VERSION 5.8 ;
BUSBITCHARS "[]" ;
DIVIDERCHAR "/" ;
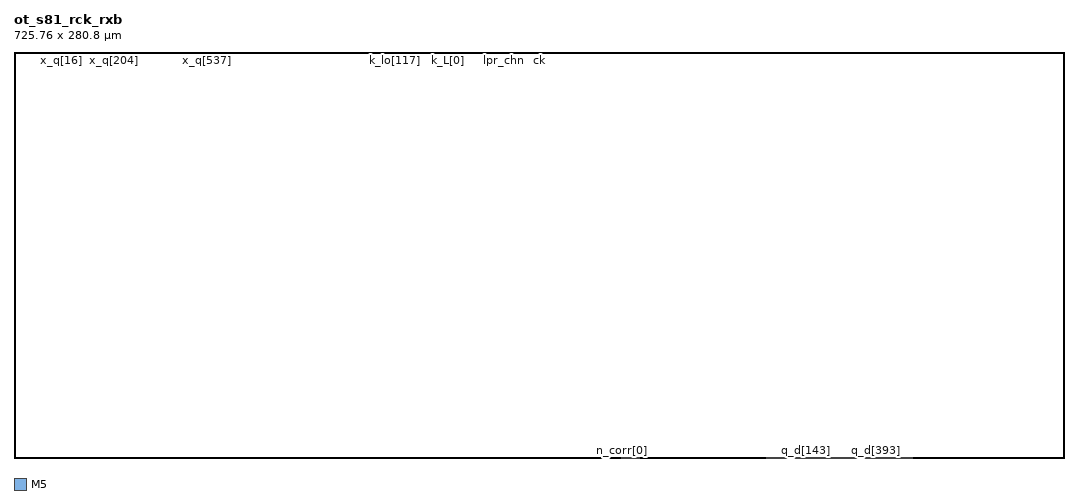
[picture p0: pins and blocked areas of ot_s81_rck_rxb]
MACRO ot_s81_rck_rxb
 CLASS BLOCK ;
 ORIGIN 0 0 ;
 SIZE 725.76 BY 280.8 ;
 SYMMETRY X Y ;
 PIN x_q[0]
  DIRECTION INPUT ;
  USE SIGNAL ;
  PORT
   LAYER M5 ;
   RECT 30.000 280.716 30.024 280.800 ;
  END
 END x_q[0]
 PIN x_q[1]
  DIRECTION INPUT ;
  USE SIGNAL ;
  PORT
   LAYER M5 ;
   RECT 30.192 280.716 30.216 280.800 ;
  END
 END x_q[1]
 PIN x_q[2]
  DIRECTION INPUT ;
  USE SIGNAL ;
  PORT
   LAYER M5 ;
   RECT 30.384 280.716 30.408 280.800 ;
  END
 END x_q[2]
 PIN x_q[3]
  DIRECTION INPUT ;
  USE SIGNAL ;
  PORT
   LAYER M5 ;
   RECT 30.576 280.716 30.600 280.800 ;
  END
 END x_q[3]
 PIN x_q[4]
  DIRECTION INPUT ;
  USE SIGNAL ;
  PORT
   LAYER M5 ;
   RECT 30.768 280.716 30.792 280.800 ;
  END
 END x_q[4]
 PIN x_q[5]
  DIRECTION INPUT ;
  USE SIGNAL ;
  PORT
   LAYER M5 ;
   RECT 30.960 280.716 30.984 280.800 ;
  END
 END x_q[5]
 PIN x_q[6]
  DIRECTION INPUT ;
  USE SIGNAL ;
  PORT
   LAYER M5 ;
   RECT 31.152 280.716 31.176 280.800 ;
  END
 END x_q[6]
 PIN x_q[7]
  DIRECTION INPUT ;
  USE SIGNAL ;
  PORT
   LAYER M5 ;
   RECT 31.344 280.716 31.368 280.800 ;
  END
 END x_q[7]
 PIN x_q[8]
  DIRECTION INPUT ;
  USE SIGNAL ;
  PORT
   LAYER M5 ;
   RECT 31.536 280.716 31.560 280.800 ;
  END
 END x_q[8]
 PIN x_q[9]
  DIRECTION INPUT ;
  USE SIGNAL ;
  PORT
   LAYER M5 ;
   RECT 31.728 280.716 31.752 280.800 ;
  END
 END x_q[9]
 PIN x_q[10]
  DIRECTION INPUT ;
  USE SIGNAL ;
  PORT
   LAYER M5 ;
   RECT 31.920 280.716 31.944 280.800 ;
  END
 END x_q[10]
 PIN x_q[11]
  DIRECTION INPUT ;
  USE SIGNAL ;
  PORT
   LAYER M5 ;
   RECT 32.112 280.716 32.136 280.800 ;
  END
 END x_q[11]
 PIN x_q[12]
  DIRECTION INPUT ;
  USE SIGNAL ;
  PORT
   LAYER M5 ;
   RECT 32.304 280.716 32.328 280.800 ;
  END
 END x_q[12]
 PIN x_q[13]
  DIRECTION INPUT ;
  USE SIGNAL ;
  PORT
   LAYER M5 ;
   RECT 32.496 280.716 32.520 280.800 ;
  END
 END x_q[13]
 PIN x_q[14]
  DIRECTION INPUT ;
  USE SIGNAL ;
  PORT
   LAYER M5 ;
   RECT 32.688 280.716 32.712 280.800 ;
  END
 END x_q[14]
 PIN x_q[15]
  DIRECTION INPUT ;
  USE SIGNAL ;
  PORT
   LAYER M5 ;
   RECT 32.880 280.716 32.904 280.800 ;
  END
 END x_q[15]
 PIN x_q[16]
  DIRECTION INPUT ;
  USE SIGNAL ;
  PORT
   LAYER M5 ;
   RECT 33.072 280.716 33.096 280.800 ;
  END
 END x_q[16]
 PIN x_q[17]
  DIRECTION INPUT ;
  USE SIGNAL ;
  PORT
   LAYER M5 ;
   RECT 33.264 280.716 33.288 280.800 ;
  END
 END x_q[17]
 PIN x_q[18]
  DIRECTION INPUT ;
  USE SIGNAL ;
  PORT
   LAYER M5 ;
   RECT 33.456 280.716 33.480 280.800 ;
  END
 END x_q[18]
 PIN x_q[19]
  DIRECTION INPUT ;
  USE SIGNAL ;
  PORT
   LAYER M5 ;
   RECT 33.648 280.716 33.672 280.800 ;
  END
 END x_q[19]
 PIN x_q[20]
  DIRECTION INPUT ;
  USE SIGNAL ;
  PORT
   LAYER M5 ;
   RECT 33.840 280.716 33.864 280.800 ;
  END
 END x_q[20]
 PIN x_q[21]
  DIRECTION INPUT ;
  USE SIGNAL ;
  PORT
   LAYER M5 ;
   RECT 34.032 280.716 34.056 280.800 ;
  END
 END x_q[21]
 PIN x_q[22]
  DIRECTION INPUT ;
  USE SIGNAL ;
  PORT
   LAYER M5 ;
   RECT 34.224 280.716 34.248 280.800 ;
  END
 END x_q[22]
 PIN x_q[23]
  DIRECTION INPUT ;
  USE SIGNAL ;
  PORT
   LAYER M5 ;
   RECT 34.416 280.716 34.440 280.800 ;
  END
 END x_q[23]
 PIN x_q[24]
  DIRECTION INPUT ;
  USE SIGNAL ;
  PORT
   LAYER M5 ;
   RECT 34.608 280.716 34.632 280.800 ;
  END
 END x_q[24]
 PIN x_q[25]
  DIRECTION INPUT ;
  USE SIGNAL ;
  PORT
   LAYER M5 ;
   RECT 34.800 280.716 34.824 280.800 ;
  END
 END x_q[25]
 PIN x_q[26]
  DIRECTION INPUT ;
  USE SIGNAL ;
  PORT
   LAYER M5 ;
   RECT 34.992 280.716 35.016 280.800 ;
  END
 END x_q[26]
 PIN x_q[27]
  DIRECTION INPUT ;
  USE SIGNAL ;
  PORT
   LAYER M5 ;
   RECT 35.184 280.716 35.208 280.800 ;
  END
 END x_q[27]
 PIN x_q[28]
  DIRECTION INPUT ;
  USE SIGNAL ;
  PORT
   LAYER M5 ;
   RECT 35.376 280.716 35.400 280.800 ;
  END
 END x_q[28]
 PIN x_q[29]
  DIRECTION INPUT ;
  USE SIGNAL ;
  PORT
   LAYER M5 ;
   RECT 35.568 280.716 35.592 280.800 ;
  END
 END x_q[29]
 PIN x_q[30]
  DIRECTION INPUT ;
  USE SIGNAL ;
  PORT
   LAYER M5 ;
   RECT 35.760 280.716 35.784 280.800 ;
  END
 END x_q[30]
 PIN x_q[31]
  DIRECTION INPUT ;
  USE SIGNAL ;
  PORT
   LAYER M5 ;
   RECT 35.952 280.716 35.976 280.800 ;
  END
 END x_q[31]
 PIN x_q[32]
  DIRECTION INPUT ;
  USE SIGNAL ;
  PORT
   LAYER M5 ;
   RECT 36.144 280.716 36.168 280.800 ;
  END
 END x_q[32]
 PIN x_q[33]
  DIRECTION INPUT ;
  USE SIGNAL ;
  PORT
   LAYER M5 ;
   RECT 36.336 280.716 36.360 280.800 ;
  END
 END x_q[33]
 PIN x_q[34]
  DIRECTION INPUT ;
  USE SIGNAL ;
  PORT
   LAYER M5 ;
   RECT 36.528 280.716 36.552 280.800 ;
  END
 END x_q[34]
 PIN x_q[35]
  DIRECTION INPUT ;
  USE SIGNAL ;
  PORT
   LAYER M5 ;
   RECT 36.720 280.716 36.744 280.800 ;
  END
 END x_q[35]
 PIN x_q[36]
  DIRECTION INPUT ;
  USE SIGNAL ;
  PORT
   LAYER M5 ;
   RECT 36.912 280.716 36.936 280.800 ;
  END
 END x_q[36]
 PIN x_q[37]
  DIRECTION INPUT ;
  USE SIGNAL ;
  PORT
   LAYER M5 ;
   RECT 37.104 280.716 37.128 280.800 ;
  END
 END x_q[37]
 PIN x_q[38]
  DIRECTION INPUT ;
  USE SIGNAL ;
  PORT
   LAYER M5 ;
   RECT 37.296 280.716 37.320 280.800 ;
  END
 END x_q[38]
 PIN x_q[39]
  DIRECTION INPUT ;
  USE SIGNAL ;
  PORT
   LAYER M5 ;
   RECT 37.488 280.716 37.512 280.800 ;
  END
 END x_q[39]
 PIN x_q[40]
  DIRECTION INPUT ;
  USE SIGNAL ;
  PORT
   LAYER M5 ;
   RECT 37.680 280.716 37.704 280.800 ;
  END
 END x_q[40]
 PIN x_q[41]
  DIRECTION INPUT ;
  USE SIGNAL ;
  PORT
   LAYER M5 ;
   RECT 37.872 280.716 37.896 280.800 ;
  END
 END x_q[41]
 PIN x_q[42]
  DIRECTION INPUT ;
  USE SIGNAL ;
  PORT
   LAYER M5 ;
   RECT 38.064 280.716 38.088 280.800 ;
  END
 END x_q[42]
 PIN x_q[43]
  DIRECTION INPUT ;
  USE SIGNAL ;
  PORT
   LAYER M5 ;
   RECT 38.256 280.716 38.280 280.800 ;
  END
 END x_q[43]
 PIN x_q[44]
  DIRECTION INPUT ;
  USE SIGNAL ;
  PORT
   LAYER M5 ;
   RECT 38.448 280.716 38.472 280.800 ;
  END
 END x_q[44]
 PIN x_q[45]
  DIRECTION INPUT ;
  USE SIGNAL ;
  PORT
   LAYER M5 ;
   RECT 38.640 280.716 38.664 280.800 ;
  END
 END x_q[45]
 PIN x_q[46]
  DIRECTION INPUT ;
  USE SIGNAL ;
  PORT
   LAYER M5 ;
   RECT 38.832 280.716 38.856 280.800 ;
  END
 END x_q[46]
 PIN x_q[47]
  DIRECTION INPUT ;
  USE SIGNAL ;
  PORT
   LAYER M5 ;
   RECT 39.024 280.716 39.048 280.800 ;
  END
 END x_q[47]
 PIN x_q[48]
  DIRECTION INPUT ;
  USE SIGNAL ;
  PORT
   LAYER M5 ;
   RECT 39.216 280.716 39.240 280.800 ;
  END
 END x_q[48]
 PIN x_q[49]
  DIRECTION INPUT ;
  USE SIGNAL ;
  PORT
   LAYER M5 ;
   RECT 39.408 280.716 39.432 280.800 ;
  END
 END x_q[49]
 PIN x_q[50]
  DIRECTION INPUT ;
  USE SIGNAL ;
  PORT
   LAYER M5 ;
   RECT 39.600 280.716 39.624 280.800 ;
  END
 END x_q[50]
 PIN x_q[51]
  DIRECTION INPUT ;
  USE SIGNAL ;
  PORT
   LAYER M5 ;
   RECT 39.792 280.716 39.816 280.800 ;
  END
 END x_q[51]
 PIN x_q[52]
  DIRECTION INPUT ;
  USE SIGNAL ;
  PORT
   LAYER M5 ;
   RECT 39.984 280.716 40.008 280.800 ;
  END
 END x_q[52]
 PIN x_q[53]
  DIRECTION INPUT ;
  USE SIGNAL ;
  PORT
   LAYER M5 ;
   RECT 40.176 280.716 40.200 280.800 ;
  END
 END x_q[53]
 PIN x_q[54]
  DIRECTION INPUT ;
  USE SIGNAL ;
  PORT
   LAYER M5 ;
   RECT 40.368 280.716 40.392 280.800 ;
  END
 END x_q[54]
 PIN x_q[55]
  DIRECTION INPUT ;
  USE SIGNAL ;
  PORT
   LAYER M5 ;
   RECT 40.560 280.716 40.584 280.800 ;
  END
 END x_q[55]
 PIN x_q[56]
  DIRECTION INPUT ;
  USE SIGNAL ;
  PORT
   LAYER M5 ;
   RECT 40.752 280.716 40.776 280.800 ;
  END
 END x_q[56]
 PIN x_q[57]
  DIRECTION INPUT ;
  USE SIGNAL ;
  PORT
   LAYER M5 ;
   RECT 40.944 280.716 40.968 280.800 ;
  END
 END x_q[57]
 PIN x_q[58]
  DIRECTION INPUT ;
  USE SIGNAL ;
  PORT
   LAYER M5 ;
   RECT 41.136 280.716 41.160 280.800 ;
  END
 END x_q[58]
 PIN x_q[59]
  DIRECTION INPUT ;
  USE SIGNAL ;
  PORT
   LAYER M5 ;
   RECT 41.328 280.716 41.352 280.800 ;
  END
 END x_q[59]
 PIN x_q[60]
  DIRECTION INPUT ;
  USE SIGNAL ;
  PORT
   LAYER M5 ;
   RECT 41.520 280.716 41.544 280.800 ;
  END
 END x_q[60]
 PIN x_q[61]
  DIRECTION INPUT ;
  USE SIGNAL ;
  PORT
   LAYER M5 ;
   RECT 41.712 280.716 41.736 280.800 ;
  END
 END x_q[61]
 PIN x_q[62]
  DIRECTION INPUT ;
  USE SIGNAL ;
  PORT
   LAYER M5 ;
   RECT 41.904 280.716 41.928 280.800 ;
  END
 END x_q[62]
 PIN x_q[63]
  DIRECTION INPUT ;
  USE SIGNAL ;
  PORT
   LAYER M5 ;
   RECT 42.096 280.716 42.120 280.800 ;
  END
 END x_q[63]
 PIN x_q[64]
  DIRECTION INPUT ;
  USE SIGNAL ;
  PORT
   LAYER M5 ;
   RECT 42.288 280.716 42.312 280.800 ;
  END
 END x_q[64]
 PIN x_q[65]
  DIRECTION INPUT ;
  USE SIGNAL ;
  PORT
   LAYER M5 ;
   RECT 42.480 280.716 42.504 280.800 ;
  END
 END x_q[65]
 PIN x_q[66]
  DIRECTION INPUT ;
  USE SIGNAL ;
  PORT
   LAYER M5 ;
   RECT 42.672 280.716 42.696 280.800 ;
  END
 END x_q[66]
 PIN x_q[67]
  DIRECTION INPUT ;
  USE SIGNAL ;
  PORT
   LAYER M5 ;
   RECT 42.864 280.716 42.888 280.800 ;
  END
 END x_q[67]
 PIN x_q[68]
  DIRECTION INPUT ;
  USE SIGNAL ;
  PORT
   LAYER M5 ;
   RECT 43.056 280.716 43.080 280.800 ;
  END
 END x_q[68]
 PIN x_q[69]
  DIRECTION INPUT ;
  USE SIGNAL ;
  PORT
   LAYER M5 ;
   RECT 43.248 280.716 43.272 280.800 ;
  END
 END x_q[69]
 PIN x_q[70]
  DIRECTION INPUT ;
  USE SIGNAL ;
  PORT
   LAYER M5 ;
   RECT 43.440 280.716 43.464 280.800 ;
  END
 END x_q[70]
 PIN x_q[71]
  DIRECTION INPUT ;
  USE SIGNAL ;
  PORT
   LAYER M5 ;
   RECT 43.632 280.716 43.656 280.800 ;
  END
 END x_q[71]
 PIN x_q[72]
  DIRECTION INPUT ;
  USE SIGNAL ;
  PORT
   LAYER M5 ;
   RECT 43.824 280.716 43.848 280.800 ;
  END
 END x_q[72]
 PIN x_q[73]
  DIRECTION INPUT ;
  USE SIGNAL ;
  PORT
   LAYER M5 ;
   RECT 44.016 280.716 44.040 280.800 ;
  END
 END x_q[73]
 PIN x_q[74]
  DIRECTION INPUT ;
  USE SIGNAL ;
  PORT
   LAYER M5 ;
   RECT 44.208 280.716 44.232 280.800 ;
  END
 END x_q[74]
 PIN x_q[75]
  DIRECTION INPUT ;
  USE SIGNAL ;
  PORT
   LAYER M5 ;
   RECT 44.400 280.716 44.424 280.800 ;
  END
 END x_q[75]
 PIN x_q[76]
  DIRECTION INPUT ;
  USE SIGNAL ;
  PORT
   LAYER M5 ;
   RECT 44.592 280.716 44.616 280.800 ;
  END
 END x_q[76]
 PIN x_q[77]
  DIRECTION INPUT ;
  USE SIGNAL ;
  PORT
   LAYER M5 ;
   RECT 44.784 280.716 44.808 280.800 ;
  END
 END x_q[77]
 PIN x_q[78]
  DIRECTION INPUT ;
  USE SIGNAL ;
  PORT
   LAYER M5 ;
   RECT 44.976 280.716 45.000 280.800 ;
  END
 END x_q[78]
 PIN x_q[79]
  DIRECTION INPUT ;
  USE SIGNAL ;
  PORT
   LAYER M5 ;
   RECT 45.168 280.716 45.192 280.800 ;
  END
 END x_q[79]
 PIN x_q[80]
  DIRECTION INPUT ;
  USE SIGNAL ;
  PORT
   LAYER M5 ;
   RECT 45.360 280.716 45.384 280.800 ;
  END
 END x_q[80]
 PIN x_q[81]
  DIRECTION INPUT ;
  USE SIGNAL ;
  PORT
   LAYER M5 ;
   RECT 45.552 280.716 45.576 280.800 ;
  END
 END x_q[81]
 PIN x_q[82]
  DIRECTION INPUT ;
  USE SIGNAL ;
  PORT
   LAYER M5 ;
   RECT 45.744 280.716 45.768 280.800 ;
  END
 END x_q[82]
 PIN x_q[83]
  DIRECTION INPUT ;
  USE SIGNAL ;
  PORT
   LAYER M5 ;
   RECT 45.936 280.716 45.960 280.800 ;
  END
 END x_q[83]
 PIN x_q[84]
  DIRECTION INPUT ;
  USE SIGNAL ;
  PORT
   LAYER M5 ;
   RECT 46.128 280.716 46.152 280.800 ;
  END
 END x_q[84]
 PIN x_q[85]
  DIRECTION INPUT ;
  USE SIGNAL ;
  PORT
   LAYER M5 ;
   RECT 46.320 280.716 46.344 280.800 ;
  END
 END x_q[85]
 PIN x_q[86]
  DIRECTION INPUT ;
  USE SIGNAL ;
  PORT
   LAYER M5 ;
   RECT 46.512 280.716 46.536 280.800 ;
  END
 END x_q[86]
 PIN x_q[87]
  DIRECTION INPUT ;
  USE SIGNAL ;
  PORT
   LAYER M5 ;
   RECT 46.704 280.716 46.728 280.800 ;
  END
 END x_q[87]
 PIN x_q[88]
  DIRECTION INPUT ;
  USE SIGNAL ;
  PORT
   LAYER M5 ;
   RECT 46.896 280.716 46.920 280.800 ;
  END
 END x_q[88]
 PIN x_q[89]
  DIRECTION INPUT ;
  USE SIGNAL ;
  PORT
   LAYER M5 ;
   RECT 47.088 280.716 47.112 280.800 ;
  END
 END x_q[89]
 PIN x_q[90]
  DIRECTION INPUT ;
  USE SIGNAL ;
  PORT
   LAYER M5 ;
   RECT 47.280 280.716 47.304 280.800 ;
  END
 END x_q[90]
 PIN x_q[91]
  DIRECTION INPUT ;
  USE SIGNAL ;
  PORT
   LAYER M5 ;
   RECT 47.472 280.716 47.496 280.800 ;
  END
 END x_q[91]
 PIN x_q[92]
  DIRECTION INPUT ;
  USE SIGNAL ;
  PORT
   LAYER M5 ;
   RECT 47.664 280.716 47.688 280.800 ;
  END
 END x_q[92]
 PIN x_q[93]
  DIRECTION INPUT ;
  USE SIGNAL ;
  PORT
   LAYER M5 ;
   RECT 47.856 280.716 47.880 280.800 ;
  END
 END x_q[93]
 PIN x_q[94]
  DIRECTION INPUT ;
  USE SIGNAL ;
  PORT
   LAYER M5 ;
   RECT 48.048 280.716 48.072 280.800 ;
  END
 END x_q[94]
 PIN x_q[95]
  DIRECTION INPUT ;
  USE SIGNAL ;
  PORT
   LAYER M5 ;
   RECT 48.240 280.716 48.264 280.800 ;
  END
 END x_q[95]
 PIN x_q[96]
  DIRECTION INPUT ;
  USE SIGNAL ;
  PORT
   LAYER M5 ;
   RECT 48.432 280.716 48.456 280.800 ;
  END
 END x_q[96]
 PIN x_q[97]
  DIRECTION INPUT ;
  USE SIGNAL ;
  PORT
   LAYER M5 ;
   RECT 48.624 280.716 48.648 280.800 ;
  END
 END x_q[97]
 PIN x_q[98]
  DIRECTION INPUT ;
  USE SIGNAL ;
  PORT
   LAYER M5 ;
   RECT 48.816 280.716 48.840 280.800 ;
  END
 END x_q[98]
 PIN x_q[99]
  DIRECTION INPUT ;
  USE SIGNAL ;
  PORT
   LAYER M5 ;
   RECT 49.008 280.716 49.032 280.800 ;
  END
 END x_q[99]
 PIN x_q[100]
  DIRECTION INPUT ;
  USE SIGNAL ;
  PORT
   LAYER M5 ;
   RECT 49.200 280.716 49.224 280.800 ;
  END
 END x_q[100]
 PIN x_q[101]
  DIRECTION INPUT ;
  USE SIGNAL ;
  PORT
   LAYER M5 ;
   RECT 49.392 280.716 49.416 280.800 ;
  END
 END x_q[101]
 PIN x_q[102]
  DIRECTION INPUT ;
  USE SIGNAL ;
  PORT
   LAYER M5 ;
   RECT 49.584 280.716 49.608 280.800 ;
  END
 END x_q[102]
 PIN x_q[103]
  DIRECTION INPUT ;
  USE SIGNAL ;
  PORT
   LAYER M5 ;
   RECT 49.776 280.716 49.800 280.800 ;
  END
 END x_q[103]
 PIN x_q[104]
  DIRECTION INPUT ;
  USE SIGNAL ;
  PORT
   LAYER M5 ;
   RECT 49.968 280.716 49.992 280.800 ;
  END
 END x_q[104]
 PIN x_q[105]
  DIRECTION INPUT ;
  USE SIGNAL ;
  PORT
   LAYER M5 ;
   RECT 50.160 280.716 50.184 280.800 ;
  END
 END x_q[105]
 PIN x_q[106]
  DIRECTION INPUT ;
  USE SIGNAL ;
  PORT
   LAYER M5 ;
   RECT 50.352 280.716 50.376 280.800 ;
  END
 END x_q[106]
 PIN x_q[107]
  DIRECTION INPUT ;
  USE SIGNAL ;
  PORT
   LAYER M5 ;
   RECT 50.544 280.716 50.568 280.800 ;
  END
 END x_q[107]
 PIN x_q[108]
  DIRECTION INPUT ;
  USE SIGNAL ;
  PORT
   LAYER M5 ;
   RECT 50.736 280.716 50.760 280.800 ;
  END
 END x_q[108]
 PIN x_q[109]
  DIRECTION INPUT ;
  USE SIGNAL ;
  PORT
   LAYER M5 ;
   RECT 50.928 280.716 50.952 280.800 ;
  END
 END x_q[109]
 PIN x_q[110]
  DIRECTION INPUT ;
  USE SIGNAL ;
  PORT
   LAYER M5 ;
   RECT 51.120 280.716 51.144 280.800 ;
  END
 END x_q[110]
 PIN x_q[111]
  DIRECTION INPUT ;
  USE SIGNAL ;
  PORT
   LAYER M5 ;
   RECT 51.312 280.716 51.336 280.800 ;
  END
 END x_q[111]
 PIN x_q[112]
  DIRECTION INPUT ;
  USE SIGNAL ;
  PORT
   LAYER M5 ;
   RECT 51.504 280.716 51.528 280.800 ;
  END
 END x_q[112]
 PIN x_q[113]
  DIRECTION INPUT ;
  USE SIGNAL ;
  PORT
   LAYER M5 ;
   RECT 51.696 280.716 51.720 280.800 ;
  END
 END x_q[113]
 PIN x_q[114]
  DIRECTION INPUT ;
  USE SIGNAL ;
  PORT
   LAYER M5 ;
   RECT 51.888 280.716 51.912 280.800 ;
  END
 END x_q[114]
 PIN x_q[115]
  DIRECTION INPUT ;
  USE SIGNAL ;
  PORT
   LAYER M5 ;
   RECT 52.080 280.716 52.104 280.800 ;
  END
 END x_q[115]
 PIN x_q[116]
  DIRECTION INPUT ;
  USE SIGNAL ;
  PORT
   LAYER M5 ;
   RECT 52.272 280.716 52.296 280.800 ;
  END
 END x_q[116]
 PIN x_q[117]
  DIRECTION INPUT ;
  USE SIGNAL ;
  PORT
   LAYER M5 ;
   RECT 52.464 280.716 52.488 280.800 ;
  END
 END x_q[117]
 PIN x_q[118]
  DIRECTION INPUT ;
  USE SIGNAL ;
  PORT
   LAYER M5 ;
   RECT 52.656 280.716 52.680 280.800 ;
  END
 END x_q[118]
 PIN x_q[119]
  DIRECTION INPUT ;
  USE SIGNAL ;
  PORT
   LAYER M5 ;
   RECT 52.848 280.716 52.872 280.800 ;
  END
 END x_q[119]
 PIN x_q[120]
  DIRECTION INPUT ;
  USE SIGNAL ;
  PORT
   LAYER M5 ;
   RECT 53.040 280.716 53.064 280.800 ;
  END
 END x_q[120]
 PIN x_q[121]
  DIRECTION INPUT ;
  USE SIGNAL ;
  PORT
   LAYER M5 ;
   RECT 53.232 280.716 53.256 280.800 ;
  END
 END x_q[121]
 PIN x_q[122]
  DIRECTION INPUT ;
  USE SIGNAL ;
  PORT
   LAYER M5 ;
   RECT 53.424 280.716 53.448 280.800 ;
  END
 END x_q[122]
 PIN x_q[123]
  DIRECTION INPUT ;
  USE SIGNAL ;
  PORT
   LAYER M5 ;
   RECT 53.616 280.716 53.640 280.800 ;
  END
 END x_q[123]
 PIN x_q[124]
  DIRECTION INPUT ;
  USE SIGNAL ;
  PORT
   LAYER M5 ;
   RECT 53.808 280.716 53.832 280.800 ;
  END
 END x_q[124]
 PIN x_q[125]
  DIRECTION INPUT ;
  USE SIGNAL ;
  PORT
   LAYER M5 ;
   RECT 54.000 280.716 54.024 280.800 ;
  END
 END x_q[125]
 PIN x_q[126]
  DIRECTION INPUT ;
  USE SIGNAL ;
  PORT
   LAYER M5 ;
   RECT 54.192 280.716 54.216 280.800 ;
  END
 END x_q[126]
 PIN x_q[127]
  DIRECTION INPUT ;
  USE SIGNAL ;
  PORT
   LAYER M5 ;
   RECT 54.384 280.716 54.408 280.800 ;
  END
 END x_q[127]
 PIN x_q[128]
  DIRECTION INPUT ;
  USE SIGNAL ;
  PORT
   LAYER M5 ;
   RECT 54.576 280.716 54.600 280.800 ;
  END
 END x_q[128]
 PIN x_q[129]
  DIRECTION INPUT ;
  USE SIGNAL ;
  PORT
   LAYER M5 ;
   RECT 54.768 280.716 54.792 280.800 ;
  END
 END x_q[129]
 PIN x_q[130]
  DIRECTION INPUT ;
  USE SIGNAL ;
  PORT
   LAYER M5 ;
   RECT 54.960 280.716 54.984 280.800 ;
  END
 END x_q[130]
 PIN x_q[131]
  DIRECTION INPUT ;
  USE SIGNAL ;
  PORT
   LAYER M5 ;
   RECT 55.152 280.716 55.176 280.800 ;
  END
 END x_q[131]
 PIN x_q[132]
  DIRECTION INPUT ;
  USE SIGNAL ;
  PORT
   LAYER M5 ;
   RECT 55.344 280.716 55.368 280.800 ;
  END
 END x_q[132]
 PIN x_q[133]
  DIRECTION INPUT ;
  USE SIGNAL ;
  PORT
   LAYER M5 ;
   RECT 55.536 280.716 55.560 280.800 ;
  END
 END x_q[133]
 PIN x_q[134]
  DIRECTION INPUT ;
  USE SIGNAL ;
  PORT
   LAYER M5 ;
   RECT 55.728 280.716 55.752 280.800 ;
  END
 END x_q[134]
 PIN x_q[135]
  DIRECTION INPUT ;
  USE SIGNAL ;
  PORT
   LAYER M5 ;
   RECT 55.920 280.716 55.944 280.800 ;
  END
 END x_q[135]
 PIN x_q[136]
  DIRECTION INPUT ;
  USE SIGNAL ;
  PORT
   LAYER M5 ;
   RECT 56.112 280.716 56.136 280.800 ;
  END
 END x_q[136]
 PIN x_q[137]
  DIRECTION INPUT ;
  USE SIGNAL ;
  PORT
   LAYER M5 ;
   RECT 56.304 280.716 56.328 280.800 ;
  END
 END x_q[137]
 PIN x_q[138]
  DIRECTION INPUT ;
  USE SIGNAL ;
  PORT
   LAYER M5 ;
   RECT 56.496 280.716 56.520 280.800 ;
  END
 END x_q[138]
 PIN x_q[139]
  DIRECTION INPUT ;
  USE SIGNAL ;
  PORT
   LAYER M5 ;
   RECT 56.688 280.716 56.712 280.800 ;
  END
 END x_q[139]
 PIN x_q[140]
  DIRECTION INPUT ;
  USE SIGNAL ;
  PORT
   LAYER M5 ;
   RECT 56.880 280.716 56.904 280.800 ;
  END
 END x_q[140]
 PIN x_q[141]
  DIRECTION INPUT ;
  USE SIGNAL ;
  PORT
   LAYER M5 ;
   RECT 57.072 280.716 57.096 280.800 ;
  END
 END x_q[141]
 PIN x_q[142]
  DIRECTION INPUT ;
  USE SIGNAL ;
  PORT
   LAYER M5 ;
   RECT 57.264 280.716 57.288 280.800 ;
  END
 END x_q[142]
 PIN x_q[143]
  DIRECTION INPUT ;
  USE SIGNAL ;
  PORT
   LAYER M5 ;
   RECT 57.456 280.716 57.480 280.800 ;
  END
 END x_q[143]
 PIN x_q[144]
  DIRECTION INPUT ;
  USE SIGNAL ;
  PORT
   LAYER M5 ;
   RECT 57.648 280.716 57.672 280.800 ;
  END
 END x_q[144]
 PIN x_q[145]
  DIRECTION INPUT ;
  USE SIGNAL ;
  PORT
   LAYER M5 ;
   RECT 57.840 280.716 57.864 280.800 ;
  END
 END x_q[145]
 PIN x_q[146]
  DIRECTION INPUT ;
  USE SIGNAL ;
  PORT
   LAYER M5 ;
   RECT 58.032 280.716 58.056 280.800 ;
  END
 END x_q[146]
 PIN x_q[147]
  DIRECTION INPUT ;
  USE SIGNAL ;
  PORT
   LAYER M5 ;
   RECT 58.224 280.716 58.248 280.800 ;
  END
 END x_q[147]
 PIN x_q[148]
  DIRECTION INPUT ;
  USE SIGNAL ;
  PORT
   LAYER M5 ;
   RECT 58.416 280.716 58.440 280.800 ;
  END
 END x_q[148]
 PIN x_q[149]
  DIRECTION INPUT ;
  USE SIGNAL ;
  PORT
   LAYER M5 ;
   RECT 58.608 280.716 58.632 280.800 ;
  END
 END x_q[149]
 PIN x_q[150]
  DIRECTION INPUT ;
  USE SIGNAL ;
  PORT
   LAYER M5 ;
   RECT 58.800 280.716 58.824 280.800 ;
  END
 END x_q[150]
 PIN x_q[151]
  DIRECTION INPUT ;
  USE SIGNAL ;
  PORT
   LAYER M5 ;
   RECT 58.992 280.716 59.016 280.800 ;
  END
 END x_q[151]
 PIN x_q[152]
  DIRECTION INPUT ;
  USE SIGNAL ;
  PORT
   LAYER M5 ;
   RECT 59.184 280.716 59.208 280.800 ;
  END
 END x_q[152]
 PIN x_q[153]
  DIRECTION INPUT ;
  USE SIGNAL ;
  PORT
   LAYER M5 ;
   RECT 59.376 280.716 59.400 280.800 ;
  END
 END x_q[153]
 PIN x_q[154]
  DIRECTION INPUT ;
  USE SIGNAL ;
  PORT
   LAYER M5 ;
   RECT 59.568 280.716 59.592 280.800 ;
  END
 END x_q[154]
 PIN x_q[155]
  DIRECTION INPUT ;
  USE SIGNAL ;
  PORT
   LAYER M5 ;
   RECT 59.760 280.716 59.784 280.800 ;
  END
 END x_q[155]
 PIN x_q[156]
  DIRECTION INPUT ;
  USE SIGNAL ;
  PORT
   LAYER M5 ;
   RECT 59.952 280.716 59.976 280.800 ;
  END
 END x_q[156]
 PIN x_q[157]
  DIRECTION INPUT ;
  USE SIGNAL ;
  PORT
   LAYER M5 ;
   RECT 60.144 280.716 60.168 280.800 ;
  END
 END x_q[157]
 PIN x_q[158]
  DIRECTION INPUT ;
  USE SIGNAL ;
  PORT
   LAYER M5 ;
   RECT 60.336 280.716 60.360 280.800 ;
  END
 END x_q[158]
 PIN x_q[159]
  DIRECTION INPUT ;
  USE SIGNAL ;
  PORT
   LAYER M5 ;
   RECT 60.528 280.716 60.552 280.800 ;
  END
 END x_q[159]
 PIN x_q[160]
  DIRECTION INPUT ;
  USE SIGNAL ;
  PORT
   LAYER M5 ;
   RECT 60.720 280.716 60.744 280.800 ;
  END
 END x_q[160]
 PIN x_q[161]
  DIRECTION INPUT ;
  USE SIGNAL ;
  PORT
   LAYER M5 ;
   RECT 60.912 280.716 60.936 280.800 ;
  END
 END x_q[161]
 PIN x_q[162]
  DIRECTION INPUT ;
  USE SIGNAL ;
  PORT
   LAYER M5 ;
   RECT 61.104 280.716 61.128 280.800 ;
  END
 END x_q[162]
 PIN x_q[163]
  DIRECTION INPUT ;
  USE SIGNAL ;
  PORT
   LAYER M5 ;
   RECT 61.296 280.716 61.320 280.800 ;
  END
 END x_q[163]
 PIN x_q[164]
  DIRECTION INPUT ;
  USE SIGNAL ;
  PORT
   LAYER M5 ;
   RECT 61.488 280.716 61.512 280.800 ;
  END
 END x_q[164]
 PIN x_q[165]
  DIRECTION INPUT ;
  USE SIGNAL ;
  PORT
   LAYER M5 ;
   RECT 61.680 280.716 61.704 280.800 ;
  END
 END x_q[165]
 PIN x_q[166]
  DIRECTION INPUT ;
  USE SIGNAL ;
  PORT
   LAYER M5 ;
   RECT 61.872 280.716 61.896 280.800 ;
  END
 END x_q[166]
 PIN x_q[167]
  DIRECTION INPUT ;
  USE SIGNAL ;
  PORT
   LAYER M5 ;
   RECT 62.064 280.716 62.088 280.800 ;
  END
 END x_q[167]
 PIN x_q[168]
  DIRECTION INPUT ;
  USE SIGNAL ;
  PORT
   LAYER M5 ;
   RECT 62.256 280.716 62.280 280.800 ;
  END
 END x_q[168]
 PIN x_q[169]
  DIRECTION INPUT ;
  USE SIGNAL ;
  PORT
   LAYER M5 ;
   RECT 62.448 280.716 62.472 280.800 ;
  END
 END x_q[169]
 PIN x_q[170]
  DIRECTION INPUT ;
  USE SIGNAL ;
  PORT
   LAYER M5 ;
   RECT 62.640 280.716 62.664 280.800 ;
  END
 END x_q[170]
 PIN x_q[171]
  DIRECTION INPUT ;
  USE SIGNAL ;
  PORT
   LAYER M5 ;
   RECT 62.832 280.716 62.856 280.800 ;
  END
 END x_q[171]
 PIN x_q[172]
  DIRECTION INPUT ;
  USE SIGNAL ;
  PORT
   LAYER M5 ;
   RECT 63.024 280.716 63.048 280.800 ;
  END
 END x_q[172]
 PIN x_q[173]
  DIRECTION INPUT ;
  USE SIGNAL ;
  PORT
   LAYER M5 ;
   RECT 63.216 280.716 63.240 280.800 ;
  END
 END x_q[173]
 PIN x_q[174]
  DIRECTION INPUT ;
  USE SIGNAL ;
  PORT
   LAYER M5 ;
   RECT 63.408 280.716 63.432 280.800 ;
  END
 END x_q[174]
 PIN x_q[175]
  DIRECTION INPUT ;
  USE SIGNAL ;
  PORT
   LAYER M5 ;
   RECT 63.600 280.716 63.624 280.800 ;
  END
 END x_q[175]
 PIN x_q[176]
  DIRECTION INPUT ;
  USE SIGNAL ;
  PORT
   LAYER M5 ;
   RECT 63.792 280.716 63.816 280.800 ;
  END
 END x_q[176]
 PIN x_q[177]
  DIRECTION INPUT ;
  USE SIGNAL ;
  PORT
   LAYER M5 ;
   RECT 63.984 280.716 64.008 280.800 ;
  END
 END x_q[177]
 PIN x_q[178]
  DIRECTION INPUT ;
  USE SIGNAL ;
  PORT
   LAYER M5 ;
   RECT 64.176 280.716 64.200 280.800 ;
  END
 END x_q[178]
 PIN x_q[179]
  DIRECTION INPUT ;
  USE SIGNAL ;
  PORT
   LAYER M5 ;
   RECT 64.368 280.716 64.392 280.800 ;
  END
 END x_q[179]
 PIN x_q[180]
  DIRECTION INPUT ;
  USE SIGNAL ;
  PORT
   LAYER M5 ;
   RECT 64.560 280.716 64.584 280.800 ;
  END
 END x_q[180]
 PIN x_q[181]
  DIRECTION INPUT ;
  USE SIGNAL ;
  PORT
   LAYER M5 ;
   RECT 64.752 280.716 64.776 280.800 ;
  END
 END x_q[181]
 PIN x_q[182]
  DIRECTION INPUT ;
  USE SIGNAL ;
  PORT
   LAYER M5 ;
   RECT 64.944 280.716 64.968 280.800 ;
  END
 END x_q[182]
 PIN x_q[183]
  DIRECTION INPUT ;
  USE SIGNAL ;
  PORT
   LAYER M5 ;
   RECT 65.136 280.716 65.160 280.800 ;
  END
 END x_q[183]
 PIN x_q[184]
  DIRECTION INPUT ;
  USE SIGNAL ;
  PORT
   LAYER M5 ;
   RECT 65.328 280.716 65.352 280.800 ;
  END
 END x_q[184]
 PIN x_q[185]
  DIRECTION INPUT ;
  USE SIGNAL ;
  PORT
   LAYER M5 ;
   RECT 65.520 280.716 65.544 280.800 ;
  END
 END x_q[185]
 PIN x_q[186]
  DIRECTION INPUT ;
  USE SIGNAL ;
  PORT
   LAYER M5 ;
   RECT 65.712 280.716 65.736 280.800 ;
  END
 END x_q[186]
 PIN x_q[187]
  DIRECTION INPUT ;
  USE SIGNAL ;
  PORT
   LAYER M5 ;
   RECT 65.904 280.716 65.928 280.800 ;
  END
 END x_q[187]
 PIN x_q[188]
  DIRECTION INPUT ;
  USE SIGNAL ;
  PORT
   LAYER M5 ;
   RECT 66.096 280.716 66.120 280.800 ;
  END
 END x_q[188]
 PIN x_q[189]
  DIRECTION INPUT ;
  USE SIGNAL ;
  PORT
   LAYER M5 ;
   RECT 66.288 280.716 66.312 280.800 ;
  END
 END x_q[189]
 PIN x_q[190]
  DIRECTION INPUT ;
  USE SIGNAL ;
  PORT
   LAYER M5 ;
   RECT 66.480 280.716 66.504 280.800 ;
  END
 END x_q[190]
 PIN x_q[191]
  DIRECTION INPUT ;
  USE SIGNAL ;
  PORT
   LAYER M5 ;
   RECT 66.672 280.716 66.696 280.800 ;
  END
 END x_q[191]
 PIN x_q[192]
  DIRECTION INPUT ;
  USE SIGNAL ;
  PORT
   LAYER M5 ;
   RECT 66.864 280.716 66.888 280.800 ;
  END
 END x_q[192]
 PIN x_q[193]
  DIRECTION INPUT ;
  USE SIGNAL ;
  PORT
   LAYER M5 ;
   RECT 67.056 280.716 67.080 280.800 ;
  END
 END x_q[193]
 PIN x_q[194]
  DIRECTION INPUT ;
  USE SIGNAL ;
  PORT
   LAYER M5 ;
   RECT 67.248 280.716 67.272 280.800 ;
  END
 END x_q[194]
 PIN x_q[195]
  DIRECTION INPUT ;
  USE SIGNAL ;
  PORT
   LAYER M5 ;
   RECT 67.440 280.716 67.464 280.800 ;
  END
 END x_q[195]
 PIN x_q[196]
  DIRECTION INPUT ;
  USE SIGNAL ;
  PORT
   LAYER M5 ;
   RECT 67.632 280.716 67.656 280.800 ;
  END
 END x_q[196]
 PIN x_q[197]
  DIRECTION INPUT ;
  USE SIGNAL ;
  PORT
   LAYER M5 ;
   RECT 67.824 280.716 67.848 280.800 ;
  END
 END x_q[197]
 PIN x_q[198]
  DIRECTION INPUT ;
  USE SIGNAL ;
  PORT
   LAYER M5 ;
   RECT 68.016 280.716 68.040 280.800 ;
  END
 END x_q[198]
 PIN x_q[199]
  DIRECTION INPUT ;
  USE SIGNAL ;
  PORT
   LAYER M5 ;
   RECT 68.208 280.716 68.232 280.800 ;
  END
 END x_q[199]
 PIN x_q[200]
  DIRECTION INPUT ;
  USE SIGNAL ;
  PORT
   LAYER M5 ;
   RECT 68.400 280.716 68.424 280.800 ;
  END
 END x_q[200]
 PIN x_q[201]
  DIRECTION INPUT ;
  USE SIGNAL ;
  PORT
   LAYER M5 ;
   RECT 68.592 280.716 68.616 280.800 ;
  END
 END x_q[201]
 PIN x_q[202]
  DIRECTION INPUT ;
  USE SIGNAL ;
  PORT
   LAYER M5 ;
   RECT 68.784 280.716 68.808 280.800 ;
  END
 END x_q[202]
 PIN x_q[203]
  DIRECTION INPUT ;
  USE SIGNAL ;
  PORT
   LAYER M5 ;
   RECT 68.976 280.716 69.000 280.800 ;
  END
 END x_q[203]
 PIN x_q[204]
  DIRECTION INPUT ;
  USE SIGNAL ;
  PORT
   LAYER M5 ;
   RECT 69.168 280.716 69.192 280.800 ;
  END
 END x_q[204]
 PIN x_q[205]
  DIRECTION INPUT ;
  USE SIGNAL ;
  PORT
   LAYER M5 ;
   RECT 69.360 280.716 69.384 280.800 ;
  END
 END x_q[205]
 PIN x_q[206]
  DIRECTION INPUT ;
  USE SIGNAL ;
  PORT
   LAYER M5 ;
   RECT 69.552 280.716 69.576 280.800 ;
  END
 END x_q[206]
 PIN x_q[207]
  DIRECTION INPUT ;
  USE SIGNAL ;
  PORT
   LAYER M5 ;
   RECT 69.744 280.716 69.768 280.800 ;
  END
 END x_q[207]
 PIN x_q[208]
  DIRECTION INPUT ;
  USE SIGNAL ;
  PORT
   LAYER M5 ;
   RECT 69.936 280.716 69.960 280.800 ;
  END
 END x_q[208]
 PIN x_q[209]
  DIRECTION INPUT ;
  USE SIGNAL ;
  PORT
   LAYER M5 ;
   RECT 70.128 280.716 70.152 280.800 ;
  END
 END x_q[209]
 PIN x_q[210]
  DIRECTION INPUT ;
  USE SIGNAL ;
  PORT
   LAYER M5 ;
   RECT 70.320 280.716 70.344 280.800 ;
  END
 END x_q[210]
 PIN x_q[211]
  DIRECTION INPUT ;
  USE SIGNAL ;
  PORT
   LAYER M5 ;
   RECT 70.512 280.716 70.536 280.800 ;
  END
 END x_q[211]
 PIN x_q[212]
  DIRECTION INPUT ;
  USE SIGNAL ;
  PORT
   LAYER M5 ;
   RECT 70.704 280.716 70.728 280.800 ;
  END
 END x_q[212]
 PIN x_q[213]
  DIRECTION INPUT ;
  USE SIGNAL ;
  PORT
   LAYER M5 ;
   RECT 70.896 280.716 70.920 280.800 ;
  END
 END x_q[213]
 PIN x_q[214]
  DIRECTION INPUT ;
  USE SIGNAL ;
  PORT
   LAYER M5 ;
   RECT 71.088 280.716 71.112 280.800 ;
  END
 END x_q[214]
 PIN x_q[215]
  DIRECTION INPUT ;
  USE SIGNAL ;
  PORT
   LAYER M5 ;
   RECT 71.280 280.716 71.304 280.800 ;
  END
 END x_q[215]
 PIN x_q[216]
  DIRECTION INPUT ;
  USE SIGNAL ;
  PORT
   LAYER M5 ;
   RECT 71.472 280.716 71.496 280.800 ;
  END
 END x_q[216]
 PIN x_q[217]
  DIRECTION INPUT ;
  USE SIGNAL ;
  PORT
   LAYER M5 ;
   RECT 71.664 280.716 71.688 280.800 ;
  END
 END x_q[217]
 PIN x_q[218]
  DIRECTION INPUT ;
  USE SIGNAL ;
  PORT
   LAYER M5 ;
   RECT 71.856 280.716 71.880 280.800 ;
  END
 END x_q[218]
 PIN x_q[219]
  DIRECTION INPUT ;
  USE SIGNAL ;
  PORT
   LAYER M5 ;
   RECT 72.048 280.716 72.072 280.800 ;
  END
 END x_q[219]
 PIN x_q[220]
  DIRECTION INPUT ;
  USE SIGNAL ;
  PORT
   LAYER M5 ;
   RECT 72.240 280.716 72.264 280.800 ;
  END
 END x_q[220]
 PIN x_q[221]
  DIRECTION INPUT ;
  USE SIGNAL ;
  PORT
   LAYER M5 ;
   RECT 72.432 280.716 72.456 280.800 ;
  END
 END x_q[221]
 PIN x_q[222]
  DIRECTION INPUT ;
  USE SIGNAL ;
  PORT
   LAYER M5 ;
   RECT 72.624 280.716 72.648 280.800 ;
  END
 END x_q[222]
 PIN x_q[223]
  DIRECTION INPUT ;
  USE SIGNAL ;
  PORT
   LAYER M5 ;
   RECT 72.816 280.716 72.840 280.800 ;
  END
 END x_q[223]
 PIN x_q[224]
  DIRECTION INPUT ;
  USE SIGNAL ;
  PORT
   LAYER M5 ;
   RECT 73.008 280.716 73.032 280.800 ;
  END
 END x_q[224]
 PIN x_q[225]
  DIRECTION INPUT ;
  USE SIGNAL ;
  PORT
   LAYER M5 ;
   RECT 73.200 280.716 73.224 280.800 ;
  END
 END x_q[225]
 PIN x_q[226]
  DIRECTION INPUT ;
  USE SIGNAL ;
  PORT
   LAYER M5 ;
   RECT 73.392 280.716 73.416 280.800 ;
  END
 END x_q[226]
 PIN x_q[227]
  DIRECTION INPUT ;
  USE SIGNAL ;
  PORT
   LAYER M5 ;
   RECT 73.584 280.716 73.608 280.800 ;
  END
 END x_q[227]
 PIN x_q[228]
  DIRECTION INPUT ;
  USE SIGNAL ;
  PORT
   LAYER M5 ;
   RECT 73.776 280.716 73.800 280.800 ;
  END
 END x_q[228]
 PIN x_q[229]
  DIRECTION INPUT ;
  USE SIGNAL ;
  PORT
   LAYER M5 ;
   RECT 73.968 280.716 73.992 280.800 ;
  END
 END x_q[229]
 PIN x_q[230]
  DIRECTION INPUT ;
  USE SIGNAL ;
  PORT
   LAYER M5 ;
   RECT 74.160 280.716 74.184 280.800 ;
  END
 END x_q[230]
 PIN x_q[231]
  DIRECTION INPUT ;
  USE SIGNAL ;
  PORT
   LAYER M5 ;
   RECT 74.352 280.716 74.376 280.800 ;
  END
 END x_q[231]
 PIN x_q[232]
  DIRECTION INPUT ;
  USE SIGNAL ;
  PORT
   LAYER M5 ;
   RECT 74.544 280.716 74.568 280.800 ;
  END
 END x_q[232]
 PIN x_q[233]
  DIRECTION INPUT ;
  USE SIGNAL ;
  PORT
   LAYER M5 ;
   RECT 74.736 280.716 74.760 280.800 ;
  END
 END x_q[233]
 PIN x_q[234]
  DIRECTION INPUT ;
  USE SIGNAL ;
  PORT
   LAYER M5 ;
   RECT 74.928 280.716 74.952 280.800 ;
  END
 END x_q[234]
 PIN x_q[235]
  DIRECTION INPUT ;
  USE SIGNAL ;
  PORT
   LAYER M5 ;
   RECT 75.120 280.716 75.144 280.800 ;
  END
 END x_q[235]
 PIN x_q[236]
  DIRECTION INPUT ;
  USE SIGNAL ;
  PORT
   LAYER M5 ;
   RECT 75.312 280.716 75.336 280.800 ;
  END
 END x_q[236]
 PIN x_q[237]
  DIRECTION INPUT ;
  USE SIGNAL ;
  PORT
   LAYER M5 ;
   RECT 75.504 280.716 75.528 280.800 ;
  END
 END x_q[237]
 PIN x_q[238]
  DIRECTION INPUT ;
  USE SIGNAL ;
  PORT
   LAYER M5 ;
   RECT 75.696 280.716 75.720 280.800 ;
  END
 END x_q[238]
 PIN x_q[239]
  DIRECTION INPUT ;
  USE SIGNAL ;
  PORT
   LAYER M5 ;
   RECT 75.888 280.716 75.912 280.800 ;
  END
 END x_q[239]
 PIN x_q[240]
  DIRECTION INPUT ;
  USE SIGNAL ;
  PORT
   LAYER M5 ;
   RECT 76.080 280.716 76.104 280.800 ;
  END
 END x_q[240]
 PIN x_q[241]
  DIRECTION INPUT ;
  USE SIGNAL ;
  PORT
   LAYER M5 ;
   RECT 76.272 280.716 76.296 280.800 ;
  END
 END x_q[241]
 PIN x_q[242]
  DIRECTION INPUT ;
  USE SIGNAL ;
  PORT
   LAYER M5 ;
   RECT 76.464 280.716 76.488 280.800 ;
  END
 END x_q[242]
 PIN x_q[243]
  DIRECTION INPUT ;
  USE SIGNAL ;
  PORT
   LAYER M5 ;
   RECT 76.656 280.716 76.680 280.800 ;
  END
 END x_q[243]
 PIN x_q[244]
  DIRECTION INPUT ;
  USE SIGNAL ;
  PORT
   LAYER M5 ;
   RECT 76.848 280.716 76.872 280.800 ;
  END
 END x_q[244]
 PIN x_q[245]
  DIRECTION INPUT ;
  USE SIGNAL ;
  PORT
   LAYER M5 ;
   RECT 77.040 280.716 77.064 280.800 ;
  END
 END x_q[245]
 PIN x_q[246]
  DIRECTION INPUT ;
  USE SIGNAL ;
  PORT
   LAYER M5 ;
   RECT 77.232 280.716 77.256 280.800 ;
  END
 END x_q[246]
 PIN x_q[247]
  DIRECTION INPUT ;
  USE SIGNAL ;
  PORT
   LAYER M5 ;
   RECT 77.424 280.716 77.448 280.800 ;
  END
 END x_q[247]
 PIN x_q[248]
  DIRECTION INPUT ;
  USE SIGNAL ;
  PORT
   LAYER M5 ;
   RECT 77.616 280.716 77.640 280.800 ;
  END
 END x_q[248]
 PIN x_q[249]
  DIRECTION INPUT ;
  USE SIGNAL ;
  PORT
   LAYER M5 ;
   RECT 77.808 280.716 77.832 280.800 ;
  END
 END x_q[249]
 PIN x_q[250]
  DIRECTION INPUT ;
  USE SIGNAL ;
  PORT
   LAYER M5 ;
   RECT 78.000 280.716 78.024 280.800 ;
  END
 END x_q[250]
 PIN x_q[251]
  DIRECTION INPUT ;
  USE SIGNAL ;
  PORT
   LAYER M5 ;
   RECT 78.192 280.716 78.216 280.800 ;
  END
 END x_q[251]
 PIN x_q[252]
  DIRECTION INPUT ;
  USE SIGNAL ;
  PORT
   LAYER M5 ;
   RECT 78.384 280.716 78.408 280.800 ;
  END
 END x_q[252]
 PIN x_q[253]
  DIRECTION INPUT ;
  USE SIGNAL ;
  PORT
   LAYER M5 ;
   RECT 78.576 280.716 78.600 280.800 ;
  END
 END x_q[253]
 PIN x_q[254]
  DIRECTION INPUT ;
  USE SIGNAL ;
  PORT
   LAYER M5 ;
   RECT 78.768 280.716 78.792 280.800 ;
  END
 END x_q[254]
 PIN x_q[255]
  DIRECTION INPUT ;
  USE SIGNAL ;
  PORT
   LAYER M5 ;
   RECT 78.960 280.716 78.984 280.800 ;
  END
 END x_q[255]
 PIN x_q[256]
  DIRECTION INPUT ;
  USE SIGNAL ;
  PORT
   LAYER M5 ;
   RECT 79.152 280.716 79.176 280.800 ;
  END
 END x_q[256]
 PIN x_q[257]
  DIRECTION INPUT ;
  USE SIGNAL ;
  PORT
   LAYER M5 ;
   RECT 79.344 280.716 79.368 280.800 ;
  END
 END x_q[257]
 PIN x_q[258]
  DIRECTION INPUT ;
  USE SIGNAL ;
  PORT
   LAYER M5 ;
   RECT 79.536 280.716 79.560 280.800 ;
  END
 END x_q[258]
 PIN x_q[259]
  DIRECTION INPUT ;
  USE SIGNAL ;
  PORT
   LAYER M5 ;
   RECT 79.728 280.716 79.752 280.800 ;
  END
 END x_q[259]
 PIN x_q[260]
  DIRECTION INPUT ;
  USE SIGNAL ;
  PORT
   LAYER M5 ;
   RECT 79.920 280.716 79.944 280.800 ;
  END
 END x_q[260]
 PIN x_q[261]
  DIRECTION INPUT ;
  USE SIGNAL ;
  PORT
   LAYER M5 ;
   RECT 80.112 280.716 80.136 280.800 ;
  END
 END x_q[261]
 PIN x_q[262]
  DIRECTION INPUT ;
  USE SIGNAL ;
  PORT
   LAYER M5 ;
   RECT 80.304 280.716 80.328 280.800 ;
  END
 END x_q[262]
 PIN x_q[263]
  DIRECTION INPUT ;
  USE SIGNAL ;
  PORT
   LAYER M5 ;
   RECT 80.496 280.716 80.520 280.800 ;
  END
 END x_q[263]
 PIN x_q[264]
  DIRECTION INPUT ;
  USE SIGNAL ;
  PORT
   LAYER M5 ;
   RECT 80.688 280.716 80.712 280.800 ;
  END
 END x_q[264]
 PIN x_q[265]
  DIRECTION INPUT ;
  USE SIGNAL ;
  PORT
   LAYER M5 ;
   RECT 80.880 280.716 80.904 280.800 ;
  END
 END x_q[265]
 PIN x_q[266]
  DIRECTION INPUT ;
  USE SIGNAL ;
  PORT
   LAYER M5 ;
   RECT 81.072 280.716 81.096 280.800 ;
  END
 END x_q[266]
 PIN x_q[267]
  DIRECTION INPUT ;
  USE SIGNAL ;
  PORT
   LAYER M5 ;
   RECT 81.264 280.716 81.288 280.800 ;
  END
 END x_q[267]
 PIN x_q[268]
  DIRECTION INPUT ;
  USE SIGNAL ;
  PORT
   LAYER M5 ;
   RECT 81.456 280.716 81.480 280.800 ;
  END
 END x_q[268]
 PIN x_q[269]
  DIRECTION INPUT ;
  USE SIGNAL ;
  PORT
   LAYER M5 ;
   RECT 81.648 280.716 81.672 280.800 ;
  END
 END x_q[269]
 PIN x_q[270]
  DIRECTION INPUT ;
  USE SIGNAL ;
  PORT
   LAYER M5 ;
   RECT 81.840 280.716 81.864 280.800 ;
  END
 END x_q[270]
 PIN x_q[271]
  DIRECTION INPUT ;
  USE SIGNAL ;
  PORT
   LAYER M5 ;
   RECT 82.032 280.716 82.056 280.800 ;
  END
 END x_q[271]
 PIN x_q[272]
  DIRECTION INPUT ;
  USE SIGNAL ;
  PORT
   LAYER M5 ;
   RECT 82.224 280.716 82.248 280.800 ;
  END
 END x_q[272]
 PIN x_q[273]
  DIRECTION INPUT ;
  USE SIGNAL ;
  PORT
   LAYER M5 ;
   RECT 82.416 280.716 82.440 280.800 ;
  END
 END x_q[273]
 PIN x_q[274]
  DIRECTION INPUT ;
  USE SIGNAL ;
  PORT
   LAYER M5 ;
   RECT 82.608 280.716 82.632 280.800 ;
  END
 END x_q[274]
 PIN x_q[275]
  DIRECTION INPUT ;
  USE SIGNAL ;
  PORT
   LAYER M5 ;
   RECT 82.800 280.716 82.824 280.800 ;
  END
 END x_q[275]
 PIN x_q[276]
  DIRECTION INPUT ;
  USE SIGNAL ;
  PORT
   LAYER M5 ;
   RECT 82.992 280.716 83.016 280.800 ;
  END
 END x_q[276]
 PIN x_q[277]
  DIRECTION INPUT ;
  USE SIGNAL ;
  PORT
   LAYER M5 ;
   RECT 83.184 280.716 83.208 280.800 ;
  END
 END x_q[277]
 PIN x_q[278]
  DIRECTION INPUT ;
  USE SIGNAL ;
  PORT
   LAYER M5 ;
   RECT 83.376 280.716 83.400 280.800 ;
  END
 END x_q[278]
 PIN x_q[279]
  DIRECTION INPUT ;
  USE SIGNAL ;
  PORT
   LAYER M5 ;
   RECT 83.568 280.716 83.592 280.800 ;
  END
 END x_q[279]
 PIN x_q[280]
  DIRECTION INPUT ;
  USE SIGNAL ;
  PORT
   LAYER M5 ;
   RECT 83.760 280.716 83.784 280.800 ;
  END
 END x_q[280]
 PIN x_q[281]
  DIRECTION INPUT ;
  USE SIGNAL ;
  PORT
   LAYER M5 ;
   RECT 83.952 280.716 83.976 280.800 ;
  END
 END x_q[281]
 PIN x_q[282]
  DIRECTION INPUT ;
  USE SIGNAL ;
  PORT
   LAYER M5 ;
   RECT 84.144 280.716 84.168 280.800 ;
  END
 END x_q[282]
 PIN x_q[283]
  DIRECTION INPUT ;
  USE SIGNAL ;
  PORT
   LAYER M5 ;
   RECT 84.336 280.716 84.360 280.800 ;
  END
 END x_q[283]
 PIN x_q[284]
  DIRECTION INPUT ;
  USE SIGNAL ;
  PORT
   LAYER M5 ;
   RECT 84.528 280.716 84.552 280.800 ;
  END
 END x_q[284]
 PIN x_q[285]
  DIRECTION INPUT ;
  USE SIGNAL ;
  PORT
   LAYER M5 ;
   RECT 84.720 280.716 84.744 280.800 ;
  END
 END x_q[285]
 PIN x_q[286]
  DIRECTION INPUT ;
  USE SIGNAL ;
  PORT
   LAYER M5 ;
   RECT 84.912 280.716 84.936 280.800 ;
  END
 END x_q[286]
 PIN x_q[287]
  DIRECTION INPUT ;
  USE SIGNAL ;
  PORT
   LAYER M5 ;
   RECT 85.104 280.716 85.128 280.800 ;
  END
 END x_q[287]
 PIN x_q[288]
  DIRECTION INPUT ;
  USE SIGNAL ;
  PORT
   LAYER M5 ;
   RECT 85.296 280.716 85.320 280.800 ;
  END
 END x_q[288]
 PIN x_q[289]
  DIRECTION INPUT ;
  USE SIGNAL ;
  PORT
   LAYER M5 ;
   RECT 85.488 280.716 85.512 280.800 ;
  END
 END x_q[289]
 PIN x_q[290]
  DIRECTION INPUT ;
  USE SIGNAL ;
  PORT
   LAYER M5 ;
   RECT 85.680 280.716 85.704 280.800 ;
  END
 END x_q[290]
 PIN x_q[291]
  DIRECTION INPUT ;
  USE SIGNAL ;
  PORT
   LAYER M5 ;
   RECT 85.872 280.716 85.896 280.800 ;
  END
 END x_q[291]
 PIN x_q[292]
  DIRECTION INPUT ;
  USE SIGNAL ;
  PORT
   LAYER M5 ;
   RECT 86.064 280.716 86.088 280.800 ;
  END
 END x_q[292]
 PIN x_q[293]
  DIRECTION INPUT ;
  USE SIGNAL ;
  PORT
   LAYER M5 ;
   RECT 86.256 280.716 86.280 280.800 ;
  END
 END x_q[293]
 PIN x_q[294]
  DIRECTION INPUT ;
  USE SIGNAL ;
  PORT
   LAYER M5 ;
   RECT 86.448 280.716 86.472 280.800 ;
  END
 END x_q[294]
 PIN x_q[295]
  DIRECTION INPUT ;
  USE SIGNAL ;
  PORT
   LAYER M5 ;
   RECT 86.640 280.716 86.664 280.800 ;
  END
 END x_q[295]
 PIN x_q[296]
  DIRECTION INPUT ;
  USE SIGNAL ;
  PORT
   LAYER M5 ;
   RECT 86.832 280.716 86.856 280.800 ;
  END
 END x_q[296]
 PIN x_q[297]
  DIRECTION INPUT ;
  USE SIGNAL ;
  PORT
   LAYER M5 ;
   RECT 87.024 280.716 87.048 280.800 ;
  END
 END x_q[297]
 PIN x_q[298]
  DIRECTION INPUT ;
  USE SIGNAL ;
  PORT
   LAYER M5 ;
   RECT 87.216 280.716 87.240 280.800 ;
  END
 END x_q[298]
 PIN x_q[299]
  DIRECTION INPUT ;
  USE SIGNAL ;
  PORT
   LAYER M5 ;
   RECT 87.408 280.716 87.432 280.800 ;
  END
 END x_q[299]
 PIN x_q[300]
  DIRECTION INPUT ;
  USE SIGNAL ;
  PORT
   LAYER M5 ;
   RECT 87.600 280.716 87.624 280.800 ;
  END
 END x_q[300]
 PIN x_q[301]
  DIRECTION INPUT ;
  USE SIGNAL ;
  PORT
   LAYER M5 ;
   RECT 87.792 280.716 87.816 280.800 ;
  END
 END x_q[301]
 PIN x_q[302]
  DIRECTION INPUT ;
  USE SIGNAL ;
  PORT
   LAYER M5 ;
   RECT 87.984 280.716 88.008 280.800 ;
  END
 END x_q[302]
 PIN x_q[303]
  DIRECTION INPUT ;
  USE SIGNAL ;
  PORT
   LAYER M5 ;
   RECT 88.176 280.716 88.200 280.800 ;
  END
 END x_q[303]
 PIN x_q[304]
  DIRECTION INPUT ;
  USE SIGNAL ;
  PORT
   LAYER M5 ;
   RECT 88.368 280.716 88.392 280.800 ;
  END
 END x_q[304]
 PIN x_q[305]
  DIRECTION INPUT ;
  USE SIGNAL ;
  PORT
   LAYER M5 ;
   RECT 88.560 280.716 88.584 280.800 ;
  END
 END x_q[305]
 PIN x_q[306]
  DIRECTION INPUT ;
  USE SIGNAL ;
  PORT
   LAYER M5 ;
   RECT 88.752 280.716 88.776 280.800 ;
  END
 END x_q[306]
 PIN x_q[307]
  DIRECTION INPUT ;
  USE SIGNAL ;
  PORT
   LAYER M5 ;
   RECT 88.944 280.716 88.968 280.800 ;
  END
 END x_q[307]
 PIN x_q[308]
  DIRECTION INPUT ;
  USE SIGNAL ;
  PORT
   LAYER M5 ;
   RECT 89.136 280.716 89.160 280.800 ;
  END
 END x_q[308]
 PIN x_q[309]
  DIRECTION INPUT ;
  USE SIGNAL ;
  PORT
   LAYER M5 ;
   RECT 89.328 280.716 89.352 280.800 ;
  END
 END x_q[309]
 PIN x_q[310]
  DIRECTION INPUT ;
  USE SIGNAL ;
  PORT
   LAYER M5 ;
   RECT 89.520 280.716 89.544 280.800 ;
  END
 END x_q[310]
 PIN x_q[311]
  DIRECTION INPUT ;
  USE SIGNAL ;
  PORT
   LAYER M5 ;
   RECT 89.712 280.716 89.736 280.800 ;
  END
 END x_q[311]
 PIN x_q[312]
  DIRECTION INPUT ;
  USE SIGNAL ;
  PORT
   LAYER M5 ;
   RECT 89.904 280.716 89.928 280.800 ;
  END
 END x_q[312]
 PIN x_q[313]
  DIRECTION INPUT ;
  USE SIGNAL ;
  PORT
   LAYER M5 ;
   RECT 90.096 280.716 90.120 280.800 ;
  END
 END x_q[313]
 PIN x_q[314]
  DIRECTION INPUT ;
  USE SIGNAL ;
  PORT
   LAYER M5 ;
   RECT 90.288 280.716 90.312 280.800 ;
  END
 END x_q[314]
 PIN x_q[315]
  DIRECTION INPUT ;
  USE SIGNAL ;
  PORT
   LAYER M5 ;
   RECT 90.480 280.716 90.504 280.800 ;
  END
 END x_q[315]
 PIN x_q[316]
  DIRECTION INPUT ;
  USE SIGNAL ;
  PORT
   LAYER M5 ;
   RECT 90.672 280.716 90.696 280.800 ;
  END
 END x_q[316]
 PIN x_q[317]
  DIRECTION INPUT ;
  USE SIGNAL ;
  PORT
   LAYER M5 ;
   RECT 90.864 280.716 90.888 280.800 ;
  END
 END x_q[317]
 PIN x_q[318]
  DIRECTION INPUT ;
  USE SIGNAL ;
  PORT
   LAYER M5 ;
   RECT 91.056 280.716 91.080 280.800 ;
  END
 END x_q[318]
 PIN x_q[319]
  DIRECTION INPUT ;
  USE SIGNAL ;
  PORT
   LAYER M5 ;
   RECT 91.248 280.716 91.272 280.800 ;
  END
 END x_q[319]
 PIN x_q[320]
  DIRECTION INPUT ;
  USE SIGNAL ;
  PORT
   LAYER M5 ;
   RECT 91.440 280.716 91.464 280.800 ;
  END
 END x_q[320]
 PIN x_q[321]
  DIRECTION INPUT ;
  USE SIGNAL ;
  PORT
   LAYER M5 ;
   RECT 91.632 280.716 91.656 280.800 ;
  END
 END x_q[321]
 PIN x_q[322]
  DIRECTION INPUT ;
  USE SIGNAL ;
  PORT
   LAYER M5 ;
   RECT 91.824 280.716 91.848 280.800 ;
  END
 END x_q[322]
 PIN x_q[323]
  DIRECTION INPUT ;
  USE SIGNAL ;
  PORT
   LAYER M5 ;
   RECT 92.016 280.716 92.040 280.800 ;
  END
 END x_q[323]
 PIN x_q[324]
  DIRECTION INPUT ;
  USE SIGNAL ;
  PORT
   LAYER M5 ;
   RECT 92.208 280.716 92.232 280.800 ;
  END
 END x_q[324]
 PIN x_q[325]
  DIRECTION INPUT ;
  USE SIGNAL ;
  PORT
   LAYER M5 ;
   RECT 92.400 280.716 92.424 280.800 ;
  END
 END x_q[325]
 PIN x_q[326]
  DIRECTION INPUT ;
  USE SIGNAL ;
  PORT
   LAYER M5 ;
   RECT 92.592 280.716 92.616 280.800 ;
  END
 END x_q[326]
 PIN x_q[327]
  DIRECTION INPUT ;
  USE SIGNAL ;
  PORT
   LAYER M5 ;
   RECT 92.784 280.716 92.808 280.800 ;
  END
 END x_q[327]
 PIN x_q[328]
  DIRECTION INPUT ;
  USE SIGNAL ;
  PORT
   LAYER M5 ;
   RECT 92.976 280.716 93.000 280.800 ;
  END
 END x_q[328]
 PIN x_q[329]
  DIRECTION INPUT ;
  USE SIGNAL ;
  PORT
   LAYER M5 ;
   RECT 93.168 280.716 93.192 280.800 ;
  END
 END x_q[329]
 PIN x_q[330]
  DIRECTION INPUT ;
  USE SIGNAL ;
  PORT
   LAYER M5 ;
   RECT 93.360 280.716 93.384 280.800 ;
  END
 END x_q[330]
 PIN x_q[331]
  DIRECTION INPUT ;
  USE SIGNAL ;
  PORT
   LAYER M5 ;
   RECT 93.552 280.716 93.576 280.800 ;
  END
 END x_q[331]
 PIN x_q[332]
  DIRECTION INPUT ;
  USE SIGNAL ;
  PORT
   LAYER M5 ;
   RECT 93.744 280.716 93.768 280.800 ;
  END
 END x_q[332]
 PIN x_q[333]
  DIRECTION INPUT ;
  USE SIGNAL ;
  PORT
   LAYER M5 ;
   RECT 93.936 280.716 93.960 280.800 ;
  END
 END x_q[333]
 PIN x_q[334]
  DIRECTION INPUT ;
  USE SIGNAL ;
  PORT
   LAYER M5 ;
   RECT 94.128 280.716 94.152 280.800 ;
  END
 END x_q[334]
 PIN x_q[335]
  DIRECTION INPUT ;
  USE SIGNAL ;
  PORT
   LAYER M5 ;
   RECT 94.320 280.716 94.344 280.800 ;
  END
 END x_q[335]
 PIN x_q[336]
  DIRECTION INPUT ;
  USE SIGNAL ;
  PORT
   LAYER M5 ;
   RECT 94.512 280.716 94.536 280.800 ;
  END
 END x_q[336]
 PIN x_q[337]
  DIRECTION INPUT ;
  USE SIGNAL ;
  PORT
   LAYER M5 ;
   RECT 94.704 280.716 94.728 280.800 ;
  END
 END x_q[337]
 PIN x_q[338]
  DIRECTION INPUT ;
  USE SIGNAL ;
  PORT
   LAYER M5 ;
   RECT 94.896 280.716 94.920 280.800 ;
  END
 END x_q[338]
 PIN x_q[339]
  DIRECTION INPUT ;
  USE SIGNAL ;
  PORT
   LAYER M5 ;
   RECT 95.088 280.716 95.112 280.800 ;
  END
 END x_q[339]
 PIN x_q[340]
  DIRECTION INPUT ;
  USE SIGNAL ;
  PORT
   LAYER M5 ;
   RECT 95.280 280.716 95.304 280.800 ;
  END
 END x_q[340]
 PIN x_q[341]
  DIRECTION INPUT ;
  USE SIGNAL ;
  PORT
   LAYER M5 ;
   RECT 95.472 280.716 95.496 280.800 ;
  END
 END x_q[341]
 PIN x_q[342]
  DIRECTION INPUT ;
  USE SIGNAL ;
  PORT
   LAYER M5 ;
   RECT 95.664 280.716 95.688 280.800 ;
  END
 END x_q[342]
 PIN x_q[343]
  DIRECTION INPUT ;
  USE SIGNAL ;
  PORT
   LAYER M5 ;
   RECT 95.856 280.716 95.880 280.800 ;
  END
 END x_q[343]
 PIN x_q[344]
  DIRECTION INPUT ;
  USE SIGNAL ;
  PORT
   LAYER M5 ;
   RECT 96.048 280.716 96.072 280.800 ;
  END
 END x_q[344]
 PIN x_q[345]
  DIRECTION INPUT ;
  USE SIGNAL ;
  PORT
   LAYER M5 ;
   RECT 96.240 280.716 96.264 280.800 ;
  END
 END x_q[345]
 PIN x_q[346]
  DIRECTION INPUT ;
  USE SIGNAL ;
  PORT
   LAYER M5 ;
   RECT 96.432 280.716 96.456 280.800 ;
  END
 END x_q[346]
 PIN x_q[347]
  DIRECTION INPUT ;
  USE SIGNAL ;
  PORT
   LAYER M5 ;
   RECT 96.624 280.716 96.648 280.800 ;
  END
 END x_q[347]
 PIN x_q[348]
  DIRECTION INPUT ;
  USE SIGNAL ;
  PORT
   LAYER M5 ;
   RECT 96.816 280.716 96.840 280.800 ;
  END
 END x_q[348]
 PIN x_q[349]
  DIRECTION INPUT ;
  USE SIGNAL ;
  PORT
   LAYER M5 ;
   RECT 97.008 280.716 97.032 280.800 ;
  END
 END x_q[349]
 PIN x_q[350]
  DIRECTION INPUT ;
  USE SIGNAL ;
  PORT
   LAYER M5 ;
   RECT 97.200 280.716 97.224 280.800 ;
  END
 END x_q[350]
 PIN x_q[351]
  DIRECTION INPUT ;
  USE SIGNAL ;
  PORT
   LAYER M5 ;
   RECT 97.392 280.716 97.416 280.800 ;
  END
 END x_q[351]
 PIN x_q[352]
  DIRECTION INPUT ;
  USE SIGNAL ;
  PORT
   LAYER M5 ;
   RECT 97.584 280.716 97.608 280.800 ;
  END
 END x_q[352]
 PIN x_q[353]
  DIRECTION INPUT ;
  USE SIGNAL ;
  PORT
   LAYER M5 ;
   RECT 97.776 280.716 97.800 280.800 ;
  END
 END x_q[353]
 PIN x_q[354]
  DIRECTION INPUT ;
  USE SIGNAL ;
  PORT
   LAYER M5 ;
   RECT 97.968 280.716 97.992 280.800 ;
  END
 END x_q[354]
 PIN x_q[355]
  DIRECTION INPUT ;
  USE SIGNAL ;
  PORT
   LAYER M5 ;
   RECT 98.160 280.716 98.184 280.800 ;
  END
 END x_q[355]
 PIN x_q[356]
  DIRECTION INPUT ;
  USE SIGNAL ;
  PORT
   LAYER M5 ;
   RECT 98.352 280.716 98.376 280.800 ;
  END
 END x_q[356]
 PIN x_q[357]
  DIRECTION INPUT ;
  USE SIGNAL ;
  PORT
   LAYER M5 ;
   RECT 98.544 280.716 98.568 280.800 ;
  END
 END x_q[357]
 PIN x_q[358]
  DIRECTION INPUT ;
  USE SIGNAL ;
  PORT
   LAYER M5 ;
   RECT 98.736 280.716 98.760 280.800 ;
  END
 END x_q[358]
 PIN x_q[359]
  DIRECTION INPUT ;
  USE SIGNAL ;
  PORT
   LAYER M5 ;
   RECT 98.928 280.716 98.952 280.800 ;
  END
 END x_q[359]
 PIN x_q[360]
  DIRECTION INPUT ;
  USE SIGNAL ;
  PORT
   LAYER M5 ;
   RECT 99.120 280.716 99.144 280.800 ;
  END
 END x_q[360]
 PIN x_q[361]
  DIRECTION INPUT ;
  USE SIGNAL ;
  PORT
   LAYER M5 ;
   RECT 99.312 280.716 99.336 280.800 ;
  END
 END x_q[361]
 PIN x_q[362]
  DIRECTION INPUT ;
  USE SIGNAL ;
  PORT
   LAYER M5 ;
   RECT 99.504 280.716 99.528 280.800 ;
  END
 END x_q[362]
 PIN x_q[363]
  DIRECTION INPUT ;
  USE SIGNAL ;
  PORT
   LAYER M5 ;
   RECT 99.696 280.716 99.720 280.800 ;
  END
 END x_q[363]
 PIN x_q[364]
  DIRECTION INPUT ;
  USE SIGNAL ;
  PORT
   LAYER M5 ;
   RECT 99.888 280.716 99.912 280.800 ;
  END
 END x_q[364]
 PIN x_q[365]
  DIRECTION INPUT ;
  USE SIGNAL ;
  PORT
   LAYER M5 ;
   RECT 100.080 280.716 100.104 280.800 ;
  END
 END x_q[365]
 PIN x_q[366]
  DIRECTION INPUT ;
  USE SIGNAL ;
  PORT
   LAYER M5 ;
   RECT 100.272 280.716 100.296 280.800 ;
  END
 END x_q[366]
 PIN x_q[367]
  DIRECTION INPUT ;
  USE SIGNAL ;
  PORT
   LAYER M5 ;
   RECT 100.464 280.716 100.488 280.800 ;
  END
 END x_q[367]
 PIN x_q[368]
  DIRECTION INPUT ;
  USE SIGNAL ;
  PORT
   LAYER M5 ;
   RECT 100.656 280.716 100.680 280.800 ;
  END
 END x_q[368]
 PIN x_q[369]
  DIRECTION INPUT ;
  USE SIGNAL ;
  PORT
   LAYER M5 ;
   RECT 100.848 280.716 100.872 280.800 ;
  END
 END x_q[369]
 PIN x_q[370]
  DIRECTION INPUT ;
  USE SIGNAL ;
  PORT
   LAYER M5 ;
   RECT 101.040 280.716 101.064 280.800 ;
  END
 END x_q[370]
 PIN x_q[371]
  DIRECTION INPUT ;
  USE SIGNAL ;
  PORT
   LAYER M5 ;
   RECT 101.232 280.716 101.256 280.800 ;
  END
 END x_q[371]
 PIN x_q[372]
  DIRECTION INPUT ;
  USE SIGNAL ;
  PORT
   LAYER M5 ;
   RECT 101.424 280.716 101.448 280.800 ;
  END
 END x_q[372]
 PIN x_q[373]
  DIRECTION INPUT ;
  USE SIGNAL ;
  PORT
   LAYER M5 ;
   RECT 101.616 280.716 101.640 280.800 ;
  END
 END x_q[373]
 PIN x_q[374]
  DIRECTION INPUT ;
  USE SIGNAL ;
  PORT
   LAYER M5 ;
   RECT 101.808 280.716 101.832 280.800 ;
  END
 END x_q[374]
 PIN x_q[375]
  DIRECTION INPUT ;
  USE SIGNAL ;
  PORT
   LAYER M5 ;
   RECT 102.000 280.716 102.024 280.800 ;
  END
 END x_q[375]
 PIN x_q[376]
  DIRECTION INPUT ;
  USE SIGNAL ;
  PORT
   LAYER M5 ;
   RECT 102.192 280.716 102.216 280.800 ;
  END
 END x_q[376]
 PIN x_q[377]
  DIRECTION INPUT ;
  USE SIGNAL ;
  PORT
   LAYER M5 ;
   RECT 102.384 280.716 102.408 280.800 ;
  END
 END x_q[377]
 PIN x_q[378]
  DIRECTION INPUT ;
  USE SIGNAL ;
  PORT
   LAYER M5 ;
   RECT 102.576 280.716 102.600 280.800 ;
  END
 END x_q[378]
 PIN x_q[379]
  DIRECTION INPUT ;
  USE SIGNAL ;
  PORT
   LAYER M5 ;
   RECT 102.768 280.716 102.792 280.800 ;
  END
 END x_q[379]
 PIN x_q[380]
  DIRECTION INPUT ;
  USE SIGNAL ;
  PORT
   LAYER M5 ;
   RECT 102.960 280.716 102.984 280.800 ;
  END
 END x_q[380]
 PIN x_q[381]
  DIRECTION INPUT ;
  USE SIGNAL ;
  PORT
   LAYER M5 ;
   RECT 103.152 280.716 103.176 280.800 ;
  END
 END x_q[381]
 PIN x_q[382]
  DIRECTION INPUT ;
  USE SIGNAL ;
  PORT
   LAYER M5 ;
   RECT 103.344 280.716 103.368 280.800 ;
  END
 END x_q[382]
 PIN x_q[383]
  DIRECTION INPUT ;
  USE SIGNAL ;
  PORT
   LAYER M5 ;
   RECT 103.536 280.716 103.560 280.800 ;
  END
 END x_q[383]
 PIN x_q[384]
  DIRECTION INPUT ;
  USE SIGNAL ;
  PORT
   LAYER M5 ;
   RECT 103.728 280.716 103.752 280.800 ;
  END
 END x_q[384]
 PIN x_q[385]
  DIRECTION INPUT ;
  USE SIGNAL ;
  PORT
   LAYER M5 ;
   RECT 103.920 280.716 103.944 280.800 ;
  END
 END x_q[385]
 PIN x_q[386]
  DIRECTION INPUT ;
  USE SIGNAL ;
  PORT
   LAYER M5 ;
   RECT 104.112 280.716 104.136 280.800 ;
  END
 END x_q[386]
 PIN x_q[387]
  DIRECTION INPUT ;
  USE SIGNAL ;
  PORT
   LAYER M5 ;
   RECT 104.304 280.716 104.328 280.800 ;
  END
 END x_q[387]
 PIN x_q[388]
  DIRECTION INPUT ;
  USE SIGNAL ;
  PORT
   LAYER M5 ;
   RECT 104.496 280.716 104.520 280.800 ;
  END
 END x_q[388]
 PIN x_q[389]
  DIRECTION INPUT ;
  USE SIGNAL ;
  PORT
   LAYER M5 ;
   RECT 104.688 280.716 104.712 280.800 ;
  END
 END x_q[389]
 PIN x_q[390]
  DIRECTION INPUT ;
  USE SIGNAL ;
  PORT
   LAYER M5 ;
   RECT 104.880 280.716 104.904 280.800 ;
  END
 END x_q[390]
 PIN x_q[391]
  DIRECTION INPUT ;
  USE SIGNAL ;
  PORT
   LAYER M5 ;
   RECT 105.072 280.716 105.096 280.800 ;
  END
 END x_q[391]
 PIN x_q[392]
  DIRECTION INPUT ;
  USE SIGNAL ;
  PORT
   LAYER M5 ;
   RECT 105.264 280.716 105.288 280.800 ;
  END
 END x_q[392]
 PIN x_q[393]
  DIRECTION INPUT ;
  USE SIGNAL ;
  PORT
   LAYER M5 ;
   RECT 105.456 280.716 105.480 280.800 ;
  END
 END x_q[393]
 PIN x_q[394]
  DIRECTION INPUT ;
  USE SIGNAL ;
  PORT
   LAYER M5 ;
   RECT 105.648 280.716 105.672 280.800 ;
  END
 END x_q[394]
 PIN x_q[395]
  DIRECTION INPUT ;
  USE SIGNAL ;
  PORT
   LAYER M5 ;
   RECT 105.840 280.716 105.864 280.800 ;
  END
 END x_q[395]
 PIN x_q[396]
  DIRECTION INPUT ;
  USE SIGNAL ;
  PORT
   LAYER M5 ;
   RECT 106.032 280.716 106.056 280.800 ;
  END
 END x_q[396]
 PIN x_q[397]
  DIRECTION INPUT ;
  USE SIGNAL ;
  PORT
   LAYER M5 ;
   RECT 106.224 280.716 106.248 280.800 ;
  END
 END x_q[397]
 PIN x_q[398]
  DIRECTION INPUT ;
  USE SIGNAL ;
  PORT
   LAYER M5 ;
   RECT 106.416 280.716 106.440 280.800 ;
  END
 END x_q[398]
 PIN x_q[399]
  DIRECTION INPUT ;
  USE SIGNAL ;
  PORT
   LAYER M5 ;
   RECT 106.608 280.716 106.632 280.800 ;
  END
 END x_q[399]
 PIN x_q[400]
  DIRECTION INPUT ;
  USE SIGNAL ;
  PORT
   LAYER M5 ;
   RECT 106.800 280.716 106.824 280.800 ;
  END
 END x_q[400]
 PIN x_q[401]
  DIRECTION INPUT ;
  USE SIGNAL ;
  PORT
   LAYER M5 ;
   RECT 106.992 280.716 107.016 280.800 ;
  END
 END x_q[401]
 PIN x_q[402]
  DIRECTION INPUT ;
  USE SIGNAL ;
  PORT
   LAYER M5 ;
   RECT 107.184 280.716 107.208 280.800 ;
  END
 END x_q[402]
 PIN x_q[403]
  DIRECTION INPUT ;
  USE SIGNAL ;
  PORT
   LAYER M5 ;
   RECT 107.376 280.716 107.400 280.800 ;
  END
 END x_q[403]
 PIN x_q[404]
  DIRECTION INPUT ;
  USE SIGNAL ;
  PORT
   LAYER M5 ;
   RECT 107.568 280.716 107.592 280.800 ;
  END
 END x_q[404]
 PIN x_q[405]
  DIRECTION INPUT ;
  USE SIGNAL ;
  PORT
   LAYER M5 ;
   RECT 107.760 280.716 107.784 280.800 ;
  END
 END x_q[405]
 PIN x_q[406]
  DIRECTION INPUT ;
  USE SIGNAL ;
  PORT
   LAYER M5 ;
   RECT 107.952 280.716 107.976 280.800 ;
  END
 END x_q[406]
 PIN x_q[407]
  DIRECTION INPUT ;
  USE SIGNAL ;
  PORT
   LAYER M5 ;
   RECT 108.144 280.716 108.168 280.800 ;
  END
 END x_q[407]
 PIN x_q[408]
  DIRECTION INPUT ;
  USE SIGNAL ;
  PORT
   LAYER M5 ;
   RECT 108.336 280.716 108.360 280.800 ;
  END
 END x_q[408]
 PIN x_q[409]
  DIRECTION INPUT ;
  USE SIGNAL ;
  PORT
   LAYER M5 ;
   RECT 108.528 280.716 108.552 280.800 ;
  END
 END x_q[409]
 PIN x_q[410]
  DIRECTION INPUT ;
  USE SIGNAL ;
  PORT
   LAYER M5 ;
   RECT 108.720 280.716 108.744 280.800 ;
  END
 END x_q[410]
 PIN x_q[411]
  DIRECTION INPUT ;
  USE SIGNAL ;
  PORT
   LAYER M5 ;
   RECT 108.912 280.716 108.936 280.800 ;
  END
 END x_q[411]
 PIN x_q[412]
  DIRECTION INPUT ;
  USE SIGNAL ;
  PORT
   LAYER M5 ;
   RECT 109.104 280.716 109.128 280.800 ;
  END
 END x_q[412]
 PIN x_q[413]
  DIRECTION INPUT ;
  USE SIGNAL ;
  PORT
   LAYER M5 ;
   RECT 109.296 280.716 109.320 280.800 ;
  END
 END x_q[413]
 PIN x_q[414]
  DIRECTION INPUT ;
  USE SIGNAL ;
  PORT
   LAYER M5 ;
   RECT 109.488 280.716 109.512 280.800 ;
  END
 END x_q[414]
 PIN x_q[415]
  DIRECTION INPUT ;
  USE SIGNAL ;
  PORT
   LAYER M5 ;
   RECT 109.680 280.716 109.704 280.800 ;
  END
 END x_q[415]
 PIN x_q[416]
  DIRECTION INPUT ;
  USE SIGNAL ;
  PORT
   LAYER M5 ;
   RECT 109.872 280.716 109.896 280.800 ;
  END
 END x_q[416]
 PIN x_q[417]
  DIRECTION INPUT ;
  USE SIGNAL ;
  PORT
   LAYER M5 ;
   RECT 110.064 280.716 110.088 280.800 ;
  END
 END x_q[417]
 PIN x_q[418]
  DIRECTION INPUT ;
  USE SIGNAL ;
  PORT
   LAYER M5 ;
   RECT 110.256 280.716 110.280 280.800 ;
  END
 END x_q[418]
 PIN x_q[419]
  DIRECTION INPUT ;
  USE SIGNAL ;
  PORT
   LAYER M5 ;
   RECT 110.448 280.716 110.472 280.800 ;
  END
 END x_q[419]
 PIN x_q[420]
  DIRECTION INPUT ;
  USE SIGNAL ;
  PORT
   LAYER M5 ;
   RECT 110.640 280.716 110.664 280.800 ;
  END
 END x_q[420]
 PIN x_q[421]
  DIRECTION INPUT ;
  USE SIGNAL ;
  PORT
   LAYER M5 ;
   RECT 110.832 280.716 110.856 280.800 ;
  END
 END x_q[421]
 PIN x_q[422]
  DIRECTION INPUT ;
  USE SIGNAL ;
  PORT
   LAYER M5 ;
   RECT 111.024 280.716 111.048 280.800 ;
  END
 END x_q[422]
 PIN x_q[423]
  DIRECTION INPUT ;
  USE SIGNAL ;
  PORT
   LAYER M5 ;
   RECT 111.216 280.716 111.240 280.800 ;
  END
 END x_q[423]
 PIN x_q[424]
  DIRECTION INPUT ;
  USE SIGNAL ;
  PORT
   LAYER M5 ;
   RECT 111.408 280.716 111.432 280.800 ;
  END
 END x_q[424]
 PIN x_q[425]
  DIRECTION INPUT ;
  USE SIGNAL ;
  PORT
   LAYER M5 ;
   RECT 111.600 280.716 111.624 280.800 ;
  END
 END x_q[425]
 PIN x_q[426]
  DIRECTION INPUT ;
  USE SIGNAL ;
  PORT
   LAYER M5 ;
   RECT 111.792 280.716 111.816 280.800 ;
  END
 END x_q[426]
 PIN x_q[427]
  DIRECTION INPUT ;
  USE SIGNAL ;
  PORT
   LAYER M5 ;
   RECT 111.984 280.716 112.008 280.800 ;
  END
 END x_q[427]
 PIN x_q[428]
  DIRECTION INPUT ;
  USE SIGNAL ;
  PORT
   LAYER M5 ;
   RECT 112.176 280.716 112.200 280.800 ;
  END
 END x_q[428]
 PIN x_q[429]
  DIRECTION INPUT ;
  USE SIGNAL ;
  PORT
   LAYER M5 ;
   RECT 112.368 280.716 112.392 280.800 ;
  END
 END x_q[429]
 PIN x_q[430]
  DIRECTION INPUT ;
  USE SIGNAL ;
  PORT
   LAYER M5 ;
   RECT 112.560 280.716 112.584 280.800 ;
  END
 END x_q[430]
 PIN x_q[431]
  DIRECTION INPUT ;
  USE SIGNAL ;
  PORT
   LAYER M5 ;
   RECT 112.752 280.716 112.776 280.800 ;
  END
 END x_q[431]
 PIN x_q[432]
  DIRECTION INPUT ;
  USE SIGNAL ;
  PORT
   LAYER M5 ;
   RECT 112.944 280.716 112.968 280.800 ;
  END
 END x_q[432]
 PIN x_q[433]
  DIRECTION INPUT ;
  USE SIGNAL ;
  PORT
   LAYER M5 ;
   RECT 113.136 280.716 113.160 280.800 ;
  END
 END x_q[433]
 PIN x_q[434]
  DIRECTION INPUT ;
  USE SIGNAL ;
  PORT
   LAYER M5 ;
   RECT 113.328 280.716 113.352 280.800 ;
  END
 END x_q[434]
 PIN x_q[435]
  DIRECTION INPUT ;
  USE SIGNAL ;
  PORT
   LAYER M5 ;
   RECT 113.520 280.716 113.544 280.800 ;
  END
 END x_q[435]
 PIN x_q[436]
  DIRECTION INPUT ;
  USE SIGNAL ;
  PORT
   LAYER M5 ;
   RECT 113.712 280.716 113.736 280.800 ;
  END
 END x_q[436]
 PIN x_q[437]
  DIRECTION INPUT ;
  USE SIGNAL ;
  PORT
   LAYER M5 ;
   RECT 113.904 280.716 113.928 280.800 ;
  END
 END x_q[437]
 PIN x_q[438]
  DIRECTION INPUT ;
  USE SIGNAL ;
  PORT
   LAYER M5 ;
   RECT 114.096 280.716 114.120 280.800 ;
  END
 END x_q[438]
 PIN x_q[439]
  DIRECTION INPUT ;
  USE SIGNAL ;
  PORT
   LAYER M5 ;
   RECT 114.288 280.716 114.312 280.800 ;
  END
 END x_q[439]
 PIN x_q[440]
  DIRECTION INPUT ;
  USE SIGNAL ;
  PORT
   LAYER M5 ;
   RECT 114.480 280.716 114.504 280.800 ;
  END
 END x_q[440]
 PIN x_q[441]
  DIRECTION INPUT ;
  USE SIGNAL ;
  PORT
   LAYER M5 ;
   RECT 114.672 280.716 114.696 280.800 ;
  END
 END x_q[441]
 PIN x_q[442]
  DIRECTION INPUT ;
  USE SIGNAL ;
  PORT
   LAYER M5 ;
   RECT 114.864 280.716 114.888 280.800 ;
  END
 END x_q[442]
 PIN x_q[443]
  DIRECTION INPUT ;
  USE SIGNAL ;
  PORT
   LAYER M5 ;
   RECT 115.056 280.716 115.080 280.800 ;
  END
 END x_q[443]
 PIN x_q[444]
  DIRECTION INPUT ;
  USE SIGNAL ;
  PORT
   LAYER M5 ;
   RECT 115.248 280.716 115.272 280.800 ;
  END
 END x_q[444]
 PIN x_q[445]
  DIRECTION INPUT ;
  USE SIGNAL ;
  PORT
   LAYER M5 ;
   RECT 115.440 280.716 115.464 280.800 ;
  END
 END x_q[445]
 PIN x_q[446]
  DIRECTION INPUT ;
  USE SIGNAL ;
  PORT
   LAYER M5 ;
   RECT 115.632 280.716 115.656 280.800 ;
  END
 END x_q[446]
 PIN x_q[447]
  DIRECTION INPUT ;
  USE SIGNAL ;
  PORT
   LAYER M5 ;
   RECT 115.824 280.716 115.848 280.800 ;
  END
 END x_q[447]
 PIN x_q[448]
  DIRECTION INPUT ;
  USE SIGNAL ;
  PORT
   LAYER M5 ;
   RECT 116.016 280.716 116.040 280.800 ;
  END
 END x_q[448]
 PIN x_q[449]
  DIRECTION INPUT ;
  USE SIGNAL ;
  PORT
   LAYER M5 ;
   RECT 116.208 280.716 116.232 280.800 ;
  END
 END x_q[449]
 PIN x_q[450]
  DIRECTION INPUT ;
  USE SIGNAL ;
  PORT
   LAYER M5 ;
   RECT 116.400 280.716 116.424 280.800 ;
  END
 END x_q[450]
 PIN x_q[451]
  DIRECTION INPUT ;
  USE SIGNAL ;
  PORT
   LAYER M5 ;
   RECT 116.592 280.716 116.616 280.800 ;
  END
 END x_q[451]
 PIN x_q[452]
  DIRECTION INPUT ;
  USE SIGNAL ;
  PORT
   LAYER M5 ;
   RECT 116.784 280.716 116.808 280.800 ;
  END
 END x_q[452]
 PIN x_q[453]
  DIRECTION INPUT ;
  USE SIGNAL ;
  PORT
   LAYER M5 ;
   RECT 116.976 280.716 117.000 280.800 ;
  END
 END x_q[453]
 PIN x_q[454]
  DIRECTION INPUT ;
  USE SIGNAL ;
  PORT
   LAYER M5 ;
   RECT 117.168 280.716 117.192 280.800 ;
  END
 END x_q[454]
 PIN x_q[455]
  DIRECTION INPUT ;
  USE SIGNAL ;
  PORT
   LAYER M5 ;
   RECT 117.360 280.716 117.384 280.800 ;
  END
 END x_q[455]
 PIN x_q[456]
  DIRECTION INPUT ;
  USE SIGNAL ;
  PORT
   LAYER M5 ;
   RECT 117.552 280.716 117.576 280.800 ;
  END
 END x_q[456]
 PIN x_q[457]
  DIRECTION INPUT ;
  USE SIGNAL ;
  PORT
   LAYER M5 ;
   RECT 117.744 280.716 117.768 280.800 ;
  END
 END x_q[457]
 PIN x_q[458]
  DIRECTION INPUT ;
  USE SIGNAL ;
  PORT
   LAYER M5 ;
   RECT 117.936 280.716 117.960 280.800 ;
  END
 END x_q[458]
 PIN x_q[459]
  DIRECTION INPUT ;
  USE SIGNAL ;
  PORT
   LAYER M5 ;
   RECT 118.128 280.716 118.152 280.800 ;
  END
 END x_q[459]
 PIN x_q[460]
  DIRECTION INPUT ;
  USE SIGNAL ;
  PORT
   LAYER M5 ;
   RECT 118.320 280.716 118.344 280.800 ;
  END
 END x_q[460]
 PIN x_q[461]
  DIRECTION INPUT ;
  USE SIGNAL ;
  PORT
   LAYER M5 ;
   RECT 118.512 280.716 118.536 280.800 ;
  END
 END x_q[461]
 PIN x_q[462]
  DIRECTION INPUT ;
  USE SIGNAL ;
  PORT
   LAYER M5 ;
   RECT 118.704 280.716 118.728 280.800 ;
  END
 END x_q[462]
 PIN x_q[463]
  DIRECTION INPUT ;
  USE SIGNAL ;
  PORT
   LAYER M5 ;
   RECT 118.896 280.716 118.920 280.800 ;
  END
 END x_q[463]
 PIN x_q[464]
  DIRECTION INPUT ;
  USE SIGNAL ;
  PORT
   LAYER M5 ;
   RECT 119.088 280.716 119.112 280.800 ;
  END
 END x_q[464]
 PIN x_q[465]
  DIRECTION INPUT ;
  USE SIGNAL ;
  PORT
   LAYER M5 ;
   RECT 119.280 280.716 119.304 280.800 ;
  END
 END x_q[465]
 PIN x_q[466]
  DIRECTION INPUT ;
  USE SIGNAL ;
  PORT
   LAYER M5 ;
   RECT 119.472 280.716 119.496 280.800 ;
  END
 END x_q[466]
 PIN x_q[467]
  DIRECTION INPUT ;
  USE SIGNAL ;
  PORT
   LAYER M5 ;
   RECT 119.664 280.716 119.688 280.800 ;
  END
 END x_q[467]
 PIN x_q[468]
  DIRECTION INPUT ;
  USE SIGNAL ;
  PORT
   LAYER M5 ;
   RECT 119.856 280.716 119.880 280.800 ;
  END
 END x_q[468]
 PIN x_q[469]
  DIRECTION INPUT ;
  USE SIGNAL ;
  PORT
   LAYER M5 ;
   RECT 120.048 280.716 120.072 280.800 ;
  END
 END x_q[469]
 PIN x_q[470]
  DIRECTION INPUT ;
  USE SIGNAL ;
  PORT
   LAYER M5 ;
   RECT 120.240 280.716 120.264 280.800 ;
  END
 END x_q[470]
 PIN x_q[471]
  DIRECTION INPUT ;
  USE SIGNAL ;
  PORT
   LAYER M5 ;
   RECT 120.432 280.716 120.456 280.800 ;
  END
 END x_q[471]
 PIN x_q[472]
  DIRECTION INPUT ;
  USE SIGNAL ;
  PORT
   LAYER M5 ;
   RECT 120.624 280.716 120.648 280.800 ;
  END
 END x_q[472]
 PIN x_q[473]
  DIRECTION INPUT ;
  USE SIGNAL ;
  PORT
   LAYER M5 ;
   RECT 120.816 280.716 120.840 280.800 ;
  END
 END x_q[473]
 PIN x_q[474]
  DIRECTION INPUT ;
  USE SIGNAL ;
  PORT
   LAYER M5 ;
   RECT 121.008 280.716 121.032 280.800 ;
  END
 END x_q[474]
 PIN x_q[475]
  DIRECTION INPUT ;
  USE SIGNAL ;
  PORT
   LAYER M5 ;
   RECT 121.200 280.716 121.224 280.800 ;
  END
 END x_q[475]
 PIN x_q[476]
  DIRECTION INPUT ;
  USE SIGNAL ;
  PORT
   LAYER M5 ;
   RECT 121.392 280.716 121.416 280.800 ;
  END
 END x_q[476]
 PIN x_q[477]
  DIRECTION INPUT ;
  USE SIGNAL ;
  PORT
   LAYER M5 ;
   RECT 121.584 280.716 121.608 280.800 ;
  END
 END x_q[477]
 PIN x_q[478]
  DIRECTION INPUT ;
  USE SIGNAL ;
  PORT
   LAYER M5 ;
   RECT 121.776 280.716 121.800 280.800 ;
  END
 END x_q[478]
 PIN x_q[479]
  DIRECTION INPUT ;
  USE SIGNAL ;
  PORT
   LAYER M5 ;
   RECT 121.968 280.716 121.992 280.800 ;
  END
 END x_q[479]
 PIN x_q[480]
  DIRECTION INPUT ;
  USE SIGNAL ;
  PORT
   LAYER M5 ;
   RECT 122.160 280.716 122.184 280.800 ;
  END
 END x_q[480]
 PIN x_q[481]
  DIRECTION INPUT ;
  USE SIGNAL ;
  PORT
   LAYER M5 ;
   RECT 122.352 280.716 122.376 280.800 ;
  END
 END x_q[481]
 PIN x_q[482]
  DIRECTION INPUT ;
  USE SIGNAL ;
  PORT
   LAYER M5 ;
   RECT 122.544 280.716 122.568 280.800 ;
  END
 END x_q[482]
 PIN x_q[483]
  DIRECTION INPUT ;
  USE SIGNAL ;
  PORT
   LAYER M5 ;
   RECT 122.736 280.716 122.760 280.800 ;
  END
 END x_q[483]
 PIN x_q[484]
  DIRECTION INPUT ;
  USE SIGNAL ;
  PORT
   LAYER M5 ;
   RECT 122.928 280.716 122.952 280.800 ;
  END
 END x_q[484]
 PIN x_q[485]
  DIRECTION INPUT ;
  USE SIGNAL ;
  PORT
   LAYER M5 ;
   RECT 123.120 280.716 123.144 280.800 ;
  END
 END x_q[485]
 PIN x_q[486]
  DIRECTION INPUT ;
  USE SIGNAL ;
  PORT
   LAYER M5 ;
   RECT 123.312 280.716 123.336 280.800 ;
  END
 END x_q[486]
 PIN x_q[487]
  DIRECTION INPUT ;
  USE SIGNAL ;
  PORT
   LAYER M5 ;
   RECT 123.504 280.716 123.528 280.800 ;
  END
 END x_q[487]
 PIN x_q[488]
  DIRECTION INPUT ;
  USE SIGNAL ;
  PORT
   LAYER M5 ;
   RECT 123.696 280.716 123.720 280.800 ;
  END
 END x_q[488]
 PIN x_q[489]
  DIRECTION INPUT ;
  USE SIGNAL ;
  PORT
   LAYER M5 ;
   RECT 123.888 280.716 123.912 280.800 ;
  END
 END x_q[489]
 PIN x_q[490]
  DIRECTION INPUT ;
  USE SIGNAL ;
  PORT
   LAYER M5 ;
   RECT 124.080 280.716 124.104 280.800 ;
  END
 END x_q[490]
 PIN x_q[491]
  DIRECTION INPUT ;
  USE SIGNAL ;
  PORT
   LAYER M5 ;
   RECT 124.272 280.716 124.296 280.800 ;
  END
 END x_q[491]
 PIN x_q[492]
  DIRECTION INPUT ;
  USE SIGNAL ;
  PORT
   LAYER M5 ;
   RECT 124.464 280.716 124.488 280.800 ;
  END
 END x_q[492]
 PIN x_q[493]
  DIRECTION INPUT ;
  USE SIGNAL ;
  PORT
   LAYER M5 ;
   RECT 124.656 280.716 124.680 280.800 ;
  END
 END x_q[493]
 PIN x_q[494]
  DIRECTION INPUT ;
  USE SIGNAL ;
  PORT
   LAYER M5 ;
   RECT 124.848 280.716 124.872 280.800 ;
  END
 END x_q[494]
 PIN x_q[495]
  DIRECTION INPUT ;
  USE SIGNAL ;
  PORT
   LAYER M5 ;
   RECT 125.040 280.716 125.064 280.800 ;
  END
 END x_q[495]
 PIN x_q[496]
  DIRECTION INPUT ;
  USE SIGNAL ;
  PORT
   LAYER M5 ;
   RECT 125.232 280.716 125.256 280.800 ;
  END
 END x_q[496]
 PIN x_q[497]
  DIRECTION INPUT ;
  USE SIGNAL ;
  PORT
   LAYER M5 ;
   RECT 125.424 280.716 125.448 280.800 ;
  END
 END x_q[497]
 PIN x_q[498]
  DIRECTION INPUT ;
  USE SIGNAL ;
  PORT
   LAYER M5 ;
   RECT 125.616 280.716 125.640 280.800 ;
  END
 END x_q[498]
 PIN x_q[499]
  DIRECTION INPUT ;
  USE SIGNAL ;
  PORT
   LAYER M5 ;
   RECT 125.808 280.716 125.832 280.800 ;
  END
 END x_q[499]
 PIN x_q[500]
  DIRECTION INPUT ;
  USE SIGNAL ;
  PORT
   LAYER M5 ;
   RECT 126.000 280.716 126.024 280.800 ;
  END
 END x_q[500]
 PIN x_q[501]
  DIRECTION INPUT ;
  USE SIGNAL ;
  PORT
   LAYER M5 ;
   RECT 126.192 280.716 126.216 280.800 ;
  END
 END x_q[501]
 PIN x_q[502]
  DIRECTION INPUT ;
  USE SIGNAL ;
  PORT
   LAYER M5 ;
   RECT 126.384 280.716 126.408 280.800 ;
  END
 END x_q[502]
 PIN x_q[503]
  DIRECTION INPUT ;
  USE SIGNAL ;
  PORT
   LAYER M5 ;
   RECT 126.576 280.716 126.600 280.800 ;
  END
 END x_q[503]
 PIN x_q[504]
  DIRECTION INPUT ;
  USE SIGNAL ;
  PORT
   LAYER M5 ;
   RECT 126.768 280.716 126.792 280.800 ;
  END
 END x_q[504]
 PIN x_q[505]
  DIRECTION INPUT ;
  USE SIGNAL ;
  PORT
   LAYER M5 ;
   RECT 126.960 280.716 126.984 280.800 ;
  END
 END x_q[505]
 PIN x_q[506]
  DIRECTION INPUT ;
  USE SIGNAL ;
  PORT
   LAYER M5 ;
   RECT 127.152 280.716 127.176 280.800 ;
  END
 END x_q[506]
 PIN x_q[507]
  DIRECTION INPUT ;
  USE SIGNAL ;
  PORT
   LAYER M5 ;
   RECT 127.344 280.716 127.368 280.800 ;
  END
 END x_q[507]
 PIN x_q[508]
  DIRECTION INPUT ;
  USE SIGNAL ;
  PORT
   LAYER M5 ;
   RECT 127.536 280.716 127.560 280.800 ;
  END
 END x_q[508]
 PIN x_q[509]
  DIRECTION INPUT ;
  USE SIGNAL ;
  PORT
   LAYER M5 ;
   RECT 127.728 280.716 127.752 280.800 ;
  END
 END x_q[509]
 PIN x_q[510]
  DIRECTION INPUT ;
  USE SIGNAL ;
  PORT
   LAYER M5 ;
   RECT 127.920 280.716 127.944 280.800 ;
  END
 END x_q[510]
 PIN x_q[511]
  DIRECTION INPUT ;
  USE SIGNAL ;
  PORT
   LAYER M5 ;
   RECT 128.112 280.716 128.136 280.800 ;
  END
 END x_q[511]
 PIN x_q[512]
  DIRECTION INPUT ;
  USE SIGNAL ;
  PORT
   LAYER M5 ;
   RECT 128.304 280.716 128.328 280.800 ;
  END
 END x_q[512]
 PIN x_q[513]
  DIRECTION INPUT ;
  USE SIGNAL ;
  PORT
   LAYER M5 ;
   RECT 128.496 280.716 128.520 280.800 ;
  END
 END x_q[513]
 PIN x_q[514]
  DIRECTION INPUT ;
  USE SIGNAL ;
  PORT
   LAYER M5 ;
   RECT 128.688 280.716 128.712 280.800 ;
  END
 END x_q[514]
 PIN x_q[515]
  DIRECTION INPUT ;
  USE SIGNAL ;
  PORT
   LAYER M5 ;
   RECT 128.880 280.716 128.904 280.800 ;
  END
 END x_q[515]
 PIN x_q[516]
  DIRECTION INPUT ;
  USE SIGNAL ;
  PORT
   LAYER M5 ;
   RECT 129.072 280.716 129.096 280.800 ;
  END
 END x_q[516]
 PIN x_q[517]
  DIRECTION INPUT ;
  USE SIGNAL ;
  PORT
   LAYER M5 ;
   RECT 129.264 280.716 129.288 280.800 ;
  END
 END x_q[517]
 PIN x_q[518]
  DIRECTION INPUT ;
  USE SIGNAL ;
  PORT
   LAYER M5 ;
   RECT 129.456 280.716 129.480 280.800 ;
  END
 END x_q[518]
 PIN x_q[519]
  DIRECTION INPUT ;
  USE SIGNAL ;
  PORT
   LAYER M5 ;
   RECT 129.648 280.716 129.672 280.800 ;
  END
 END x_q[519]
 PIN x_q[520]
  DIRECTION INPUT ;
  USE SIGNAL ;
  PORT
   LAYER M5 ;
   RECT 129.840 280.716 129.864 280.800 ;
  END
 END x_q[520]
 PIN x_q[521]
  DIRECTION INPUT ;
  USE SIGNAL ;
  PORT
   LAYER M5 ;
   RECT 130.032 280.716 130.056 280.800 ;
  END
 END x_q[521]
 PIN x_q[522]
  DIRECTION INPUT ;
  USE SIGNAL ;
  PORT
   LAYER M5 ;
   RECT 130.224 280.716 130.248 280.800 ;
  END
 END x_q[522]
 PIN x_q[523]
  DIRECTION INPUT ;
  USE SIGNAL ;
  PORT
   LAYER M5 ;
   RECT 130.416 280.716 130.440 280.800 ;
  END
 END x_q[523]
 PIN x_q[524]
  DIRECTION INPUT ;
  USE SIGNAL ;
  PORT
   LAYER M5 ;
   RECT 130.608 280.716 130.632 280.800 ;
  END
 END x_q[524]
 PIN x_q[525]
  DIRECTION INPUT ;
  USE SIGNAL ;
  PORT
   LAYER M5 ;
   RECT 130.800 280.716 130.824 280.800 ;
  END
 END x_q[525]
 PIN x_q[526]
  DIRECTION INPUT ;
  USE SIGNAL ;
  PORT
   LAYER M5 ;
   RECT 130.992 280.716 131.016 280.800 ;
  END
 END x_q[526]
 PIN x_q[527]
  DIRECTION INPUT ;
  USE SIGNAL ;
  PORT
   LAYER M5 ;
   RECT 131.184 280.716 131.208 280.800 ;
  END
 END x_q[527]
 PIN x_q[528]
  DIRECTION INPUT ;
  USE SIGNAL ;
  PORT
   LAYER M5 ;
   RECT 131.376 280.716 131.400 280.800 ;
  END
 END x_q[528]
 PIN x_q[529]
  DIRECTION INPUT ;
  USE SIGNAL ;
  PORT
   LAYER M5 ;
   RECT 131.568 280.716 131.592 280.800 ;
  END
 END x_q[529]
 PIN x_q[530]
  DIRECTION INPUT ;
  USE SIGNAL ;
  PORT
   LAYER M5 ;
   RECT 131.760 280.716 131.784 280.800 ;
  END
 END x_q[530]
 PIN x_q[531]
  DIRECTION INPUT ;
  USE SIGNAL ;
  PORT
   LAYER M5 ;
   RECT 131.952 280.716 131.976 280.800 ;
  END
 END x_q[531]
 PIN x_q[532]
  DIRECTION INPUT ;
  USE SIGNAL ;
  PORT
   LAYER M5 ;
   RECT 132.144 280.716 132.168 280.800 ;
  END
 END x_q[532]
 PIN x_q[533]
  DIRECTION INPUT ;
  USE SIGNAL ;
  PORT
   LAYER M5 ;
   RECT 132.336 280.716 132.360 280.800 ;
  END
 END x_q[533]
 PIN x_q[534]
  DIRECTION INPUT ;
  USE SIGNAL ;
  PORT
   LAYER M5 ;
   RECT 132.528 280.716 132.552 280.800 ;
  END
 END x_q[534]
 PIN x_q[535]
  DIRECTION INPUT ;
  USE SIGNAL ;
  PORT
   LAYER M5 ;
   RECT 132.720 280.716 132.744 280.800 ;
  END
 END x_q[535]
 PIN x_q[536]
  DIRECTION INPUT ;
  USE SIGNAL ;
  PORT
   LAYER M5 ;
   RECT 132.912 280.716 132.936 280.800 ;
  END
 END x_q[536]
 PIN x_q[537]
  DIRECTION INPUT ;
  USE SIGNAL ;
  PORT
   LAYER M5 ;
   RECT 133.104 280.716 133.128 280.800 ;
  END
 END x_q[537]
 PIN x_q[538]
  DIRECTION INPUT ;
  USE SIGNAL ;
  PORT
   LAYER M5 ;
   RECT 133.296 280.716 133.320 280.800 ;
  END
 END x_q[538]
 PIN x_q[539]
  DIRECTION INPUT ;
  USE SIGNAL ;
  PORT
   LAYER M5 ;
   RECT 133.488 280.716 133.512 280.800 ;
  END
 END x_q[539]
 PIN x_q[540]
  DIRECTION INPUT ;
  USE SIGNAL ;
  PORT
   LAYER M5 ;
   RECT 133.680 280.716 133.704 280.800 ;
  END
 END x_q[540]
 PIN x_q[541]
  DIRECTION INPUT ;
  USE SIGNAL ;
  PORT
   LAYER M5 ;
   RECT 133.872 280.716 133.896 280.800 ;
  END
 END x_q[541]
 PIN x_q[542]
  DIRECTION INPUT ;
  USE SIGNAL ;
  PORT
   LAYER M5 ;
   RECT 134.064 280.716 134.088 280.800 ;
  END
 END x_q[542]
 PIN x_q[543]
  DIRECTION INPUT ;
  USE SIGNAL ;
  PORT
   LAYER M5 ;
   RECT 134.256 280.716 134.280 280.800 ;
  END
 END x_q[543]
 PIN k_v[0]
  DIRECTION INPUT ;
  USE SIGNAL ;
  PORT
   LAYER M5 ;
   RECT 240.000 280.716 240.024 280.800 ;
  END
 END k_v[0]
 PIN k_v[1]
  DIRECTION INPUT ;
  USE SIGNAL ;
  PORT
   LAYER M5 ;
   RECT 240.192 280.716 240.216 280.800 ;
  END
 END k_v[1]
 PIN k_v[2]
  DIRECTION INPUT ;
  USE SIGNAL ;
  PORT
   LAYER M5 ;
   RECT 240.384 280.716 240.408 280.800 ;
  END
 END k_v[2]
 PIN k_v[3]
  DIRECTION INPUT ;
  USE SIGNAL ;
  PORT
   LAYER M5 ;
   RECT 240.576 280.716 240.600 280.800 ;
  END
 END k_v[3]
 PIN k_lo[0]
  DIRECTION INPUT ;
  USE SIGNAL ;
  PORT
   LAYER M5 ;
   RECT 240.768 280.716 240.792 280.800 ;
  END
 END k_lo[0]
 PIN k_lo[1]
  DIRECTION INPUT ;
  USE SIGNAL ;
  PORT
   LAYER M5 ;
   RECT 240.960 280.716 240.984 280.800 ;
  END
 END k_lo[1]
 PIN k_lo[2]
  DIRECTION INPUT ;
  USE SIGNAL ;
  PORT
   LAYER M5 ;
   RECT 241.152 280.716 241.176 280.800 ;
  END
 END k_lo[2]
 PIN k_lo[3]
  DIRECTION INPUT ;
  USE SIGNAL ;
  PORT
   LAYER M5 ;
   RECT 241.344 280.716 241.368 280.800 ;
  END
 END k_lo[3]
 PIN k_lo[4]
  DIRECTION INPUT ;
  USE SIGNAL ;
  PORT
   LAYER M5 ;
   RECT 241.536 280.716 241.560 280.800 ;
  END
 END k_lo[4]
 PIN k_lo[5]
  DIRECTION INPUT ;
  USE SIGNAL ;
  PORT
   LAYER M5 ;
   RECT 241.728 280.716 241.752 280.800 ;
  END
 END k_lo[5]
 PIN k_lo[6]
  DIRECTION INPUT ;
  USE SIGNAL ;
  PORT
   LAYER M5 ;
   RECT 241.920 280.716 241.944 280.800 ;
  END
 END k_lo[6]
 PIN k_lo[7]
  DIRECTION INPUT ;
  USE SIGNAL ;
  PORT
   LAYER M5 ;
   RECT 242.112 280.716 242.136 280.800 ;
  END
 END k_lo[7]
 PIN k_lo[8]
  DIRECTION INPUT ;
  USE SIGNAL ;
  PORT
   LAYER M5 ;
   RECT 242.304 280.716 242.328 280.800 ;
  END
 END k_lo[8]
 PIN k_lo[9]
  DIRECTION INPUT ;
  USE SIGNAL ;
  PORT
   LAYER M5 ;
   RECT 242.496 280.716 242.520 280.800 ;
  END
 END k_lo[9]
 PIN k_lo[10]
  DIRECTION INPUT ;
  USE SIGNAL ;
  PORT
   LAYER M5 ;
   RECT 242.688 280.716 242.712 280.800 ;
  END
 END k_lo[10]
 PIN k_lo[11]
  DIRECTION INPUT ;
  USE SIGNAL ;
  PORT
   LAYER M5 ;
   RECT 242.880 280.716 242.904 280.800 ;
  END
 END k_lo[11]
 PIN k_lo[12]
  DIRECTION INPUT ;
  USE SIGNAL ;
  PORT
   LAYER M5 ;
   RECT 243.072 280.716 243.096 280.800 ;
  END
 END k_lo[12]
 PIN k_lo[13]
  DIRECTION INPUT ;
  USE SIGNAL ;
  PORT
   LAYER M5 ;
   RECT 243.264 280.716 243.288 280.800 ;
  END
 END k_lo[13]
 PIN k_lo[14]
  DIRECTION INPUT ;
  USE SIGNAL ;
  PORT
   LAYER M5 ;
   RECT 243.456 280.716 243.480 280.800 ;
  END
 END k_lo[14]
 PIN k_lo[15]
  DIRECTION INPUT ;
  USE SIGNAL ;
  PORT
   LAYER M5 ;
   RECT 243.648 280.716 243.672 280.800 ;
  END
 END k_lo[15]
 PIN k_lo[16]
  DIRECTION INPUT ;
  USE SIGNAL ;
  PORT
   LAYER M5 ;
   RECT 243.840 280.716 243.864 280.800 ;
  END
 END k_lo[16]
 PIN k_lo[17]
  DIRECTION INPUT ;
  USE SIGNAL ;
  PORT
   LAYER M5 ;
   RECT 244.032 280.716 244.056 280.800 ;
  END
 END k_lo[17]
 PIN k_lo[18]
  DIRECTION INPUT ;
  USE SIGNAL ;
  PORT
   LAYER M5 ;
   RECT 244.224 280.716 244.248 280.800 ;
  END
 END k_lo[18]
 PIN k_lo[19]
  DIRECTION INPUT ;
  USE SIGNAL ;
  PORT
   LAYER M5 ;
   RECT 244.416 280.716 244.440 280.800 ;
  END
 END k_lo[19]
 PIN k_lo[20]
  DIRECTION INPUT ;
  USE SIGNAL ;
  PORT
   LAYER M5 ;
   RECT 244.608 280.716 244.632 280.800 ;
  END
 END k_lo[20]
 PIN k_lo[21]
  DIRECTION INPUT ;
  USE SIGNAL ;
  PORT
   LAYER M5 ;
   RECT 244.800 280.716 244.824 280.800 ;
  END
 END k_lo[21]
 PIN k_lo[22]
  DIRECTION INPUT ;
  USE SIGNAL ;
  PORT
   LAYER M5 ;
   RECT 244.992 280.716 245.016 280.800 ;
  END
 END k_lo[22]
 PIN k_lo[23]
  DIRECTION INPUT ;
  USE SIGNAL ;
  PORT
   LAYER M5 ;
   RECT 245.184 280.716 245.208 280.800 ;
  END
 END k_lo[23]
 PIN k_lo[24]
  DIRECTION INPUT ;
  USE SIGNAL ;
  PORT
   LAYER M5 ;
   RECT 245.376 280.716 245.400 280.800 ;
  END
 END k_lo[24]
 PIN k_lo[25]
  DIRECTION INPUT ;
  USE SIGNAL ;
  PORT
   LAYER M5 ;
   RECT 245.568 280.716 245.592 280.800 ;
  END
 END k_lo[25]
 PIN k_lo[26]
  DIRECTION INPUT ;
  USE SIGNAL ;
  PORT
   LAYER M5 ;
   RECT 245.760 280.716 245.784 280.800 ;
  END
 END k_lo[26]
 PIN k_lo[27]
  DIRECTION INPUT ;
  USE SIGNAL ;
  PORT
   LAYER M5 ;
   RECT 245.952 280.716 245.976 280.800 ;
  END
 END k_lo[27]
 PIN k_lo[28]
  DIRECTION INPUT ;
  USE SIGNAL ;
  PORT
   LAYER M5 ;
   RECT 246.144 280.716 246.168 280.800 ;
  END
 END k_lo[28]
 PIN k_lo[29]
  DIRECTION INPUT ;
  USE SIGNAL ;
  PORT
   LAYER M5 ;
   RECT 246.336 280.716 246.360 280.800 ;
  END
 END k_lo[29]
 PIN k_lo[30]
  DIRECTION INPUT ;
  USE SIGNAL ;
  PORT
   LAYER M5 ;
   RECT 246.528 280.716 246.552 280.800 ;
  END
 END k_lo[30]
 PIN k_lo[31]
  DIRECTION INPUT ;
  USE SIGNAL ;
  PORT
   LAYER M5 ;
   RECT 246.720 280.716 246.744 280.800 ;
  END
 END k_lo[31]
 PIN k_lo[32]
  DIRECTION INPUT ;
  USE SIGNAL ;
  PORT
   LAYER M5 ;
   RECT 246.912 280.716 246.936 280.800 ;
  END
 END k_lo[32]
 PIN k_lo[33]
  DIRECTION INPUT ;
  USE SIGNAL ;
  PORT
   LAYER M5 ;
   RECT 247.104 280.716 247.128 280.800 ;
  END
 END k_lo[33]
 PIN k_lo[34]
  DIRECTION INPUT ;
  USE SIGNAL ;
  PORT
   LAYER M5 ;
   RECT 247.296 280.716 247.320 280.800 ;
  END
 END k_lo[34]
 PIN k_lo[35]
  DIRECTION INPUT ;
  USE SIGNAL ;
  PORT
   LAYER M5 ;
   RECT 247.488 280.716 247.512 280.800 ;
  END
 END k_lo[35]
 PIN k_lo[36]
  DIRECTION INPUT ;
  USE SIGNAL ;
  PORT
   LAYER M5 ;
   RECT 247.680 280.716 247.704 280.800 ;
  END
 END k_lo[36]
 PIN k_lo[37]
  DIRECTION INPUT ;
  USE SIGNAL ;
  PORT
   LAYER M5 ;
   RECT 247.872 280.716 247.896 280.800 ;
  END
 END k_lo[37]
 PIN k_lo[38]
  DIRECTION INPUT ;
  USE SIGNAL ;
  PORT
   LAYER M5 ;
   RECT 248.064 280.716 248.088 280.800 ;
  END
 END k_lo[38]
 PIN k_lo[39]
  DIRECTION INPUT ;
  USE SIGNAL ;
  PORT
   LAYER M5 ;
   RECT 248.256 280.716 248.280 280.800 ;
  END
 END k_lo[39]
 PIN k_lo[40]
  DIRECTION INPUT ;
  USE SIGNAL ;
  PORT
   LAYER M5 ;
   RECT 248.448 280.716 248.472 280.800 ;
  END
 END k_lo[40]
 PIN k_lo[41]
  DIRECTION INPUT ;
  USE SIGNAL ;
  PORT
   LAYER M5 ;
   RECT 248.640 280.716 248.664 280.800 ;
  END
 END k_lo[41]
 PIN k_lo[42]
  DIRECTION INPUT ;
  USE SIGNAL ;
  PORT
   LAYER M5 ;
   RECT 248.832 280.716 248.856 280.800 ;
  END
 END k_lo[42]
 PIN k_lo[43]
  DIRECTION INPUT ;
  USE SIGNAL ;
  PORT
   LAYER M5 ;
   RECT 249.024 280.716 249.048 280.800 ;
  END
 END k_lo[43]
 PIN k_lo[44]
  DIRECTION INPUT ;
  USE SIGNAL ;
  PORT
   LAYER M5 ;
   RECT 249.216 280.716 249.240 280.800 ;
  END
 END k_lo[44]
 PIN k_lo[45]
  DIRECTION INPUT ;
  USE SIGNAL ;
  PORT
   LAYER M5 ;
   RECT 249.408 280.716 249.432 280.800 ;
  END
 END k_lo[45]
 PIN k_lo[46]
  DIRECTION INPUT ;
  USE SIGNAL ;
  PORT
   LAYER M5 ;
   RECT 249.600 280.716 249.624 280.800 ;
  END
 END k_lo[46]
 PIN k_lo[47]
  DIRECTION INPUT ;
  USE SIGNAL ;
  PORT
   LAYER M5 ;
   RECT 249.792 280.716 249.816 280.800 ;
  END
 END k_lo[47]
 PIN k_lo[48]
  DIRECTION INPUT ;
  USE SIGNAL ;
  PORT
   LAYER M5 ;
   RECT 249.984 280.716 250.008 280.800 ;
  END
 END k_lo[48]
 PIN k_lo[49]
  DIRECTION INPUT ;
  USE SIGNAL ;
  PORT
   LAYER M5 ;
   RECT 250.176 280.716 250.200 280.800 ;
  END
 END k_lo[49]
 PIN k_lo[50]
  DIRECTION INPUT ;
  USE SIGNAL ;
  PORT
   LAYER M5 ;
   RECT 250.368 280.716 250.392 280.800 ;
  END
 END k_lo[50]
 PIN k_lo[51]
  DIRECTION INPUT ;
  USE SIGNAL ;
  PORT
   LAYER M5 ;
   RECT 250.560 280.716 250.584 280.800 ;
  END
 END k_lo[51]
 PIN k_lo[52]
  DIRECTION INPUT ;
  USE SIGNAL ;
  PORT
   LAYER M5 ;
   RECT 250.752 280.716 250.776 280.800 ;
  END
 END k_lo[52]
 PIN k_lo[53]
  DIRECTION INPUT ;
  USE SIGNAL ;
  PORT
   LAYER M5 ;
   RECT 250.944 280.716 250.968 280.800 ;
  END
 END k_lo[53]
 PIN k_lo[54]
  DIRECTION INPUT ;
  USE SIGNAL ;
  PORT
   LAYER M5 ;
   RECT 251.136 280.716 251.160 280.800 ;
  END
 END k_lo[54]
 PIN k_lo[55]
  DIRECTION INPUT ;
  USE SIGNAL ;
  PORT
   LAYER M5 ;
   RECT 251.328 280.716 251.352 280.800 ;
  END
 END k_lo[55]
 PIN k_lo[56]
  DIRECTION INPUT ;
  USE SIGNAL ;
  PORT
   LAYER M5 ;
   RECT 251.520 280.716 251.544 280.800 ;
  END
 END k_lo[56]
 PIN k_lo[57]
  DIRECTION INPUT ;
  USE SIGNAL ;
  PORT
   LAYER M5 ;
   RECT 251.712 280.716 251.736 280.800 ;
  END
 END k_lo[57]
 PIN k_lo[58]
  DIRECTION INPUT ;
  USE SIGNAL ;
  PORT
   LAYER M5 ;
   RECT 251.904 280.716 251.928 280.800 ;
  END
 END k_lo[58]
 PIN k_lo[59]
  DIRECTION INPUT ;
  USE SIGNAL ;
  PORT
   LAYER M5 ;
   RECT 252.096 280.716 252.120 280.800 ;
  END
 END k_lo[59]
 PIN k_lo[60]
  DIRECTION INPUT ;
  USE SIGNAL ;
  PORT
   LAYER M5 ;
   RECT 252.288 280.716 252.312 280.800 ;
  END
 END k_lo[60]
 PIN k_lo[61]
  DIRECTION INPUT ;
  USE SIGNAL ;
  PORT
   LAYER M5 ;
   RECT 252.480 280.716 252.504 280.800 ;
  END
 END k_lo[61]
 PIN k_lo[62]
  DIRECTION INPUT ;
  USE SIGNAL ;
  PORT
   LAYER M5 ;
   RECT 252.672 280.716 252.696 280.800 ;
  END
 END k_lo[62]
 PIN k_lo[63]
  DIRECTION INPUT ;
  USE SIGNAL ;
  PORT
   LAYER M5 ;
   RECT 252.864 280.716 252.888 280.800 ;
  END
 END k_lo[63]
 PIN k_lo[64]
  DIRECTION INPUT ;
  USE SIGNAL ;
  PORT
   LAYER M5 ;
   RECT 253.056 280.716 253.080 280.800 ;
  END
 END k_lo[64]
 PIN k_lo[65]
  DIRECTION INPUT ;
  USE SIGNAL ;
  PORT
   LAYER M5 ;
   RECT 253.248 280.716 253.272 280.800 ;
  END
 END k_lo[65]
 PIN k_lo[66]
  DIRECTION INPUT ;
  USE SIGNAL ;
  PORT
   LAYER M5 ;
   RECT 253.440 280.716 253.464 280.800 ;
  END
 END k_lo[66]
 PIN k_lo[67]
  DIRECTION INPUT ;
  USE SIGNAL ;
  PORT
   LAYER M5 ;
   RECT 253.632 280.716 253.656 280.800 ;
  END
 END k_lo[67]
 PIN k_lo[68]
  DIRECTION INPUT ;
  USE SIGNAL ;
  PORT
   LAYER M5 ;
   RECT 253.824 280.716 253.848 280.800 ;
  END
 END k_lo[68]
 PIN k_lo[69]
  DIRECTION INPUT ;
  USE SIGNAL ;
  PORT
   LAYER M5 ;
   RECT 254.016 280.716 254.040 280.800 ;
  END
 END k_lo[69]
 PIN k_lo[70]
  DIRECTION INPUT ;
  USE SIGNAL ;
  PORT
   LAYER M5 ;
   RECT 254.208 280.716 254.232 280.800 ;
  END
 END k_lo[70]
 PIN k_lo[71]
  DIRECTION INPUT ;
  USE SIGNAL ;
  PORT
   LAYER M5 ;
   RECT 254.400 280.716 254.424 280.800 ;
  END
 END k_lo[71]
 PIN k_lo[72]
  DIRECTION INPUT ;
  USE SIGNAL ;
  PORT
   LAYER M5 ;
   RECT 254.592 280.716 254.616 280.800 ;
  END
 END k_lo[72]
 PIN k_lo[73]
  DIRECTION INPUT ;
  USE SIGNAL ;
  PORT
   LAYER M5 ;
   RECT 254.784 280.716 254.808 280.800 ;
  END
 END k_lo[73]
 PIN k_lo[74]
  DIRECTION INPUT ;
  USE SIGNAL ;
  PORT
   LAYER M5 ;
   RECT 254.976 280.716 255.000 280.800 ;
  END
 END k_lo[74]
 PIN k_lo[75]
  DIRECTION INPUT ;
  USE SIGNAL ;
  PORT
   LAYER M5 ;
   RECT 255.168 280.716 255.192 280.800 ;
  END
 END k_lo[75]
 PIN k_lo[76]
  DIRECTION INPUT ;
  USE SIGNAL ;
  PORT
   LAYER M5 ;
   RECT 255.360 280.716 255.384 280.800 ;
  END
 END k_lo[76]
 PIN k_lo[77]
  DIRECTION INPUT ;
  USE SIGNAL ;
  PORT
   LAYER M5 ;
   RECT 255.552 280.716 255.576 280.800 ;
  END
 END k_lo[77]
 PIN k_lo[78]
  DIRECTION INPUT ;
  USE SIGNAL ;
  PORT
   LAYER M5 ;
   RECT 255.744 280.716 255.768 280.800 ;
  END
 END k_lo[78]
 PIN k_lo[79]
  DIRECTION INPUT ;
  USE SIGNAL ;
  PORT
   LAYER M5 ;
   RECT 255.936 280.716 255.960 280.800 ;
  END
 END k_lo[79]
 PIN k_lo[80]
  DIRECTION INPUT ;
  USE SIGNAL ;
  PORT
   LAYER M5 ;
   RECT 256.128 280.716 256.152 280.800 ;
  END
 END k_lo[80]
 PIN k_lo[81]
  DIRECTION INPUT ;
  USE SIGNAL ;
  PORT
   LAYER M5 ;
   RECT 256.320 280.716 256.344 280.800 ;
  END
 END k_lo[81]
 PIN k_lo[82]
  DIRECTION INPUT ;
  USE SIGNAL ;
  PORT
   LAYER M5 ;
   RECT 256.512 280.716 256.536 280.800 ;
  END
 END k_lo[82]
 PIN k_lo[83]
  DIRECTION INPUT ;
  USE SIGNAL ;
  PORT
   LAYER M5 ;
   RECT 256.704 280.716 256.728 280.800 ;
  END
 END k_lo[83]
 PIN k_lo[84]
  DIRECTION INPUT ;
  USE SIGNAL ;
  PORT
   LAYER M5 ;
   RECT 256.896 280.716 256.920 280.800 ;
  END
 END k_lo[84]
 PIN k_lo[85]
  DIRECTION INPUT ;
  USE SIGNAL ;
  PORT
   LAYER M5 ;
   RECT 257.088 280.716 257.112 280.800 ;
  END
 END k_lo[85]
 PIN k_lo[86]
  DIRECTION INPUT ;
  USE SIGNAL ;
  PORT
   LAYER M5 ;
   RECT 257.280 280.716 257.304 280.800 ;
  END
 END k_lo[86]
 PIN k_lo[87]
  DIRECTION INPUT ;
  USE SIGNAL ;
  PORT
   LAYER M5 ;
   RECT 257.472 280.716 257.496 280.800 ;
  END
 END k_lo[87]
 PIN k_lo[88]
  DIRECTION INPUT ;
  USE SIGNAL ;
  PORT
   LAYER M5 ;
   RECT 257.664 280.716 257.688 280.800 ;
  END
 END k_lo[88]
 PIN k_lo[89]
  DIRECTION INPUT ;
  USE SIGNAL ;
  PORT
   LAYER M5 ;
   RECT 257.856 280.716 257.880 280.800 ;
  END
 END k_lo[89]
 PIN k_lo[90]
  DIRECTION INPUT ;
  USE SIGNAL ;
  PORT
   LAYER M5 ;
   RECT 258.048 280.716 258.072 280.800 ;
  END
 END k_lo[90]
 PIN k_lo[91]
  DIRECTION INPUT ;
  USE SIGNAL ;
  PORT
   LAYER M5 ;
   RECT 258.240 280.716 258.264 280.800 ;
  END
 END k_lo[91]
 PIN k_lo[92]
  DIRECTION INPUT ;
  USE SIGNAL ;
  PORT
   LAYER M5 ;
   RECT 258.432 280.716 258.456 280.800 ;
  END
 END k_lo[92]
 PIN k_lo[93]
  DIRECTION INPUT ;
  USE SIGNAL ;
  PORT
   LAYER M5 ;
   RECT 258.624 280.716 258.648 280.800 ;
  END
 END k_lo[93]
 PIN k_lo[94]
  DIRECTION INPUT ;
  USE SIGNAL ;
  PORT
   LAYER M5 ;
   RECT 258.816 280.716 258.840 280.800 ;
  END
 END k_lo[94]
 PIN k_lo[95]
  DIRECTION INPUT ;
  USE SIGNAL ;
  PORT
   LAYER M5 ;
   RECT 259.008 280.716 259.032 280.800 ;
  END
 END k_lo[95]
 PIN k_lo[96]
  DIRECTION INPUT ;
  USE SIGNAL ;
  PORT
   LAYER M5 ;
   RECT 259.200 280.716 259.224 280.800 ;
  END
 END k_lo[96]
 PIN k_lo[97]
  DIRECTION INPUT ;
  USE SIGNAL ;
  PORT
   LAYER M5 ;
   RECT 259.392 280.716 259.416 280.800 ;
  END
 END k_lo[97]
 PIN k_lo[98]
  DIRECTION INPUT ;
  USE SIGNAL ;
  PORT
   LAYER M5 ;
   RECT 259.584 280.716 259.608 280.800 ;
  END
 END k_lo[98]
 PIN k_lo[99]
  DIRECTION INPUT ;
  USE SIGNAL ;
  PORT
   LAYER M5 ;
   RECT 259.776 280.716 259.800 280.800 ;
  END
 END k_lo[99]
 PIN k_lo[100]
  DIRECTION INPUT ;
  USE SIGNAL ;
  PORT
   LAYER M5 ;
   RECT 259.968 280.716 259.992 280.800 ;
  END
 END k_lo[100]
 PIN k_lo[101]
  DIRECTION INPUT ;
  USE SIGNAL ;
  PORT
   LAYER M5 ;
   RECT 260.160 280.716 260.184 280.800 ;
  END
 END k_lo[101]
 PIN k_lo[102]
  DIRECTION INPUT ;
  USE SIGNAL ;
  PORT
   LAYER M5 ;
   RECT 260.352 280.716 260.376 280.800 ;
  END
 END k_lo[102]
 PIN k_lo[103]
  DIRECTION INPUT ;
  USE SIGNAL ;
  PORT
   LAYER M5 ;
   RECT 260.544 280.716 260.568 280.800 ;
  END
 END k_lo[103]
 PIN k_lo[104]
  DIRECTION INPUT ;
  USE SIGNAL ;
  PORT
   LAYER M5 ;
   RECT 260.736 280.716 260.760 280.800 ;
  END
 END k_lo[104]
 PIN k_lo[105]
  DIRECTION INPUT ;
  USE SIGNAL ;
  PORT
   LAYER M5 ;
   RECT 260.928 280.716 260.952 280.800 ;
  END
 END k_lo[105]
 PIN k_lo[106]
  DIRECTION INPUT ;
  USE SIGNAL ;
  PORT
   LAYER M5 ;
   RECT 261.120 280.716 261.144 280.800 ;
  END
 END k_lo[106]
 PIN k_lo[107]
  DIRECTION INPUT ;
  USE SIGNAL ;
  PORT
   LAYER M5 ;
   RECT 261.312 280.716 261.336 280.800 ;
  END
 END k_lo[107]
 PIN k_lo[108]
  DIRECTION INPUT ;
  USE SIGNAL ;
  PORT
   LAYER M5 ;
   RECT 261.504 280.716 261.528 280.800 ;
  END
 END k_lo[108]
 PIN k_lo[109]
  DIRECTION INPUT ;
  USE SIGNAL ;
  PORT
   LAYER M5 ;
   RECT 261.696 280.716 261.720 280.800 ;
  END
 END k_lo[109]
 PIN k_lo[110]
  DIRECTION INPUT ;
  USE SIGNAL ;
  PORT
   LAYER M5 ;
   RECT 261.888 280.716 261.912 280.800 ;
  END
 END k_lo[110]
 PIN k_lo[111]
  DIRECTION INPUT ;
  USE SIGNAL ;
  PORT
   LAYER M5 ;
   RECT 262.080 280.716 262.104 280.800 ;
  END
 END k_lo[111]
 PIN k_lo[112]
  DIRECTION INPUT ;
  USE SIGNAL ;
  PORT
   LAYER M5 ;
   RECT 262.272 280.716 262.296 280.800 ;
  END
 END k_lo[112]
 PIN k_lo[113]
  DIRECTION INPUT ;
  USE SIGNAL ;
  PORT
   LAYER M5 ;
   RECT 262.464 280.716 262.488 280.800 ;
  END
 END k_lo[113]
 PIN k_lo[114]
  DIRECTION INPUT ;
  USE SIGNAL ;
  PORT
   LAYER M5 ;
   RECT 262.656 280.716 262.680 280.800 ;
  END
 END k_lo[114]
 PIN k_lo[115]
  DIRECTION INPUT ;
  USE SIGNAL ;
  PORT
   LAYER M5 ;
   RECT 262.848 280.716 262.872 280.800 ;
  END
 END k_lo[115]
 PIN k_lo[116]
  DIRECTION INPUT ;
  USE SIGNAL ;
  PORT
   LAYER M5 ;
   RECT 263.040 280.716 263.064 280.800 ;
  END
 END k_lo[116]
 PIN k_lo[117]
  DIRECTION INPUT ;
  USE SIGNAL ;
  PORT
   LAYER M5 ;
   RECT 263.232 280.716 263.256 280.800 ;
  END
 END k_lo[117]
 PIN k_lo[118]
  DIRECTION INPUT ;
  USE SIGNAL ;
  PORT
   LAYER M5 ;
   RECT 263.424 280.716 263.448 280.800 ;
  END
 END k_lo[118]
 PIN k_lo[119]
  DIRECTION INPUT ;
  USE SIGNAL ;
  PORT
   LAYER M5 ;
   RECT 263.616 280.716 263.640 280.800 ;
  END
 END k_lo[119]
 PIN k_lo[120]
  DIRECTION INPUT ;
  USE SIGNAL ;
  PORT
   LAYER M5 ;
   RECT 263.808 280.716 263.832 280.800 ;
  END
 END k_lo[120]
 PIN k_lo[121]
  DIRECTION INPUT ;
  USE SIGNAL ;
  PORT
   LAYER M5 ;
   RECT 264.000 280.716 264.024 280.800 ;
  END
 END k_lo[121]
 PIN k_lo[122]
  DIRECTION INPUT ;
  USE SIGNAL ;
  PORT
   LAYER M5 ;
   RECT 264.192 280.716 264.216 280.800 ;
  END
 END k_lo[122]
 PIN k_lo[123]
  DIRECTION INPUT ;
  USE SIGNAL ;
  PORT
   LAYER M5 ;
   RECT 264.384 280.716 264.408 280.800 ;
  END
 END k_lo[123]
 PIN k_lo[124]
  DIRECTION INPUT ;
  USE SIGNAL ;
  PORT
   LAYER M5 ;
   RECT 264.576 280.716 264.600 280.800 ;
  END
 END k_lo[124]
 PIN k_lo[125]
  DIRECTION INPUT ;
  USE SIGNAL ;
  PORT
   LAYER M5 ;
   RECT 264.768 280.716 264.792 280.800 ;
  END
 END k_lo[125]
 PIN k_lo[126]
  DIRECTION INPUT ;
  USE SIGNAL ;
  PORT
   LAYER M5 ;
   RECT 264.960 280.716 264.984 280.800 ;
  END
 END k_lo[126]
 PIN k_lo[127]
  DIRECTION INPUT ;
  USE SIGNAL ;
  PORT
   LAYER M5 ;
   RECT 265.152 280.716 265.176 280.800 ;
  END
 END k_lo[127]
 PIN k_lo[128]
  DIRECTION INPUT ;
  USE SIGNAL ;
  PORT
   LAYER M5 ;
   RECT 265.344 280.716 265.368 280.800 ;
  END
 END k_lo[128]
 PIN k_lo[129]
  DIRECTION INPUT ;
  USE SIGNAL ;
  PORT
   LAYER M5 ;
   RECT 265.536 280.716 265.560 280.800 ;
  END
 END k_lo[129]
 PIN k_lo[130]
  DIRECTION INPUT ;
  USE SIGNAL ;
  PORT
   LAYER M5 ;
   RECT 265.728 280.716 265.752 280.800 ;
  END
 END k_lo[130]
 PIN k_lo[131]
  DIRECTION INPUT ;
  USE SIGNAL ;
  PORT
   LAYER M5 ;
   RECT 265.920 280.716 265.944 280.800 ;
  END
 END k_lo[131]
 PIN k_lo[132]
  DIRECTION INPUT ;
  USE SIGNAL ;
  PORT
   LAYER M5 ;
   RECT 266.112 280.716 266.136 280.800 ;
  END
 END k_lo[132]
 PIN k_lo[133]
  DIRECTION INPUT ;
  USE SIGNAL ;
  PORT
   LAYER M5 ;
   RECT 266.304 280.716 266.328 280.800 ;
  END
 END k_lo[133]
 PIN k_lo[134]
  DIRECTION INPUT ;
  USE SIGNAL ;
  PORT
   LAYER M5 ;
   RECT 266.496 280.716 266.520 280.800 ;
  END
 END k_lo[134]
 PIN k_lo[135]
  DIRECTION INPUT ;
  USE SIGNAL ;
  PORT
   LAYER M5 ;
   RECT 266.688 280.716 266.712 280.800 ;
  END
 END k_lo[135]
 PIN k_lo[136]
  DIRECTION INPUT ;
  USE SIGNAL ;
  PORT
   LAYER M5 ;
   RECT 266.880 280.716 266.904 280.800 ;
  END
 END k_lo[136]
 PIN k_lo[137]
  DIRECTION INPUT ;
  USE SIGNAL ;
  PORT
   LAYER M5 ;
   RECT 267.072 280.716 267.096 280.800 ;
  END
 END k_lo[137]
 PIN k_lo[138]
  DIRECTION INPUT ;
  USE SIGNAL ;
  PORT
   LAYER M5 ;
   RECT 267.264 280.716 267.288 280.800 ;
  END
 END k_lo[138]
 PIN k_lo[139]
  DIRECTION INPUT ;
  USE SIGNAL ;
  PORT
   LAYER M5 ;
   RECT 267.456 280.716 267.480 280.800 ;
  END
 END k_lo[139]
 PIN k_lo[140]
  DIRECTION INPUT ;
  USE SIGNAL ;
  PORT
   LAYER M5 ;
   RECT 267.648 280.716 267.672 280.800 ;
  END
 END k_lo[140]
 PIN k_lo[141]
  DIRECTION INPUT ;
  USE SIGNAL ;
  PORT
   LAYER M5 ;
   RECT 267.840 280.716 267.864 280.800 ;
  END
 END k_lo[141]
 PIN k_lo[142]
  DIRECTION INPUT ;
  USE SIGNAL ;
  PORT
   LAYER M5 ;
   RECT 268.032 280.716 268.056 280.800 ;
  END
 END k_lo[142]
 PIN k_lo[143]
  DIRECTION INPUT ;
  USE SIGNAL ;
  PORT
   LAYER M5 ;
   RECT 268.224 280.716 268.248 280.800 ;
  END
 END k_lo[143]
 PIN k_lo[144]
  DIRECTION INPUT ;
  USE SIGNAL ;
  PORT
   LAYER M5 ;
   RECT 268.416 280.716 268.440 280.800 ;
  END
 END k_lo[144]
 PIN k_lo[145]
  DIRECTION INPUT ;
  USE SIGNAL ;
  PORT
   LAYER M5 ;
   RECT 268.608 280.716 268.632 280.800 ;
  END
 END k_lo[145]
 PIN k_lo[146]
  DIRECTION INPUT ;
  USE SIGNAL ;
  PORT
   LAYER M5 ;
   RECT 268.800 280.716 268.824 280.800 ;
  END
 END k_lo[146]
 PIN k_lo[147]
  DIRECTION INPUT ;
  USE SIGNAL ;
  PORT
   LAYER M5 ;
   RECT 268.992 280.716 269.016 280.800 ;
  END
 END k_lo[147]
 PIN k_lo[148]
  DIRECTION INPUT ;
  USE SIGNAL ;
  PORT
   LAYER M5 ;
   RECT 269.184 280.716 269.208 280.800 ;
  END
 END k_lo[148]
 PIN k_lo[149]
  DIRECTION INPUT ;
  USE SIGNAL ;
  PORT
   LAYER M5 ;
   RECT 269.376 280.716 269.400 280.800 ;
  END
 END k_lo[149]
 PIN k_lo[150]
  DIRECTION INPUT ;
  USE SIGNAL ;
  PORT
   LAYER M5 ;
   RECT 269.568 280.716 269.592 280.800 ;
  END
 END k_lo[150]
 PIN k_lo[151]
  DIRECTION INPUT ;
  USE SIGNAL ;
  PORT
   LAYER M5 ;
   RECT 269.760 280.716 269.784 280.800 ;
  END
 END k_lo[151]
 PIN k_lo[152]
  DIRECTION INPUT ;
  USE SIGNAL ;
  PORT
   LAYER M5 ;
   RECT 269.952 280.716 269.976 280.800 ;
  END
 END k_lo[152]
 PIN k_lo[153]
  DIRECTION INPUT ;
  USE SIGNAL ;
  PORT
   LAYER M5 ;
   RECT 270.144 280.716 270.168 280.800 ;
  END
 END k_lo[153]
 PIN k_lo[154]
  DIRECTION INPUT ;
  USE SIGNAL ;
  PORT
   LAYER M5 ;
   RECT 270.336 280.716 270.360 280.800 ;
  END
 END k_lo[154]
 PIN k_lo[155]
  DIRECTION INPUT ;
  USE SIGNAL ;
  PORT
   LAYER M5 ;
   RECT 270.528 280.716 270.552 280.800 ;
  END
 END k_lo[155]
 PIN k_lo[156]
  DIRECTION INPUT ;
  USE SIGNAL ;
  PORT
   LAYER M5 ;
   RECT 270.720 280.716 270.744 280.800 ;
  END
 END k_lo[156]
 PIN k_lo[157]
  DIRECTION INPUT ;
  USE SIGNAL ;
  PORT
   LAYER M5 ;
   RECT 270.912 280.716 270.936 280.800 ;
  END
 END k_lo[157]
 PIN k_lo[158]
  DIRECTION INPUT ;
  USE SIGNAL ;
  PORT
   LAYER M5 ;
   RECT 271.104 280.716 271.128 280.800 ;
  END
 END k_lo[158]
 PIN k_lo[159]
  DIRECTION INPUT ;
  USE SIGNAL ;
  PORT
   LAYER M5 ;
   RECT 271.296 280.716 271.320 280.800 ;
  END
 END k_lo[159]
 PIN k_lo[160]
  DIRECTION INPUT ;
  USE SIGNAL ;
  PORT
   LAYER M5 ;
   RECT 271.488 280.716 271.512 280.800 ;
  END
 END k_lo[160]
 PIN k_lo[161]
  DIRECTION INPUT ;
  USE SIGNAL ;
  PORT
   LAYER M5 ;
   RECT 271.680 280.716 271.704 280.800 ;
  END
 END k_lo[161]
 PIN k_lo[162]
  DIRECTION INPUT ;
  USE SIGNAL ;
  PORT
   LAYER M5 ;
   RECT 271.872 280.716 271.896 280.800 ;
  END
 END k_lo[162]
 PIN k_lo[163]
  DIRECTION INPUT ;
  USE SIGNAL ;
  PORT
   LAYER M5 ;
   RECT 272.064 280.716 272.088 280.800 ;
  END
 END k_lo[163]
 PIN k_lo[164]
  DIRECTION INPUT ;
  USE SIGNAL ;
  PORT
   LAYER M5 ;
   RECT 272.256 280.716 272.280 280.800 ;
  END
 END k_lo[164]
 PIN k_lo[165]
  DIRECTION INPUT ;
  USE SIGNAL ;
  PORT
   LAYER M5 ;
   RECT 272.448 280.716 272.472 280.800 ;
  END
 END k_lo[165]
 PIN k_lo[166]
  DIRECTION INPUT ;
  USE SIGNAL ;
  PORT
   LAYER M5 ;
   RECT 272.640 280.716 272.664 280.800 ;
  END
 END k_lo[166]
 PIN k_lo[167]
  DIRECTION INPUT ;
  USE SIGNAL ;
  PORT
   LAYER M5 ;
   RECT 272.832 280.716 272.856 280.800 ;
  END
 END k_lo[167]
 PIN k_lo[168]
  DIRECTION INPUT ;
  USE SIGNAL ;
  PORT
   LAYER M5 ;
   RECT 273.024 280.716 273.048 280.800 ;
  END
 END k_lo[168]
 PIN k_lo[169]
  DIRECTION INPUT ;
  USE SIGNAL ;
  PORT
   LAYER M5 ;
   RECT 273.216 280.716 273.240 280.800 ;
  END
 END k_lo[169]
 PIN k_lo[170]
  DIRECTION INPUT ;
  USE SIGNAL ;
  PORT
   LAYER M5 ;
   RECT 273.408 280.716 273.432 280.800 ;
  END
 END k_lo[170]
 PIN k_lo[171]
  DIRECTION INPUT ;
  USE SIGNAL ;
  PORT
   LAYER M5 ;
   RECT 273.600 280.716 273.624 280.800 ;
  END
 END k_lo[171]
 PIN k_lo[172]
  DIRECTION INPUT ;
  USE SIGNAL ;
  PORT
   LAYER M5 ;
   RECT 273.792 280.716 273.816 280.800 ;
  END
 END k_lo[172]
 PIN k_lo[173]
  DIRECTION INPUT ;
  USE SIGNAL ;
  PORT
   LAYER M5 ;
   RECT 273.984 280.716 274.008 280.800 ;
  END
 END k_lo[173]
 PIN k_lo[174]
  DIRECTION INPUT ;
  USE SIGNAL ;
  PORT
   LAYER M5 ;
   RECT 274.176 280.716 274.200 280.800 ;
  END
 END k_lo[174]
 PIN k_lo[175]
  DIRECTION INPUT ;
  USE SIGNAL ;
  PORT
   LAYER M5 ;
   RECT 274.368 280.716 274.392 280.800 ;
  END
 END k_lo[175]
 PIN k_lo[176]
  DIRECTION INPUT ;
  USE SIGNAL ;
  PORT
   LAYER M5 ;
   RECT 274.560 280.716 274.584 280.800 ;
  END
 END k_lo[176]
 PIN k_lo[177]
  DIRECTION INPUT ;
  USE SIGNAL ;
  PORT
   LAYER M5 ;
   RECT 274.752 280.716 274.776 280.800 ;
  END
 END k_lo[177]
 PIN k_lo[178]
  DIRECTION INPUT ;
  USE SIGNAL ;
  PORT
   LAYER M5 ;
   RECT 274.944 280.716 274.968 280.800 ;
  END
 END k_lo[178]
 PIN k_lo[179]
  DIRECTION INPUT ;
  USE SIGNAL ;
  PORT
   LAYER M5 ;
   RECT 275.136 280.716 275.160 280.800 ;
  END
 END k_lo[179]
 PIN k_lo[180]
  DIRECTION INPUT ;
  USE SIGNAL ;
  PORT
   LAYER M5 ;
   RECT 275.328 280.716 275.352 280.800 ;
  END
 END k_lo[180]
 PIN k_lo[181]
  DIRECTION INPUT ;
  USE SIGNAL ;
  PORT
   LAYER M5 ;
   RECT 275.520 280.716 275.544 280.800 ;
  END
 END k_lo[181]
 PIN k_lo[182]
  DIRECTION INPUT ;
  USE SIGNAL ;
  PORT
   LAYER M5 ;
   RECT 275.712 280.716 275.736 280.800 ;
  END
 END k_lo[182]
 PIN k_lo[183]
  DIRECTION INPUT ;
  USE SIGNAL ;
  PORT
   LAYER M5 ;
   RECT 275.904 280.716 275.928 280.800 ;
  END
 END k_lo[183]
 PIN k_lo[184]
  DIRECTION INPUT ;
  USE SIGNAL ;
  PORT
   LAYER M5 ;
   RECT 276.096 280.716 276.120 280.800 ;
  END
 END k_lo[184]
 PIN k_lo[185]
  DIRECTION INPUT ;
  USE SIGNAL ;
  PORT
   LAYER M5 ;
   RECT 276.288 280.716 276.312 280.800 ;
  END
 END k_lo[185]
 PIN k_lo[186]
  DIRECTION INPUT ;
  USE SIGNAL ;
  PORT
   LAYER M5 ;
   RECT 276.480 280.716 276.504 280.800 ;
  END
 END k_lo[186]
 PIN k_lo[187]
  DIRECTION INPUT ;
  USE SIGNAL ;
  PORT
   LAYER M5 ;
   RECT 276.672 280.716 276.696 280.800 ;
  END
 END k_lo[187]
 PIN k_lo[188]
  DIRECTION INPUT ;
  USE SIGNAL ;
  PORT
   LAYER M5 ;
   RECT 276.864 280.716 276.888 280.800 ;
  END
 END k_lo[188]
 PIN k_lo[189]
  DIRECTION INPUT ;
  USE SIGNAL ;
  PORT
   LAYER M5 ;
   RECT 277.056 280.716 277.080 280.800 ;
  END
 END k_lo[189]
 PIN k_lo[190]
  DIRECTION INPUT ;
  USE SIGNAL ;
  PORT
   LAYER M5 ;
   RECT 277.248 280.716 277.272 280.800 ;
  END
 END k_lo[190]
 PIN k_lo[191]
  DIRECTION INPUT ;
  USE SIGNAL ;
  PORT
   LAYER M5 ;
   RECT 277.440 280.716 277.464 280.800 ;
  END
 END k_lo[191]
 PIN k_lo[192]
  DIRECTION INPUT ;
  USE SIGNAL ;
  PORT
   LAYER M5 ;
   RECT 277.632 280.716 277.656 280.800 ;
  END
 END k_lo[192]
 PIN k_lo[193]
  DIRECTION INPUT ;
  USE SIGNAL ;
  PORT
   LAYER M5 ;
   RECT 277.824 280.716 277.848 280.800 ;
  END
 END k_lo[193]
 PIN k_lo[194]
  DIRECTION INPUT ;
  USE SIGNAL ;
  PORT
   LAYER M5 ;
   RECT 278.016 280.716 278.040 280.800 ;
  END
 END k_lo[194]
 PIN k_lo[195]
  DIRECTION INPUT ;
  USE SIGNAL ;
  PORT
   LAYER M5 ;
   RECT 278.208 280.716 278.232 280.800 ;
  END
 END k_lo[195]
 PIN k_lo[196]
  DIRECTION INPUT ;
  USE SIGNAL ;
  PORT
   LAYER M5 ;
   RECT 278.400 280.716 278.424 280.800 ;
  END
 END k_lo[196]
 PIN k_lo[197]
  DIRECTION INPUT ;
  USE SIGNAL ;
  PORT
   LAYER M5 ;
   RECT 278.592 280.716 278.616 280.800 ;
  END
 END k_lo[197]
 PIN k_lo[198]
  DIRECTION INPUT ;
  USE SIGNAL ;
  PORT
   LAYER M5 ;
   RECT 278.784 280.716 278.808 280.800 ;
  END
 END k_lo[198]
 PIN k_lo[199]
  DIRECTION INPUT ;
  USE SIGNAL ;
  PORT
   LAYER M5 ;
   RECT 278.976 280.716 279.000 280.800 ;
  END
 END k_lo[199]
 PIN k_lo[200]
  DIRECTION INPUT ;
  USE SIGNAL ;
  PORT
   LAYER M5 ;
   RECT 279.168 280.716 279.192 280.800 ;
  END
 END k_lo[200]
 PIN k_lo[201]
  DIRECTION INPUT ;
  USE SIGNAL ;
  PORT
   LAYER M5 ;
   RECT 279.360 280.716 279.384 280.800 ;
  END
 END k_lo[201]
 PIN k_lo[202]
  DIRECTION INPUT ;
  USE SIGNAL ;
  PORT
   LAYER M5 ;
   RECT 279.552 280.716 279.576 280.800 ;
  END
 END k_lo[202]
 PIN k_lo[203]
  DIRECTION INPUT ;
  USE SIGNAL ;
  PORT
   LAYER M5 ;
   RECT 279.744 280.716 279.768 280.800 ;
  END
 END k_lo[203]
 PIN k_lo[204]
  DIRECTION INPUT ;
  USE SIGNAL ;
  PORT
   LAYER M5 ;
   RECT 279.936 280.716 279.960 280.800 ;
  END
 END k_lo[204]
 PIN k_lo[205]
  DIRECTION INPUT ;
  USE SIGNAL ;
  PORT
   LAYER M5 ;
   RECT 280.128 280.716 280.152 280.800 ;
  END
 END k_lo[205]
 PIN k_lo[206]
  DIRECTION INPUT ;
  USE SIGNAL ;
  PORT
   LAYER M5 ;
   RECT 280.320 280.716 280.344 280.800 ;
  END
 END k_lo[206]
 PIN k_lo[207]
  DIRECTION INPUT ;
  USE SIGNAL ;
  PORT
   LAYER M5 ;
   RECT 280.512 280.716 280.536 280.800 ;
  END
 END k_lo[207]
 PIN k_lo[208]
  DIRECTION INPUT ;
  USE SIGNAL ;
  PORT
   LAYER M5 ;
   RECT 280.704 280.716 280.728 280.800 ;
  END
 END k_lo[208]
 PIN k_lo[209]
  DIRECTION INPUT ;
  USE SIGNAL ;
  PORT
   LAYER M5 ;
   RECT 280.896 280.716 280.920 280.800 ;
  END
 END k_lo[209]
 PIN k_lo[210]
  DIRECTION INPUT ;
  USE SIGNAL ;
  PORT
   LAYER M5 ;
   RECT 281.088 280.716 281.112 280.800 ;
  END
 END k_lo[210]
 PIN k_lo[211]
  DIRECTION INPUT ;
  USE SIGNAL ;
  PORT
   LAYER M5 ;
   RECT 281.280 280.716 281.304 280.800 ;
  END
 END k_lo[211]
 PIN k_lo[212]
  DIRECTION INPUT ;
  USE SIGNAL ;
  PORT
   LAYER M5 ;
   RECT 281.472 280.716 281.496 280.800 ;
  END
 END k_lo[212]
 PIN k_lo[213]
  DIRECTION INPUT ;
  USE SIGNAL ;
  PORT
   LAYER M5 ;
   RECT 281.664 280.716 281.688 280.800 ;
  END
 END k_lo[213]
 PIN k_lo[214]
  DIRECTION INPUT ;
  USE SIGNAL ;
  PORT
   LAYER M5 ;
   RECT 281.856 280.716 281.880 280.800 ;
  END
 END k_lo[214]
 PIN k_lo[215]
  DIRECTION INPUT ;
  USE SIGNAL ;
  PORT
   LAYER M5 ;
   RECT 282.048 280.716 282.072 280.800 ;
  END
 END k_lo[215]
 PIN k_lo[216]
  DIRECTION INPUT ;
  USE SIGNAL ;
  PORT
   LAYER M5 ;
   RECT 282.240 280.716 282.264 280.800 ;
  END
 END k_lo[216]
 PIN k_lo[217]
  DIRECTION INPUT ;
  USE SIGNAL ;
  PORT
   LAYER M5 ;
   RECT 282.432 280.716 282.456 280.800 ;
  END
 END k_lo[217]
 PIN k_lo[218]
  DIRECTION INPUT ;
  USE SIGNAL ;
  PORT
   LAYER M5 ;
   RECT 282.624 280.716 282.648 280.800 ;
  END
 END k_lo[218]
 PIN k_lo[219]
  DIRECTION INPUT ;
  USE SIGNAL ;
  PORT
   LAYER M5 ;
   RECT 282.816 280.716 282.840 280.800 ;
  END
 END k_lo[219]
 PIN k_lo[220]
  DIRECTION INPUT ;
  USE SIGNAL ;
  PORT
   LAYER M5 ;
   RECT 283.008 280.716 283.032 280.800 ;
  END
 END k_lo[220]
 PIN k_lo[221]
  DIRECTION INPUT ;
  USE SIGNAL ;
  PORT
   LAYER M5 ;
   RECT 283.200 280.716 283.224 280.800 ;
  END
 END k_lo[221]
 PIN k_lo[222]
  DIRECTION INPUT ;
  USE SIGNAL ;
  PORT
   LAYER M5 ;
   RECT 283.392 280.716 283.416 280.800 ;
  END
 END k_lo[222]
 PIN k_lo[223]
  DIRECTION INPUT ;
  USE SIGNAL ;
  PORT
   LAYER M5 ;
   RECT 283.584 280.716 283.608 280.800 ;
  END
 END k_lo[223]
 PIN k_lo[224]
  DIRECTION INPUT ;
  USE SIGNAL ;
  PORT
   LAYER M5 ;
   RECT 283.776 280.716 283.800 280.800 ;
  END
 END k_lo[224]
 PIN k_lo[225]
  DIRECTION INPUT ;
  USE SIGNAL ;
  PORT
   LAYER M5 ;
   RECT 283.968 280.716 283.992 280.800 ;
  END
 END k_lo[225]
 PIN k_lo[226]
  DIRECTION INPUT ;
  USE SIGNAL ;
  PORT
   LAYER M5 ;
   RECT 284.160 280.716 284.184 280.800 ;
  END
 END k_lo[226]
 PIN k_lo[227]
  DIRECTION INPUT ;
  USE SIGNAL ;
  PORT
   LAYER M5 ;
   RECT 284.352 280.716 284.376 280.800 ;
  END
 END k_lo[227]
 PIN k_lo[228]
  DIRECTION INPUT ;
  USE SIGNAL ;
  PORT
   LAYER M5 ;
   RECT 284.544 280.716 284.568 280.800 ;
  END
 END k_lo[228]
 PIN k_lo[229]
  DIRECTION INPUT ;
  USE SIGNAL ;
  PORT
   LAYER M5 ;
   RECT 284.736 280.716 284.760 280.800 ;
  END
 END k_lo[229]
 PIN k_lo[230]
  DIRECTION INPUT ;
  USE SIGNAL ;
  PORT
   LAYER M5 ;
   RECT 284.928 280.716 284.952 280.800 ;
  END
 END k_lo[230]
 PIN k_lo[231]
  DIRECTION INPUT ;
  USE SIGNAL ;
  PORT
   LAYER M5 ;
   RECT 285.120 280.716 285.144 280.800 ;
  END
 END k_lo[231]
 PIN k_lo[232]
  DIRECTION INPUT ;
  USE SIGNAL ;
  PORT
   LAYER M5 ;
   RECT 285.312 280.716 285.336 280.800 ;
  END
 END k_lo[232]
 PIN k_lo[233]
  DIRECTION INPUT ;
  USE SIGNAL ;
  PORT
   LAYER M5 ;
   RECT 285.504 280.716 285.528 280.800 ;
  END
 END k_lo[233]
 PIN k_lo[234]
  DIRECTION INPUT ;
  USE SIGNAL ;
  PORT
   LAYER M5 ;
   RECT 285.696 280.716 285.720 280.800 ;
  END
 END k_lo[234]
 PIN k_lo[235]
  DIRECTION INPUT ;
  USE SIGNAL ;
  PORT
   LAYER M5 ;
   RECT 285.888 280.716 285.912 280.800 ;
  END
 END k_lo[235]
 PIN k_lo[236]
  DIRECTION INPUT ;
  USE SIGNAL ;
  PORT
   LAYER M5 ;
   RECT 286.080 280.716 286.104 280.800 ;
  END
 END k_lo[236]
 PIN k_lo[237]
  DIRECTION INPUT ;
  USE SIGNAL ;
  PORT
   LAYER M5 ;
   RECT 286.272 280.716 286.296 280.800 ;
  END
 END k_lo[237]
 PIN k_lo[238]
  DIRECTION INPUT ;
  USE SIGNAL ;
  PORT
   LAYER M5 ;
   RECT 286.464 280.716 286.488 280.800 ;
  END
 END k_lo[238]
 PIN k_lo[239]
  DIRECTION INPUT ;
  USE SIGNAL ;
  PORT
   LAYER M5 ;
   RECT 286.656 280.716 286.680 280.800 ;
  END
 END k_lo[239]
 PIN k_lo[240]
  DIRECTION INPUT ;
  USE SIGNAL ;
  PORT
   LAYER M5 ;
   RECT 286.848 280.716 286.872 280.800 ;
  END
 END k_lo[240]
 PIN k_lo[241]
  DIRECTION INPUT ;
  USE SIGNAL ;
  PORT
   LAYER M5 ;
   RECT 287.040 280.716 287.064 280.800 ;
  END
 END k_lo[241]
 PIN k_lo[242]
  DIRECTION INPUT ;
  USE SIGNAL ;
  PORT
   LAYER M5 ;
   RECT 287.232 280.716 287.256 280.800 ;
  END
 END k_lo[242]
 PIN k_lo[243]
  DIRECTION INPUT ;
  USE SIGNAL ;
  PORT
   LAYER M5 ;
   RECT 287.424 280.716 287.448 280.800 ;
  END
 END k_lo[243]
 PIN k_lo[244]
  DIRECTION INPUT ;
  USE SIGNAL ;
  PORT
   LAYER M5 ;
   RECT 287.616 280.716 287.640 280.800 ;
  END
 END k_lo[244]
 PIN k_lo[245]
  DIRECTION INPUT ;
  USE SIGNAL ;
  PORT
   LAYER M5 ;
   RECT 287.808 280.716 287.832 280.800 ;
  END
 END k_lo[245]
 PIN k_lo[246]
  DIRECTION INPUT ;
  USE SIGNAL ;
  PORT
   LAYER M5 ;
   RECT 288.000 280.716 288.024 280.800 ;
  END
 END k_lo[246]
 PIN k_lo[247]
  DIRECTION INPUT ;
  USE SIGNAL ;
  PORT
   LAYER M5 ;
   RECT 288.192 280.716 288.216 280.800 ;
  END
 END k_lo[247]
 PIN k_lo[248]
  DIRECTION INPUT ;
  USE SIGNAL ;
  PORT
   LAYER M5 ;
   RECT 288.384 280.716 288.408 280.800 ;
  END
 END k_lo[248]
 PIN k_lo[249]
  DIRECTION INPUT ;
  USE SIGNAL ;
  PORT
   LAYER M5 ;
   RECT 288.576 280.716 288.600 280.800 ;
  END
 END k_lo[249]
 PIN k_lo[250]
  DIRECTION INPUT ;
  USE SIGNAL ;
  PORT
   LAYER M5 ;
   RECT 288.768 280.716 288.792 280.800 ;
  END
 END k_lo[250]
 PIN k_lo[251]
  DIRECTION INPUT ;
  USE SIGNAL ;
  PORT
   LAYER M5 ;
   RECT 288.960 280.716 288.984 280.800 ;
  END
 END k_lo[251]
 PIN k_lo[252]
  DIRECTION INPUT ;
  USE SIGNAL ;
  PORT
   LAYER M5 ;
   RECT 289.152 280.716 289.176 280.800 ;
  END
 END k_lo[252]
 PIN k_lo[253]
  DIRECTION INPUT ;
  USE SIGNAL ;
  PORT
   LAYER M5 ;
   RECT 289.344 280.716 289.368 280.800 ;
  END
 END k_lo[253]
 PIN k_lo[254]
  DIRECTION INPUT ;
  USE SIGNAL ;
  PORT
   LAYER M5 ;
   RECT 289.536 280.716 289.560 280.800 ;
  END
 END k_lo[254]
 PIN k_lo[255]
  DIRECTION INPUT ;
  USE SIGNAL ;
  PORT
   LAYER M5 ;
   RECT 289.728 280.716 289.752 280.800 ;
  END
 END k_lo[255]
 PIN k_lo[256]
  DIRECTION INPUT ;
  USE SIGNAL ;
  PORT
   LAYER M5 ;
   RECT 289.920 280.716 289.944 280.800 ;
  END
 END k_lo[256]
 PIN k_lo[257]
  DIRECTION INPUT ;
  USE SIGNAL ;
  PORT
   LAYER M5 ;
   RECT 290.112 280.716 290.136 280.800 ;
  END
 END k_lo[257]
 PIN k_lo[258]
  DIRECTION INPUT ;
  USE SIGNAL ;
  PORT
   LAYER M5 ;
   RECT 290.304 280.716 290.328 280.800 ;
  END
 END k_lo[258]
 PIN k_lo[259]
  DIRECTION INPUT ;
  USE SIGNAL ;
  PORT
   LAYER M5 ;
   RECT 290.496 280.716 290.520 280.800 ;
  END
 END k_lo[259]
 PIN k_lo[260]
  DIRECTION INPUT ;
  USE SIGNAL ;
  PORT
   LAYER M5 ;
   RECT 290.688 280.716 290.712 280.800 ;
  END
 END k_lo[260]
 PIN k_lo[261]
  DIRECTION INPUT ;
  USE SIGNAL ;
  PORT
   LAYER M5 ;
   RECT 290.880 280.716 290.904 280.800 ;
  END
 END k_lo[261]
 PIN k_lo[262]
  DIRECTION INPUT ;
  USE SIGNAL ;
  PORT
   LAYER M5 ;
   RECT 291.072 280.716 291.096 280.800 ;
  END
 END k_lo[262]
 PIN k_lo[263]
  DIRECTION INPUT ;
  USE SIGNAL ;
  PORT
   LAYER M5 ;
   RECT 291.264 280.716 291.288 280.800 ;
  END
 END k_lo[263]
 PIN k_lo[264]
  DIRECTION INPUT ;
  USE SIGNAL ;
  PORT
   LAYER M5 ;
   RECT 291.456 280.716 291.480 280.800 ;
  END
 END k_lo[264]
 PIN k_lo[265]
  DIRECTION INPUT ;
  USE SIGNAL ;
  PORT
   LAYER M5 ;
   RECT 291.648 280.716 291.672 280.800 ;
  END
 END k_lo[265]
 PIN k_lo[266]
  DIRECTION INPUT ;
  USE SIGNAL ;
  PORT
   LAYER M5 ;
   RECT 291.840 280.716 291.864 280.800 ;
  END
 END k_lo[266]
 PIN k_lo[267]
  DIRECTION INPUT ;
  USE SIGNAL ;
  PORT
   LAYER M5 ;
   RECT 292.032 280.716 292.056 280.800 ;
  END
 END k_lo[267]
 PIN k_lo[268]
  DIRECTION INPUT ;
  USE SIGNAL ;
  PORT
   LAYER M5 ;
   RECT 292.224 280.716 292.248 280.800 ;
  END
 END k_lo[268]
 PIN k_lo[269]
  DIRECTION INPUT ;
  USE SIGNAL ;
  PORT
   LAYER M5 ;
   RECT 292.416 280.716 292.440 280.800 ;
  END
 END k_lo[269]
 PIN k_lo[270]
  DIRECTION INPUT ;
  USE SIGNAL ;
  PORT
   LAYER M5 ;
   RECT 292.608 280.716 292.632 280.800 ;
  END
 END k_lo[270]
 PIN k_lo[271]
  DIRECTION INPUT ;
  USE SIGNAL ;
  PORT
   LAYER M5 ;
   RECT 292.800 280.716 292.824 280.800 ;
  END
 END k_lo[271]
 PIN k_lo[272]
  DIRECTION INPUT ;
  USE SIGNAL ;
  PORT
   LAYER M5 ;
   RECT 292.992 280.716 293.016 280.800 ;
  END
 END k_lo[272]
 PIN k_lo[273]
  DIRECTION INPUT ;
  USE SIGNAL ;
  PORT
   LAYER M5 ;
   RECT 293.184 280.716 293.208 280.800 ;
  END
 END k_lo[273]
 PIN k_lo[274]
  DIRECTION INPUT ;
  USE SIGNAL ;
  PORT
   LAYER M5 ;
   RECT 293.376 280.716 293.400 280.800 ;
  END
 END k_lo[274]
 PIN k_lo[275]
  DIRECTION INPUT ;
  USE SIGNAL ;
  PORT
   LAYER M5 ;
   RECT 293.568 280.716 293.592 280.800 ;
  END
 END k_lo[275]
 PIN k_lo[276]
  DIRECTION INPUT ;
  USE SIGNAL ;
  PORT
   LAYER M5 ;
   RECT 293.760 280.716 293.784 280.800 ;
  END
 END k_lo[276]
 PIN k_lo[277]
  DIRECTION INPUT ;
  USE SIGNAL ;
  PORT
   LAYER M5 ;
   RECT 293.952 280.716 293.976 280.800 ;
  END
 END k_lo[277]
 PIN k_lo[278]
  DIRECTION INPUT ;
  USE SIGNAL ;
  PORT
   LAYER M5 ;
   RECT 294.144 280.716 294.168 280.800 ;
  END
 END k_lo[278]
 PIN k_lo[279]
  DIRECTION INPUT ;
  USE SIGNAL ;
  PORT
   LAYER M5 ;
   RECT 294.336 280.716 294.360 280.800 ;
  END
 END k_lo[279]
 PIN k_lo[280]
  DIRECTION INPUT ;
  USE SIGNAL ;
  PORT
   LAYER M5 ;
   RECT 294.528 280.716 294.552 280.800 ;
  END
 END k_lo[280]
 PIN k_lo[281]
  DIRECTION INPUT ;
  USE SIGNAL ;
  PORT
   LAYER M5 ;
   RECT 294.720 280.716 294.744 280.800 ;
  END
 END k_lo[281]
 PIN k_lo[282]
  DIRECTION INPUT ;
  USE SIGNAL ;
  PORT
   LAYER M5 ;
   RECT 294.912 280.716 294.936 280.800 ;
  END
 END k_lo[282]
 PIN k_lo[283]
  DIRECTION INPUT ;
  USE SIGNAL ;
  PORT
   LAYER M5 ;
   RECT 295.104 280.716 295.128 280.800 ;
  END
 END k_lo[283]
 PIN k_lo[284]
  DIRECTION INPUT ;
  USE SIGNAL ;
  PORT
   LAYER M5 ;
   RECT 295.296 280.716 295.320 280.800 ;
  END
 END k_lo[284]
 PIN k_lo[285]
  DIRECTION INPUT ;
  USE SIGNAL ;
  PORT
   LAYER M5 ;
   RECT 295.488 280.716 295.512 280.800 ;
  END
 END k_lo[285]
 PIN k_lo[286]
  DIRECTION INPUT ;
  USE SIGNAL ;
  PORT
   LAYER M5 ;
   RECT 295.680 280.716 295.704 280.800 ;
  END
 END k_lo[286]
 PIN k_lo[287]
  DIRECTION INPUT ;
  USE SIGNAL ;
  PORT
   LAYER M5 ;
   RECT 295.872 280.716 295.896 280.800 ;
  END
 END k_lo[287]
 PIN k_lo[288]
  DIRECTION INPUT ;
  USE SIGNAL ;
  PORT
   LAYER M5 ;
   RECT 296.064 280.716 296.088 280.800 ;
  END
 END k_lo[288]
 PIN k_lo[289]
  DIRECTION INPUT ;
  USE SIGNAL ;
  PORT
   LAYER M5 ;
   RECT 296.256 280.716 296.280 280.800 ;
  END
 END k_lo[289]
 PIN k_lo[290]
  DIRECTION INPUT ;
  USE SIGNAL ;
  PORT
   LAYER M5 ;
   RECT 296.448 280.716 296.472 280.800 ;
  END
 END k_lo[290]
 PIN k_lo[291]
  DIRECTION INPUT ;
  USE SIGNAL ;
  PORT
   LAYER M5 ;
   RECT 296.640 280.716 296.664 280.800 ;
  END
 END k_lo[291]
 PIN k_lo[292]
  DIRECTION INPUT ;
  USE SIGNAL ;
  PORT
   LAYER M5 ;
   RECT 296.832 280.716 296.856 280.800 ;
  END
 END k_lo[292]
 PIN k_lo[293]
  DIRECTION INPUT ;
  USE SIGNAL ;
  PORT
   LAYER M5 ;
   RECT 297.024 280.716 297.048 280.800 ;
  END
 END k_lo[293]
 PIN k_lo[294]
  DIRECTION INPUT ;
  USE SIGNAL ;
  PORT
   LAYER M5 ;
   RECT 297.216 280.716 297.240 280.800 ;
  END
 END k_lo[294]
 PIN k_lo[295]
  DIRECTION INPUT ;
  USE SIGNAL ;
  PORT
   LAYER M5 ;
   RECT 297.408 280.716 297.432 280.800 ;
  END
 END k_lo[295]
 PIN k_lo[296]
  DIRECTION INPUT ;
  USE SIGNAL ;
  PORT
   LAYER M5 ;
   RECT 297.600 280.716 297.624 280.800 ;
  END
 END k_lo[296]
 PIN k_lo[297]
  DIRECTION INPUT ;
  USE SIGNAL ;
  PORT
   LAYER M5 ;
   RECT 297.792 280.716 297.816 280.800 ;
  END
 END k_lo[297]
 PIN k_lo[298]
  DIRECTION INPUT ;
  USE SIGNAL ;
  PORT
   LAYER M5 ;
   RECT 297.984 280.716 298.008 280.800 ;
  END
 END k_lo[298]
 PIN k_lo[299]
  DIRECTION INPUT ;
  USE SIGNAL ;
  PORT
   LAYER M5 ;
   RECT 298.176 280.716 298.200 280.800 ;
  END
 END k_lo[299]
 PIN k_lo[300]
  DIRECTION INPUT ;
  USE SIGNAL ;
  PORT
   LAYER M5 ;
   RECT 298.368 280.716 298.392 280.800 ;
  END
 END k_lo[300]
 PIN k_lo[301]
  DIRECTION INPUT ;
  USE SIGNAL ;
  PORT
   LAYER M5 ;
   RECT 298.560 280.716 298.584 280.800 ;
  END
 END k_lo[301]
 PIN k_lo[302]
  DIRECTION INPUT ;
  USE SIGNAL ;
  PORT
   LAYER M5 ;
   RECT 298.752 280.716 298.776 280.800 ;
  END
 END k_lo[302]
 PIN k_lo[303]
  DIRECTION INPUT ;
  USE SIGNAL ;
  PORT
   LAYER M5 ;
   RECT 298.944 280.716 298.968 280.800 ;
  END
 END k_lo[303]
 PIN k_lo[304]
  DIRECTION INPUT ;
  USE SIGNAL ;
  PORT
   LAYER M5 ;
   RECT 299.136 280.716 299.160 280.800 ;
  END
 END k_lo[304]
 PIN k_lo[305]
  DIRECTION INPUT ;
  USE SIGNAL ;
  PORT
   LAYER M5 ;
   RECT 299.328 280.716 299.352 280.800 ;
  END
 END k_lo[305]
 PIN k_lo[306]
  DIRECTION INPUT ;
  USE SIGNAL ;
  PORT
   LAYER M5 ;
   RECT 299.520 280.716 299.544 280.800 ;
  END
 END k_lo[306]
 PIN k_lo[307]
  DIRECTION INPUT ;
  USE SIGNAL ;
  PORT
   LAYER M5 ;
   RECT 299.712 280.716 299.736 280.800 ;
  END
 END k_lo[307]
 PIN k_lo[308]
  DIRECTION INPUT ;
  USE SIGNAL ;
  PORT
   LAYER M5 ;
   RECT 299.904 280.716 299.928 280.800 ;
  END
 END k_lo[308]
 PIN k_lo[309]
  DIRECTION INPUT ;
  USE SIGNAL ;
  PORT
   LAYER M5 ;
   RECT 300.096 280.716 300.120 280.800 ;
  END
 END k_lo[309]
 PIN k_L[0]
  DIRECTION INPUT ;
  USE SIGNAL ;
  PORT
   LAYER M5 ;
   RECT 300.288 280.716 300.312 280.800 ;
  END
 END k_L[0]
 PIN k_L[1]
  DIRECTION INPUT ;
  USE SIGNAL ;
  PORT
   LAYER M5 ;
   RECT 300.480 280.716 300.504 280.800 ;
  END
 END k_L[1]
 PIN k_L[2]
  DIRECTION INPUT ;
  USE SIGNAL ;
  PORT
   LAYER M5 ;
   RECT 300.672 280.716 300.696 280.800 ;
  END
 END k_L[2]
 PIN k_L[3]
  DIRECTION INPUT ;
  USE SIGNAL ;
  PORT
   LAYER M5 ;
   RECT 300.864 280.716 300.888 280.800 ;
  END
 END k_L[3]
 PIN k_L[4]
  DIRECTION INPUT ;
  USE SIGNAL ;
  PORT
   LAYER M5 ;
   RECT 301.056 280.716 301.080 280.800 ;
  END
 END k_L[4]
 PIN k_any
  DIRECTION INPUT ;
  USE SIGNAL ;
  PORT
   LAYER M5 ;
   RECT 301.248 280.716 301.272 280.800 ;
  END
 END k_any
 PIN lpr_syn
  DIRECTION INPUT ;
  USE SIGNAL ;
  PORT
   LAYER M5 ;
   RECT 338.016 280.716 338.040 280.800 ;
  END
 END lpr_syn
 PIN lpr_dly
  DIRECTION INPUT ;
  USE SIGNAL ;
  PORT
   LAYER M5 ;
   RECT 338.208 280.716 338.232 280.800 ;
  END
 END lpr_dly
 PIN lpr_chn
  DIRECTION INPUT ;
  USE SIGNAL ;
  PORT
   LAYER M5 ;
   RECT 338.400 280.716 338.424 280.800 ;
  END
 END lpr_chn
 PIN lpr_out
  DIRECTION INPUT ;
  USE SIGNAL ;
  PORT
   LAYER M5 ;
   RECT 338.592 280.716 338.616 280.800 ;
  END
 END lpr_out
 PIN q_d[0]
  DIRECTION OUTPUT ;
  USE SIGNAL ;
  PORT
   LAYER M5 ;
   RECT 520.032 0.000 520.056 0.084 ;
  END
 END q_d[0]
 PIN q_d[1]
  DIRECTION OUTPUT ;
  USE SIGNAL ;
  PORT
   LAYER M5 ;
   RECT 520.224 0.000 520.248 0.084 ;
  END
 END q_d[1]
 PIN q_d[2]
  DIRECTION OUTPUT ;
  USE SIGNAL ;
  PORT
   LAYER M5 ;
   RECT 520.416 0.000 520.440 0.084 ;
  END
 END q_d[2]
 PIN q_d[3]
  DIRECTION OUTPUT ;
  USE SIGNAL ;
  PORT
   LAYER M5 ;
   RECT 520.608 0.000 520.632 0.084 ;
  END
 END q_d[3]
 PIN q_d[4]
  DIRECTION OUTPUT ;
  USE SIGNAL ;
  PORT
   LAYER M5 ;
   RECT 520.800 0.000 520.824 0.084 ;
  END
 END q_d[4]
 PIN q_d[5]
  DIRECTION OUTPUT ;
  USE SIGNAL ;
  PORT
   LAYER M5 ;
   RECT 520.992 0.000 521.016 0.084 ;
  END
 END q_d[5]
 PIN q_d[6]
  DIRECTION OUTPUT ;
  USE SIGNAL ;
  PORT
   LAYER M5 ;
   RECT 521.184 0.000 521.208 0.084 ;
  END
 END q_d[6]
 PIN q_d[7]
  DIRECTION OUTPUT ;
  USE SIGNAL ;
  PORT
   LAYER M5 ;
   RECT 521.376 0.000 521.400 0.084 ;
  END
 END q_d[7]
 PIN q_d[8]
  DIRECTION OUTPUT ;
  USE SIGNAL ;
  PORT
   LAYER M5 ;
   RECT 521.568 0.000 521.592 0.084 ;
  END
 END q_d[8]
 PIN q_d[9]
  DIRECTION OUTPUT ;
  USE SIGNAL ;
  PORT
   LAYER M5 ;
   RECT 521.760 0.000 521.784 0.084 ;
  END
 END q_d[9]
 PIN q_d[10]
  DIRECTION OUTPUT ;
  USE SIGNAL ;
  PORT
   LAYER M5 ;
   RECT 521.952 0.000 521.976 0.084 ;
  END
 END q_d[10]
 PIN q_d[11]
  DIRECTION OUTPUT ;
  USE SIGNAL ;
  PORT
   LAYER M5 ;
   RECT 522.144 0.000 522.168 0.084 ;
  END
 END q_d[11]
 PIN q_d[12]
  DIRECTION OUTPUT ;
  USE SIGNAL ;
  PORT
   LAYER M5 ;
   RECT 522.336 0.000 522.360 0.084 ;
  END
 END q_d[12]
 PIN q_d[13]
  DIRECTION OUTPUT ;
  USE SIGNAL ;
  PORT
   LAYER M5 ;
   RECT 522.528 0.000 522.552 0.084 ;
  END
 END q_d[13]
 PIN q_d[14]
  DIRECTION OUTPUT ;
  USE SIGNAL ;
  PORT
   LAYER M5 ;
   RECT 522.720 0.000 522.744 0.084 ;
  END
 END q_d[14]
 PIN q_d[15]
  DIRECTION OUTPUT ;
  USE SIGNAL ;
  PORT
   LAYER M5 ;
   RECT 522.912 0.000 522.936 0.084 ;
  END
 END q_d[15]
 PIN q_d[16]
  DIRECTION OUTPUT ;
  USE SIGNAL ;
  PORT
   LAYER M5 ;
   RECT 523.104 0.000 523.128 0.084 ;
  END
 END q_d[16]
 PIN q_d[17]
  DIRECTION OUTPUT ;
  USE SIGNAL ;
  PORT
   LAYER M5 ;
   RECT 523.296 0.000 523.320 0.084 ;
  END
 END q_d[17]
 PIN q_d[18]
  DIRECTION OUTPUT ;
  USE SIGNAL ;
  PORT
   LAYER M5 ;
   RECT 523.488 0.000 523.512 0.084 ;
  END
 END q_d[18]
 PIN q_d[19]
  DIRECTION OUTPUT ;
  USE SIGNAL ;
  PORT
   LAYER M5 ;
   RECT 523.680 0.000 523.704 0.084 ;
  END
 END q_d[19]
 PIN q_d[20]
  DIRECTION OUTPUT ;
  USE SIGNAL ;
  PORT
   LAYER M5 ;
   RECT 523.872 0.000 523.896 0.084 ;
  END
 END q_d[20]
 PIN q_d[21]
  DIRECTION OUTPUT ;
  USE SIGNAL ;
  PORT
   LAYER M5 ;
   RECT 524.064 0.000 524.088 0.084 ;
  END
 END q_d[21]
 PIN q_d[22]
  DIRECTION OUTPUT ;
  USE SIGNAL ;
  PORT
   LAYER M5 ;
   RECT 524.256 0.000 524.280 0.084 ;
  END
 END q_d[22]
 PIN q_d[23]
  DIRECTION OUTPUT ;
  USE SIGNAL ;
  PORT
   LAYER M5 ;
   RECT 524.448 0.000 524.472 0.084 ;
  END
 END q_d[23]
 PIN q_d[24]
  DIRECTION OUTPUT ;
  USE SIGNAL ;
  PORT
   LAYER M5 ;
   RECT 524.640 0.000 524.664 0.084 ;
  END
 END q_d[24]
 PIN q_d[25]
  DIRECTION OUTPUT ;
  USE SIGNAL ;
  PORT
   LAYER M5 ;
   RECT 524.832 0.000 524.856 0.084 ;
  END
 END q_d[25]
 PIN q_d[26]
  DIRECTION OUTPUT ;
  USE SIGNAL ;
  PORT
   LAYER M5 ;
   RECT 525.024 0.000 525.048 0.084 ;
  END
 END q_d[26]
 PIN q_d[27]
  DIRECTION OUTPUT ;
  USE SIGNAL ;
  PORT
   LAYER M5 ;
   RECT 525.216 0.000 525.240 0.084 ;
  END
 END q_d[27]
 PIN q_d[28]
  DIRECTION OUTPUT ;
  USE SIGNAL ;
  PORT
   LAYER M5 ;
   RECT 525.408 0.000 525.432 0.084 ;
  END
 END q_d[28]
 PIN q_d[29]
  DIRECTION OUTPUT ;
  USE SIGNAL ;
  PORT
   LAYER M5 ;
   RECT 525.600 0.000 525.624 0.084 ;
  END
 END q_d[29]
 PIN q_d[30]
  DIRECTION OUTPUT ;
  USE SIGNAL ;
  PORT
   LAYER M5 ;
   RECT 525.792 0.000 525.816 0.084 ;
  END
 END q_d[30]
 PIN q_d[31]
  DIRECTION OUTPUT ;
  USE SIGNAL ;
  PORT
   LAYER M5 ;
   RECT 525.984 0.000 526.008 0.084 ;
  END
 END q_d[31]
 PIN q_d[32]
  DIRECTION OUTPUT ;
  USE SIGNAL ;
  PORT
   LAYER M5 ;
   RECT 526.176 0.000 526.200 0.084 ;
  END
 END q_d[32]
 PIN q_d[33]
  DIRECTION OUTPUT ;
  USE SIGNAL ;
  PORT
   LAYER M5 ;
   RECT 526.368 0.000 526.392 0.084 ;
  END
 END q_d[33]
 PIN q_d[34]
  DIRECTION OUTPUT ;
  USE SIGNAL ;
  PORT
   LAYER M5 ;
   RECT 526.560 0.000 526.584 0.084 ;
  END
 END q_d[34]
 PIN q_d[35]
  DIRECTION OUTPUT ;
  USE SIGNAL ;
  PORT
   LAYER M5 ;
   RECT 526.752 0.000 526.776 0.084 ;
  END
 END q_d[35]
 PIN q_d[36]
  DIRECTION OUTPUT ;
  USE SIGNAL ;
  PORT
   LAYER M5 ;
   RECT 526.944 0.000 526.968 0.084 ;
  END
 END q_d[36]
 PIN q_d[37]
  DIRECTION OUTPUT ;
  USE SIGNAL ;
  PORT
   LAYER M5 ;
   RECT 527.136 0.000 527.160 0.084 ;
  END
 END q_d[37]
 PIN q_d[38]
  DIRECTION OUTPUT ;
  USE SIGNAL ;
  PORT
   LAYER M5 ;
   RECT 527.328 0.000 527.352 0.084 ;
  END
 END q_d[38]
 PIN q_d[39]
  DIRECTION OUTPUT ;
  USE SIGNAL ;
  PORT
   LAYER M5 ;
   RECT 527.520 0.000 527.544 0.084 ;
  END
 END q_d[39]
 PIN q_d[40]
  DIRECTION OUTPUT ;
  USE SIGNAL ;
  PORT
   LAYER M5 ;
   RECT 527.712 0.000 527.736 0.084 ;
  END
 END q_d[40]
 PIN q_d[41]
  DIRECTION OUTPUT ;
  USE SIGNAL ;
  PORT
   LAYER M5 ;
   RECT 527.904 0.000 527.928 0.084 ;
  END
 END q_d[41]
 PIN q_d[42]
  DIRECTION OUTPUT ;
  USE SIGNAL ;
  PORT
   LAYER M5 ;
   RECT 528.096 0.000 528.120 0.084 ;
  END
 END q_d[42]
 PIN q_d[43]
  DIRECTION OUTPUT ;
  USE SIGNAL ;
  PORT
   LAYER M5 ;
   RECT 528.288 0.000 528.312 0.084 ;
  END
 END q_d[43]
 PIN q_d[44]
  DIRECTION OUTPUT ;
  USE SIGNAL ;
  PORT
   LAYER M5 ;
   RECT 528.480 0.000 528.504 0.084 ;
  END
 END q_d[44]
 PIN q_d[45]
  DIRECTION OUTPUT ;
  USE SIGNAL ;
  PORT
   LAYER M5 ;
   RECT 528.672 0.000 528.696 0.084 ;
  END
 END q_d[45]
 PIN q_d[46]
  DIRECTION OUTPUT ;
  USE SIGNAL ;
  PORT
   LAYER M5 ;
   RECT 528.864 0.000 528.888 0.084 ;
  END
 END q_d[46]
 PIN q_d[47]
  DIRECTION OUTPUT ;
  USE SIGNAL ;
  PORT
   LAYER M5 ;
   RECT 529.056 0.000 529.080 0.084 ;
  END
 END q_d[47]
 PIN q_d[48]
  DIRECTION OUTPUT ;
  USE SIGNAL ;
  PORT
   LAYER M5 ;
   RECT 529.248 0.000 529.272 0.084 ;
  END
 END q_d[48]
 PIN q_d[49]
  DIRECTION OUTPUT ;
  USE SIGNAL ;
  PORT
   LAYER M5 ;
   RECT 529.440 0.000 529.464 0.084 ;
  END
 END q_d[49]
 PIN q_d[50]
  DIRECTION OUTPUT ;
  USE SIGNAL ;
  PORT
   LAYER M5 ;
   RECT 529.632 0.000 529.656 0.084 ;
  END
 END q_d[50]
 PIN q_d[51]
  DIRECTION OUTPUT ;
  USE SIGNAL ;
  PORT
   LAYER M5 ;
   RECT 529.824 0.000 529.848 0.084 ;
  END
 END q_d[51]
 PIN q_d[52]
  DIRECTION OUTPUT ;
  USE SIGNAL ;
  PORT
   LAYER M5 ;
   RECT 530.016 0.000 530.040 0.084 ;
  END
 END q_d[52]
 PIN q_d[53]
  DIRECTION OUTPUT ;
  USE SIGNAL ;
  PORT
   LAYER M5 ;
   RECT 530.208 0.000 530.232 0.084 ;
  END
 END q_d[53]
 PIN q_d[54]
  DIRECTION OUTPUT ;
  USE SIGNAL ;
  PORT
   LAYER M5 ;
   RECT 530.400 0.000 530.424 0.084 ;
  END
 END q_d[54]
 PIN q_d[55]
  DIRECTION OUTPUT ;
  USE SIGNAL ;
  PORT
   LAYER M5 ;
   RECT 530.592 0.000 530.616 0.084 ;
  END
 END q_d[55]
 PIN q_d[56]
  DIRECTION OUTPUT ;
  USE SIGNAL ;
  PORT
   LAYER M5 ;
   RECT 530.784 0.000 530.808 0.084 ;
  END
 END q_d[56]
 PIN q_d[57]
  DIRECTION OUTPUT ;
  USE SIGNAL ;
  PORT
   LAYER M5 ;
   RECT 530.976 0.000 531.000 0.084 ;
  END
 END q_d[57]
 PIN q_d[58]
  DIRECTION OUTPUT ;
  USE SIGNAL ;
  PORT
   LAYER M5 ;
   RECT 531.168 0.000 531.192 0.084 ;
  END
 END q_d[58]
 PIN q_d[59]
  DIRECTION OUTPUT ;
  USE SIGNAL ;
  PORT
   LAYER M5 ;
   RECT 531.360 0.000 531.384 0.084 ;
  END
 END q_d[59]
 PIN q_d[60]
  DIRECTION OUTPUT ;
  USE SIGNAL ;
  PORT
   LAYER M5 ;
   RECT 531.552 0.000 531.576 0.084 ;
  END
 END q_d[60]
 PIN q_d[61]
  DIRECTION OUTPUT ;
  USE SIGNAL ;
  PORT
   LAYER M5 ;
   RECT 531.744 0.000 531.768 0.084 ;
  END
 END q_d[61]
 PIN q_d[62]
  DIRECTION OUTPUT ;
  USE SIGNAL ;
  PORT
   LAYER M5 ;
   RECT 531.936 0.000 531.960 0.084 ;
  END
 END q_d[62]
 PIN q_d[63]
  DIRECTION OUTPUT ;
  USE SIGNAL ;
  PORT
   LAYER M5 ;
   RECT 532.128 0.000 532.152 0.084 ;
  END
 END q_d[63]
 PIN q_d[64]
  DIRECTION OUTPUT ;
  USE SIGNAL ;
  PORT
   LAYER M5 ;
   RECT 532.320 0.000 532.344 0.084 ;
  END
 END q_d[64]
 PIN q_d[65]
  DIRECTION OUTPUT ;
  USE SIGNAL ;
  PORT
   LAYER M5 ;
   RECT 532.512 0.000 532.536 0.084 ;
  END
 END q_d[65]
 PIN q_d[66]
  DIRECTION OUTPUT ;
  USE SIGNAL ;
  PORT
   LAYER M5 ;
   RECT 532.704 0.000 532.728 0.084 ;
  END
 END q_d[66]
 PIN q_d[67]
  DIRECTION OUTPUT ;
  USE SIGNAL ;
  PORT
   LAYER M5 ;
   RECT 532.896 0.000 532.920 0.084 ;
  END
 END q_d[67]
 PIN q_d[68]
  DIRECTION OUTPUT ;
  USE SIGNAL ;
  PORT
   LAYER M5 ;
   RECT 533.088 0.000 533.112 0.084 ;
  END
 END q_d[68]
 PIN q_d[69]
  DIRECTION OUTPUT ;
  USE SIGNAL ;
  PORT
   LAYER M5 ;
   RECT 533.280 0.000 533.304 0.084 ;
  END
 END q_d[69]
 PIN q_d[70]
  DIRECTION OUTPUT ;
  USE SIGNAL ;
  PORT
   LAYER M5 ;
   RECT 533.472 0.000 533.496 0.084 ;
  END
 END q_d[70]
 PIN q_d[71]
  DIRECTION OUTPUT ;
  USE SIGNAL ;
  PORT
   LAYER M5 ;
   RECT 533.664 0.000 533.688 0.084 ;
  END
 END q_d[71]
 PIN q_d[72]
  DIRECTION OUTPUT ;
  USE SIGNAL ;
  PORT
   LAYER M5 ;
   RECT 533.856 0.000 533.880 0.084 ;
  END
 END q_d[72]
 PIN q_d[73]
  DIRECTION OUTPUT ;
  USE SIGNAL ;
  PORT
   LAYER M5 ;
   RECT 534.048 0.000 534.072 0.084 ;
  END
 END q_d[73]
 PIN q_d[74]
  DIRECTION OUTPUT ;
  USE SIGNAL ;
  PORT
   LAYER M5 ;
   RECT 534.240 0.000 534.264 0.084 ;
  END
 END q_d[74]
 PIN q_d[75]
  DIRECTION OUTPUT ;
  USE SIGNAL ;
  PORT
   LAYER M5 ;
   RECT 534.432 0.000 534.456 0.084 ;
  END
 END q_d[75]
 PIN q_d[76]
  DIRECTION OUTPUT ;
  USE SIGNAL ;
  PORT
   LAYER M5 ;
   RECT 534.624 0.000 534.648 0.084 ;
  END
 END q_d[76]
 PIN q_d[77]
  DIRECTION OUTPUT ;
  USE SIGNAL ;
  PORT
   LAYER M5 ;
   RECT 534.816 0.000 534.840 0.084 ;
  END
 END q_d[77]
 PIN q_d[78]
  DIRECTION OUTPUT ;
  USE SIGNAL ;
  PORT
   LAYER M5 ;
   RECT 535.008 0.000 535.032 0.084 ;
  END
 END q_d[78]
 PIN q_d[79]
  DIRECTION OUTPUT ;
  USE SIGNAL ;
  PORT
   LAYER M5 ;
   RECT 535.200 0.000 535.224 0.084 ;
  END
 END q_d[79]
 PIN q_d[80]
  DIRECTION OUTPUT ;
  USE SIGNAL ;
  PORT
   LAYER M5 ;
   RECT 535.392 0.000 535.416 0.084 ;
  END
 END q_d[80]
 PIN q_d[81]
  DIRECTION OUTPUT ;
  USE SIGNAL ;
  PORT
   LAYER M5 ;
   RECT 535.584 0.000 535.608 0.084 ;
  END
 END q_d[81]
 PIN q_d[82]
  DIRECTION OUTPUT ;
  USE SIGNAL ;
  PORT
   LAYER M5 ;
   RECT 535.776 0.000 535.800 0.084 ;
  END
 END q_d[82]
 PIN q_d[83]
  DIRECTION OUTPUT ;
  USE SIGNAL ;
  PORT
   LAYER M5 ;
   RECT 535.968 0.000 535.992 0.084 ;
  END
 END q_d[83]
 PIN q_d[84]
  DIRECTION OUTPUT ;
  USE SIGNAL ;
  PORT
   LAYER M5 ;
   RECT 536.160 0.000 536.184 0.084 ;
  END
 END q_d[84]
 PIN q_d[85]
  DIRECTION OUTPUT ;
  USE SIGNAL ;
  PORT
   LAYER M5 ;
   RECT 536.352 0.000 536.376 0.084 ;
  END
 END q_d[85]
 PIN q_d[86]
  DIRECTION OUTPUT ;
  USE SIGNAL ;
  PORT
   LAYER M5 ;
   RECT 536.544 0.000 536.568 0.084 ;
  END
 END q_d[86]
 PIN q_d[87]
  DIRECTION OUTPUT ;
  USE SIGNAL ;
  PORT
   LAYER M5 ;
   RECT 536.736 0.000 536.760 0.084 ;
  END
 END q_d[87]
 PIN q_d[88]
  DIRECTION OUTPUT ;
  USE SIGNAL ;
  PORT
   LAYER M5 ;
   RECT 536.928 0.000 536.952 0.084 ;
  END
 END q_d[88]
 PIN q_d[89]
  DIRECTION OUTPUT ;
  USE SIGNAL ;
  PORT
   LAYER M5 ;
   RECT 537.120 0.000 537.144 0.084 ;
  END
 END q_d[89]
 PIN q_d[90]
  DIRECTION OUTPUT ;
  USE SIGNAL ;
  PORT
   LAYER M5 ;
   RECT 537.312 0.000 537.336 0.084 ;
  END
 END q_d[90]
 PIN q_d[91]
  DIRECTION OUTPUT ;
  USE SIGNAL ;
  PORT
   LAYER M5 ;
   RECT 537.504 0.000 537.528 0.084 ;
  END
 END q_d[91]
 PIN q_d[92]
  DIRECTION OUTPUT ;
  USE SIGNAL ;
  PORT
   LAYER M5 ;
   RECT 537.696 0.000 537.720 0.084 ;
  END
 END q_d[92]
 PIN q_d[93]
  DIRECTION OUTPUT ;
  USE SIGNAL ;
  PORT
   LAYER M5 ;
   RECT 537.888 0.000 537.912 0.084 ;
  END
 END q_d[93]
 PIN q_d[94]
  DIRECTION OUTPUT ;
  USE SIGNAL ;
  PORT
   LAYER M5 ;
   RECT 538.080 0.000 538.104 0.084 ;
  END
 END q_d[94]
 PIN q_d[95]
  DIRECTION OUTPUT ;
  USE SIGNAL ;
  PORT
   LAYER M5 ;
   RECT 538.272 0.000 538.296 0.084 ;
  END
 END q_d[95]
 PIN q_d[96]
  DIRECTION OUTPUT ;
  USE SIGNAL ;
  PORT
   LAYER M5 ;
   RECT 538.464 0.000 538.488 0.084 ;
  END
 END q_d[96]
 PIN q_d[97]
  DIRECTION OUTPUT ;
  USE SIGNAL ;
  PORT
   LAYER M5 ;
   RECT 538.656 0.000 538.680 0.084 ;
  END
 END q_d[97]
 PIN q_d[98]
  DIRECTION OUTPUT ;
  USE SIGNAL ;
  PORT
   LAYER M5 ;
   RECT 538.848 0.000 538.872 0.084 ;
  END
 END q_d[98]
 PIN q_d[99]
  DIRECTION OUTPUT ;
  USE SIGNAL ;
  PORT
   LAYER M5 ;
   RECT 539.040 0.000 539.064 0.084 ;
  END
 END q_d[99]
 PIN q_d[100]
  DIRECTION OUTPUT ;
  USE SIGNAL ;
  PORT
   LAYER M5 ;
   RECT 539.232 0.000 539.256 0.084 ;
  END
 END q_d[100]
 PIN q_d[101]
  DIRECTION OUTPUT ;
  USE SIGNAL ;
  PORT
   LAYER M5 ;
   RECT 539.424 0.000 539.448 0.084 ;
  END
 END q_d[101]
 PIN q_d[102]
  DIRECTION OUTPUT ;
  USE SIGNAL ;
  PORT
   LAYER M5 ;
   RECT 539.616 0.000 539.640 0.084 ;
  END
 END q_d[102]
 PIN q_d[103]
  DIRECTION OUTPUT ;
  USE SIGNAL ;
  PORT
   LAYER M5 ;
   RECT 539.808 0.000 539.832 0.084 ;
  END
 END q_d[103]
 PIN q_d[104]
  DIRECTION OUTPUT ;
  USE SIGNAL ;
  PORT
   LAYER M5 ;
   RECT 540.000 0.000 540.024 0.084 ;
  END
 END q_d[104]
 PIN q_d[105]
  DIRECTION OUTPUT ;
  USE SIGNAL ;
  PORT
   LAYER M5 ;
   RECT 540.192 0.000 540.216 0.084 ;
  END
 END q_d[105]
 PIN q_d[106]
  DIRECTION OUTPUT ;
  USE SIGNAL ;
  PORT
   LAYER M5 ;
   RECT 540.384 0.000 540.408 0.084 ;
  END
 END q_d[106]
 PIN q_d[107]
  DIRECTION OUTPUT ;
  USE SIGNAL ;
  PORT
   LAYER M5 ;
   RECT 540.576 0.000 540.600 0.084 ;
  END
 END q_d[107]
 PIN q_d[108]
  DIRECTION OUTPUT ;
  USE SIGNAL ;
  PORT
   LAYER M5 ;
   RECT 540.768 0.000 540.792 0.084 ;
  END
 END q_d[108]
 PIN q_d[109]
  DIRECTION OUTPUT ;
  USE SIGNAL ;
  PORT
   LAYER M5 ;
   RECT 540.960 0.000 540.984 0.084 ;
  END
 END q_d[109]
 PIN q_d[110]
  DIRECTION OUTPUT ;
  USE SIGNAL ;
  PORT
   LAYER M5 ;
   RECT 541.152 0.000 541.176 0.084 ;
  END
 END q_d[110]
 PIN q_d[111]
  DIRECTION OUTPUT ;
  USE SIGNAL ;
  PORT
   LAYER M5 ;
   RECT 541.344 0.000 541.368 0.084 ;
  END
 END q_d[111]
 PIN q_d[112]
  DIRECTION OUTPUT ;
  USE SIGNAL ;
  PORT
   LAYER M5 ;
   RECT 541.536 0.000 541.560 0.084 ;
  END
 END q_d[112]
 PIN q_d[113]
  DIRECTION OUTPUT ;
  USE SIGNAL ;
  PORT
   LAYER M5 ;
   RECT 541.728 0.000 541.752 0.084 ;
  END
 END q_d[113]
 PIN q_d[114]
  DIRECTION OUTPUT ;
  USE SIGNAL ;
  PORT
   LAYER M5 ;
   RECT 541.920 0.000 541.944 0.084 ;
  END
 END q_d[114]
 PIN q_d[115]
  DIRECTION OUTPUT ;
  USE SIGNAL ;
  PORT
   LAYER M5 ;
   RECT 542.112 0.000 542.136 0.084 ;
  END
 END q_d[115]
 PIN q_d[116]
  DIRECTION OUTPUT ;
  USE SIGNAL ;
  PORT
   LAYER M5 ;
   RECT 542.304 0.000 542.328 0.084 ;
  END
 END q_d[116]
 PIN q_d[117]
  DIRECTION OUTPUT ;
  USE SIGNAL ;
  PORT
   LAYER M5 ;
   RECT 542.496 0.000 542.520 0.084 ;
  END
 END q_d[117]
 PIN q_d[118]
  DIRECTION OUTPUT ;
  USE SIGNAL ;
  PORT
   LAYER M5 ;
   RECT 542.688 0.000 542.712 0.084 ;
  END
 END q_d[118]
 PIN q_d[119]
  DIRECTION OUTPUT ;
  USE SIGNAL ;
  PORT
   LAYER M5 ;
   RECT 542.880 0.000 542.904 0.084 ;
  END
 END q_d[119]
 PIN q_d[120]
  DIRECTION OUTPUT ;
  USE SIGNAL ;
  PORT
   LAYER M5 ;
   RECT 543.072 0.000 543.096 0.084 ;
  END
 END q_d[120]
 PIN q_d[121]
  DIRECTION OUTPUT ;
  USE SIGNAL ;
  PORT
   LAYER M5 ;
   RECT 543.264 0.000 543.288 0.084 ;
  END
 END q_d[121]
 PIN q_d[122]
  DIRECTION OUTPUT ;
  USE SIGNAL ;
  PORT
   LAYER M5 ;
   RECT 543.456 0.000 543.480 0.084 ;
  END
 END q_d[122]
 PIN q_d[123]
  DIRECTION OUTPUT ;
  USE SIGNAL ;
  PORT
   LAYER M5 ;
   RECT 543.648 0.000 543.672 0.084 ;
  END
 END q_d[123]
 PIN q_d[124]
  DIRECTION OUTPUT ;
  USE SIGNAL ;
  PORT
   LAYER M5 ;
   RECT 543.840 0.000 543.864 0.084 ;
  END
 END q_d[124]
 PIN q_d[125]
  DIRECTION OUTPUT ;
  USE SIGNAL ;
  PORT
   LAYER M5 ;
   RECT 544.032 0.000 544.056 0.084 ;
  END
 END q_d[125]
 PIN q_d[126]
  DIRECTION OUTPUT ;
  USE SIGNAL ;
  PORT
   LAYER M5 ;
   RECT 544.224 0.000 544.248 0.084 ;
  END
 END q_d[126]
 PIN q_d[127]
  DIRECTION OUTPUT ;
  USE SIGNAL ;
  PORT
   LAYER M5 ;
   RECT 544.416 0.000 544.440 0.084 ;
  END
 END q_d[127]
 PIN q_d[128]
  DIRECTION OUTPUT ;
  USE SIGNAL ;
  PORT
   LAYER M5 ;
   RECT 544.608 0.000 544.632 0.084 ;
  END
 END q_d[128]
 PIN q_d[129]
  DIRECTION OUTPUT ;
  USE SIGNAL ;
  PORT
   LAYER M5 ;
   RECT 544.800 0.000 544.824 0.084 ;
  END
 END q_d[129]
 PIN q_d[130]
  DIRECTION OUTPUT ;
  USE SIGNAL ;
  PORT
   LAYER M5 ;
   RECT 544.992 0.000 545.016 0.084 ;
  END
 END q_d[130]
 PIN q_d[131]
  DIRECTION OUTPUT ;
  USE SIGNAL ;
  PORT
   LAYER M5 ;
   RECT 545.184 0.000 545.208 0.084 ;
  END
 END q_d[131]
 PIN q_d[132]
  DIRECTION OUTPUT ;
  USE SIGNAL ;
  PORT
   LAYER M5 ;
   RECT 545.376 0.000 545.400 0.084 ;
  END
 END q_d[132]
 PIN q_d[133]
  DIRECTION OUTPUT ;
  USE SIGNAL ;
  PORT
   LAYER M5 ;
   RECT 545.568 0.000 545.592 0.084 ;
  END
 END q_d[133]
 PIN q_d[134]
  DIRECTION OUTPUT ;
  USE SIGNAL ;
  PORT
   LAYER M5 ;
   RECT 545.760 0.000 545.784 0.084 ;
  END
 END q_d[134]
 PIN q_d[135]
  DIRECTION OUTPUT ;
  USE SIGNAL ;
  PORT
   LAYER M5 ;
   RECT 545.952 0.000 545.976 0.084 ;
  END
 END q_d[135]
 PIN q_d[136]
  DIRECTION OUTPUT ;
  USE SIGNAL ;
  PORT
   LAYER M5 ;
   RECT 546.144 0.000 546.168 0.084 ;
  END
 END q_d[136]
 PIN q_d[137]
  DIRECTION OUTPUT ;
  USE SIGNAL ;
  PORT
   LAYER M5 ;
   RECT 546.336 0.000 546.360 0.084 ;
  END
 END q_d[137]
 PIN q_d[138]
  DIRECTION OUTPUT ;
  USE SIGNAL ;
  PORT
   LAYER M5 ;
   RECT 546.528 0.000 546.552 0.084 ;
  END
 END q_d[138]
 PIN q_d[139]
  DIRECTION OUTPUT ;
  USE SIGNAL ;
  PORT
   LAYER M5 ;
   RECT 546.720 0.000 546.744 0.084 ;
  END
 END q_d[139]
 PIN q_d[140]
  DIRECTION OUTPUT ;
  USE SIGNAL ;
  PORT
   LAYER M5 ;
   RECT 546.912 0.000 546.936 0.084 ;
  END
 END q_d[140]
 PIN q_d[141]
  DIRECTION OUTPUT ;
  USE SIGNAL ;
  PORT
   LAYER M5 ;
   RECT 547.104 0.000 547.128 0.084 ;
  END
 END q_d[141]
 PIN q_d[142]
  DIRECTION OUTPUT ;
  USE SIGNAL ;
  PORT
   LAYER M5 ;
   RECT 547.296 0.000 547.320 0.084 ;
  END
 END q_d[142]
 PIN q_d[143]
  DIRECTION OUTPUT ;
  USE SIGNAL ;
  PORT
   LAYER M5 ;
   RECT 547.488 0.000 547.512 0.084 ;
  END
 END q_d[143]
 PIN q_d[144]
  DIRECTION OUTPUT ;
  USE SIGNAL ;
  PORT
   LAYER M5 ;
   RECT 547.680 0.000 547.704 0.084 ;
  END
 END q_d[144]
 PIN q_d[145]
  DIRECTION OUTPUT ;
  USE SIGNAL ;
  PORT
   LAYER M5 ;
   RECT 547.872 0.000 547.896 0.084 ;
  END
 END q_d[145]
 PIN q_d[146]
  DIRECTION OUTPUT ;
  USE SIGNAL ;
  PORT
   LAYER M5 ;
   RECT 548.064 0.000 548.088 0.084 ;
  END
 END q_d[146]
 PIN q_d[147]
  DIRECTION OUTPUT ;
  USE SIGNAL ;
  PORT
   LAYER M5 ;
   RECT 548.256 0.000 548.280 0.084 ;
  END
 END q_d[147]
 PIN q_d[148]
  DIRECTION OUTPUT ;
  USE SIGNAL ;
  PORT
   LAYER M5 ;
   RECT 548.448 0.000 548.472 0.084 ;
  END
 END q_d[148]
 PIN q_d[149]
  DIRECTION OUTPUT ;
  USE SIGNAL ;
  PORT
   LAYER M5 ;
   RECT 548.640 0.000 548.664 0.084 ;
  END
 END q_d[149]
 PIN q_d[150]
  DIRECTION OUTPUT ;
  USE SIGNAL ;
  PORT
   LAYER M5 ;
   RECT 548.832 0.000 548.856 0.084 ;
  END
 END q_d[150]
 PIN q_d[151]
  DIRECTION OUTPUT ;
  USE SIGNAL ;
  PORT
   LAYER M5 ;
   RECT 549.024 0.000 549.048 0.084 ;
  END
 END q_d[151]
 PIN q_d[152]
  DIRECTION OUTPUT ;
  USE SIGNAL ;
  PORT
   LAYER M5 ;
   RECT 549.216 0.000 549.240 0.084 ;
  END
 END q_d[152]
 PIN q_d[153]
  DIRECTION OUTPUT ;
  USE SIGNAL ;
  PORT
   LAYER M5 ;
   RECT 549.408 0.000 549.432 0.084 ;
  END
 END q_d[153]
 PIN q_d[154]
  DIRECTION OUTPUT ;
  USE SIGNAL ;
  PORT
   LAYER M5 ;
   RECT 549.600 0.000 549.624 0.084 ;
  END
 END q_d[154]
 PIN q_d[155]
  DIRECTION OUTPUT ;
  USE SIGNAL ;
  PORT
   LAYER M5 ;
   RECT 549.792 0.000 549.816 0.084 ;
  END
 END q_d[155]
 PIN q_d[156]
  DIRECTION OUTPUT ;
  USE SIGNAL ;
  PORT
   LAYER M5 ;
   RECT 549.984 0.000 550.008 0.084 ;
  END
 END q_d[156]
 PIN q_d[157]
  DIRECTION OUTPUT ;
  USE SIGNAL ;
  PORT
   LAYER M5 ;
   RECT 550.176 0.000 550.200 0.084 ;
  END
 END q_d[157]
 PIN q_d[158]
  DIRECTION OUTPUT ;
  USE SIGNAL ;
  PORT
   LAYER M5 ;
   RECT 550.368 0.000 550.392 0.084 ;
  END
 END q_d[158]
 PIN q_d[159]
  DIRECTION OUTPUT ;
  USE SIGNAL ;
  PORT
   LAYER M5 ;
   RECT 550.560 0.000 550.584 0.084 ;
  END
 END q_d[159]
 PIN q_d[160]
  DIRECTION OUTPUT ;
  USE SIGNAL ;
  PORT
   LAYER M5 ;
   RECT 550.752 0.000 550.776 0.084 ;
  END
 END q_d[160]
 PIN q_d[161]
  DIRECTION OUTPUT ;
  USE SIGNAL ;
  PORT
   LAYER M5 ;
   RECT 550.944 0.000 550.968 0.084 ;
  END
 END q_d[161]
 PIN q_d[162]
  DIRECTION OUTPUT ;
  USE SIGNAL ;
  PORT
   LAYER M5 ;
   RECT 551.136 0.000 551.160 0.084 ;
  END
 END q_d[162]
 PIN q_d[163]
  DIRECTION OUTPUT ;
  USE SIGNAL ;
  PORT
   LAYER M5 ;
   RECT 551.328 0.000 551.352 0.084 ;
  END
 END q_d[163]
 PIN q_d[164]
  DIRECTION OUTPUT ;
  USE SIGNAL ;
  PORT
   LAYER M5 ;
   RECT 551.520 0.000 551.544 0.084 ;
  END
 END q_d[164]
 PIN q_d[165]
  DIRECTION OUTPUT ;
  USE SIGNAL ;
  PORT
   LAYER M5 ;
   RECT 551.712 0.000 551.736 0.084 ;
  END
 END q_d[165]
 PIN q_d[166]
  DIRECTION OUTPUT ;
  USE SIGNAL ;
  PORT
   LAYER M5 ;
   RECT 551.904 0.000 551.928 0.084 ;
  END
 END q_d[166]
 PIN q_d[167]
  DIRECTION OUTPUT ;
  USE SIGNAL ;
  PORT
   LAYER M5 ;
   RECT 552.096 0.000 552.120 0.084 ;
  END
 END q_d[167]
 PIN q_d[168]
  DIRECTION OUTPUT ;
  USE SIGNAL ;
  PORT
   LAYER M5 ;
   RECT 552.288 0.000 552.312 0.084 ;
  END
 END q_d[168]
 PIN q_d[169]
  DIRECTION OUTPUT ;
  USE SIGNAL ;
  PORT
   LAYER M5 ;
   RECT 552.480 0.000 552.504 0.084 ;
  END
 END q_d[169]
 PIN q_d[170]
  DIRECTION OUTPUT ;
  USE SIGNAL ;
  PORT
   LAYER M5 ;
   RECT 552.672 0.000 552.696 0.084 ;
  END
 END q_d[170]
 PIN q_d[171]
  DIRECTION OUTPUT ;
  USE SIGNAL ;
  PORT
   LAYER M5 ;
   RECT 552.864 0.000 552.888 0.084 ;
  END
 END q_d[171]
 PIN q_d[172]
  DIRECTION OUTPUT ;
  USE SIGNAL ;
  PORT
   LAYER M5 ;
   RECT 553.056 0.000 553.080 0.084 ;
  END
 END q_d[172]
 PIN q_d[173]
  DIRECTION OUTPUT ;
  USE SIGNAL ;
  PORT
   LAYER M5 ;
   RECT 553.248 0.000 553.272 0.084 ;
  END
 END q_d[173]
 PIN q_d[174]
  DIRECTION OUTPUT ;
  USE SIGNAL ;
  PORT
   LAYER M5 ;
   RECT 553.440 0.000 553.464 0.084 ;
  END
 END q_d[174]
 PIN q_d[175]
  DIRECTION OUTPUT ;
  USE SIGNAL ;
  PORT
   LAYER M5 ;
   RECT 553.632 0.000 553.656 0.084 ;
  END
 END q_d[175]
 PIN q_d[176]
  DIRECTION OUTPUT ;
  USE SIGNAL ;
  PORT
   LAYER M5 ;
   RECT 553.824 0.000 553.848 0.084 ;
  END
 END q_d[176]
 PIN q_d[177]
  DIRECTION OUTPUT ;
  USE SIGNAL ;
  PORT
   LAYER M5 ;
   RECT 554.016 0.000 554.040 0.084 ;
  END
 END q_d[177]
 PIN q_d[178]
  DIRECTION OUTPUT ;
  USE SIGNAL ;
  PORT
   LAYER M5 ;
   RECT 554.208 0.000 554.232 0.084 ;
  END
 END q_d[178]
 PIN q_d[179]
  DIRECTION OUTPUT ;
  USE SIGNAL ;
  PORT
   LAYER M5 ;
   RECT 554.400 0.000 554.424 0.084 ;
  END
 END q_d[179]
 PIN q_d[180]
  DIRECTION OUTPUT ;
  USE SIGNAL ;
  PORT
   LAYER M5 ;
   RECT 554.592 0.000 554.616 0.084 ;
  END
 END q_d[180]
 PIN q_d[181]
  DIRECTION OUTPUT ;
  USE SIGNAL ;
  PORT
   LAYER M5 ;
   RECT 554.784 0.000 554.808 0.084 ;
  END
 END q_d[181]
 PIN q_d[182]
  DIRECTION OUTPUT ;
  USE SIGNAL ;
  PORT
   LAYER M5 ;
   RECT 554.976 0.000 555.000 0.084 ;
  END
 END q_d[182]
 PIN q_d[183]
  DIRECTION OUTPUT ;
  USE SIGNAL ;
  PORT
   LAYER M5 ;
   RECT 555.168 0.000 555.192 0.084 ;
  END
 END q_d[183]
 PIN q_d[184]
  DIRECTION OUTPUT ;
  USE SIGNAL ;
  PORT
   LAYER M5 ;
   RECT 555.360 0.000 555.384 0.084 ;
  END
 END q_d[184]
 PIN q_d[185]
  DIRECTION OUTPUT ;
  USE SIGNAL ;
  PORT
   LAYER M5 ;
   RECT 555.552 0.000 555.576 0.084 ;
  END
 END q_d[185]
 PIN q_d[186]
  DIRECTION OUTPUT ;
  USE SIGNAL ;
  PORT
   LAYER M5 ;
   RECT 555.744 0.000 555.768 0.084 ;
  END
 END q_d[186]
 PIN q_d[187]
  DIRECTION OUTPUT ;
  USE SIGNAL ;
  PORT
   LAYER M5 ;
   RECT 555.936 0.000 555.960 0.084 ;
  END
 END q_d[187]
 PIN q_d[188]
  DIRECTION OUTPUT ;
  USE SIGNAL ;
  PORT
   LAYER M5 ;
   RECT 556.128 0.000 556.152 0.084 ;
  END
 END q_d[188]
 PIN q_d[189]
  DIRECTION OUTPUT ;
  USE SIGNAL ;
  PORT
   LAYER M5 ;
   RECT 556.320 0.000 556.344 0.084 ;
  END
 END q_d[189]
 PIN q_d[190]
  DIRECTION OUTPUT ;
  USE SIGNAL ;
  PORT
   LAYER M5 ;
   RECT 556.512 0.000 556.536 0.084 ;
  END
 END q_d[190]
 PIN q_d[191]
  DIRECTION OUTPUT ;
  USE SIGNAL ;
  PORT
   LAYER M5 ;
   RECT 556.704 0.000 556.728 0.084 ;
  END
 END q_d[191]
 PIN q_d[192]
  DIRECTION OUTPUT ;
  USE SIGNAL ;
  PORT
   LAYER M5 ;
   RECT 556.896 0.000 556.920 0.084 ;
  END
 END q_d[192]
 PIN q_d[193]
  DIRECTION OUTPUT ;
  USE SIGNAL ;
  PORT
   LAYER M5 ;
   RECT 557.088 0.000 557.112 0.084 ;
  END
 END q_d[193]
 PIN q_d[194]
  DIRECTION OUTPUT ;
  USE SIGNAL ;
  PORT
   LAYER M5 ;
   RECT 557.280 0.000 557.304 0.084 ;
  END
 END q_d[194]
 PIN q_d[195]
  DIRECTION OUTPUT ;
  USE SIGNAL ;
  PORT
   LAYER M5 ;
   RECT 557.472 0.000 557.496 0.084 ;
  END
 END q_d[195]
 PIN q_d[196]
  DIRECTION OUTPUT ;
  USE SIGNAL ;
  PORT
   LAYER M5 ;
   RECT 557.664 0.000 557.688 0.084 ;
  END
 END q_d[196]
 PIN q_d[197]
  DIRECTION OUTPUT ;
  USE SIGNAL ;
  PORT
   LAYER M5 ;
   RECT 557.856 0.000 557.880 0.084 ;
  END
 END q_d[197]
 PIN q_d[198]
  DIRECTION OUTPUT ;
  USE SIGNAL ;
  PORT
   LAYER M5 ;
   RECT 558.048 0.000 558.072 0.084 ;
  END
 END q_d[198]
 PIN q_d[199]
  DIRECTION OUTPUT ;
  USE SIGNAL ;
  PORT
   LAYER M5 ;
   RECT 558.240 0.000 558.264 0.084 ;
  END
 END q_d[199]
 PIN q_d[200]
  DIRECTION OUTPUT ;
  USE SIGNAL ;
  PORT
   LAYER M5 ;
   RECT 558.432 0.000 558.456 0.084 ;
  END
 END q_d[200]
 PIN q_d[201]
  DIRECTION OUTPUT ;
  USE SIGNAL ;
  PORT
   LAYER M5 ;
   RECT 558.624 0.000 558.648 0.084 ;
  END
 END q_d[201]
 PIN q_d[202]
  DIRECTION OUTPUT ;
  USE SIGNAL ;
  PORT
   LAYER M5 ;
   RECT 558.816 0.000 558.840 0.084 ;
  END
 END q_d[202]
 PIN q_d[203]
  DIRECTION OUTPUT ;
  USE SIGNAL ;
  PORT
   LAYER M5 ;
   RECT 559.008 0.000 559.032 0.084 ;
  END
 END q_d[203]
 PIN q_d[204]
  DIRECTION OUTPUT ;
  USE SIGNAL ;
  PORT
   LAYER M5 ;
   RECT 559.200 0.000 559.224 0.084 ;
  END
 END q_d[204]
 PIN q_d[205]
  DIRECTION OUTPUT ;
  USE SIGNAL ;
  PORT
   LAYER M5 ;
   RECT 559.392 0.000 559.416 0.084 ;
  END
 END q_d[205]
 PIN q_d[206]
  DIRECTION OUTPUT ;
  USE SIGNAL ;
  PORT
   LAYER M5 ;
   RECT 559.584 0.000 559.608 0.084 ;
  END
 END q_d[206]
 PIN q_d[207]
  DIRECTION OUTPUT ;
  USE SIGNAL ;
  PORT
   LAYER M5 ;
   RECT 559.776 0.000 559.800 0.084 ;
  END
 END q_d[207]
 PIN q_d[208]
  DIRECTION OUTPUT ;
  USE SIGNAL ;
  PORT
   LAYER M5 ;
   RECT 559.968 0.000 559.992 0.084 ;
  END
 END q_d[208]
 PIN q_d[209]
  DIRECTION OUTPUT ;
  USE SIGNAL ;
  PORT
   LAYER M5 ;
   RECT 560.160 0.000 560.184 0.084 ;
  END
 END q_d[209]
 PIN q_d[210]
  DIRECTION OUTPUT ;
  USE SIGNAL ;
  PORT
   LAYER M5 ;
   RECT 560.352 0.000 560.376 0.084 ;
  END
 END q_d[210]
 PIN q_d[211]
  DIRECTION OUTPUT ;
  USE SIGNAL ;
  PORT
   LAYER M5 ;
   RECT 560.544 0.000 560.568 0.084 ;
  END
 END q_d[211]
 PIN q_d[212]
  DIRECTION OUTPUT ;
  USE SIGNAL ;
  PORT
   LAYER M5 ;
   RECT 560.736 0.000 560.760 0.084 ;
  END
 END q_d[212]
 PIN q_d[213]
  DIRECTION OUTPUT ;
  USE SIGNAL ;
  PORT
   LAYER M5 ;
   RECT 560.928 0.000 560.952 0.084 ;
  END
 END q_d[213]
 PIN q_d[214]
  DIRECTION OUTPUT ;
  USE SIGNAL ;
  PORT
   LAYER M5 ;
   RECT 561.120 0.000 561.144 0.084 ;
  END
 END q_d[214]
 PIN q_d[215]
  DIRECTION OUTPUT ;
  USE SIGNAL ;
  PORT
   LAYER M5 ;
   RECT 561.312 0.000 561.336 0.084 ;
  END
 END q_d[215]
 PIN q_d[216]
  DIRECTION OUTPUT ;
  USE SIGNAL ;
  PORT
   LAYER M5 ;
   RECT 561.504 0.000 561.528 0.084 ;
  END
 END q_d[216]
 PIN q_d[217]
  DIRECTION OUTPUT ;
  USE SIGNAL ;
  PORT
   LAYER M5 ;
   RECT 561.696 0.000 561.720 0.084 ;
  END
 END q_d[217]
 PIN q_d[218]
  DIRECTION OUTPUT ;
  USE SIGNAL ;
  PORT
   LAYER M5 ;
   RECT 561.888 0.000 561.912 0.084 ;
  END
 END q_d[218]
 PIN q_d[219]
  DIRECTION OUTPUT ;
  USE SIGNAL ;
  PORT
   LAYER M5 ;
   RECT 562.080 0.000 562.104 0.084 ;
  END
 END q_d[219]
 PIN q_d[220]
  DIRECTION OUTPUT ;
  USE SIGNAL ;
  PORT
   LAYER M5 ;
   RECT 562.272 0.000 562.296 0.084 ;
  END
 END q_d[220]
 PIN q_d[221]
  DIRECTION OUTPUT ;
  USE SIGNAL ;
  PORT
   LAYER M5 ;
   RECT 562.464 0.000 562.488 0.084 ;
  END
 END q_d[221]
 PIN q_d[222]
  DIRECTION OUTPUT ;
  USE SIGNAL ;
  PORT
   LAYER M5 ;
   RECT 562.656 0.000 562.680 0.084 ;
  END
 END q_d[222]
 PIN q_d[223]
  DIRECTION OUTPUT ;
  USE SIGNAL ;
  PORT
   LAYER M5 ;
   RECT 562.848 0.000 562.872 0.084 ;
  END
 END q_d[223]
 PIN q_d[224]
  DIRECTION OUTPUT ;
  USE SIGNAL ;
  PORT
   LAYER M5 ;
   RECT 563.040 0.000 563.064 0.084 ;
  END
 END q_d[224]
 PIN q_d[225]
  DIRECTION OUTPUT ;
  USE SIGNAL ;
  PORT
   LAYER M5 ;
   RECT 563.232 0.000 563.256 0.084 ;
  END
 END q_d[225]
 PIN q_d[226]
  DIRECTION OUTPUT ;
  USE SIGNAL ;
  PORT
   LAYER M5 ;
   RECT 563.424 0.000 563.448 0.084 ;
  END
 END q_d[226]
 PIN q_d[227]
  DIRECTION OUTPUT ;
  USE SIGNAL ;
  PORT
   LAYER M5 ;
   RECT 563.616 0.000 563.640 0.084 ;
  END
 END q_d[227]
 PIN q_d[228]
  DIRECTION OUTPUT ;
  USE SIGNAL ;
  PORT
   LAYER M5 ;
   RECT 563.808 0.000 563.832 0.084 ;
  END
 END q_d[228]
 PIN q_d[229]
  DIRECTION OUTPUT ;
  USE SIGNAL ;
  PORT
   LAYER M5 ;
   RECT 564.000 0.000 564.024 0.084 ;
  END
 END q_d[229]
 PIN q_d[230]
  DIRECTION OUTPUT ;
  USE SIGNAL ;
  PORT
   LAYER M5 ;
   RECT 564.192 0.000 564.216 0.084 ;
  END
 END q_d[230]
 PIN q_d[231]
  DIRECTION OUTPUT ;
  USE SIGNAL ;
  PORT
   LAYER M5 ;
   RECT 564.384 0.000 564.408 0.084 ;
  END
 END q_d[231]
 PIN q_d[232]
  DIRECTION OUTPUT ;
  USE SIGNAL ;
  PORT
   LAYER M5 ;
   RECT 564.576 0.000 564.600 0.084 ;
  END
 END q_d[232]
 PIN q_d[233]
  DIRECTION OUTPUT ;
  USE SIGNAL ;
  PORT
   LAYER M5 ;
   RECT 564.768 0.000 564.792 0.084 ;
  END
 END q_d[233]
 PIN q_d[234]
  DIRECTION OUTPUT ;
  USE SIGNAL ;
  PORT
   LAYER M5 ;
   RECT 564.960 0.000 564.984 0.084 ;
  END
 END q_d[234]
 PIN q_d[235]
  DIRECTION OUTPUT ;
  USE SIGNAL ;
  PORT
   LAYER M5 ;
   RECT 565.152 0.000 565.176 0.084 ;
  END
 END q_d[235]
 PIN q_d[236]
  DIRECTION OUTPUT ;
  USE SIGNAL ;
  PORT
   LAYER M5 ;
   RECT 565.344 0.000 565.368 0.084 ;
  END
 END q_d[236]
 PIN q_d[237]
  DIRECTION OUTPUT ;
  USE SIGNAL ;
  PORT
   LAYER M5 ;
   RECT 565.536 0.000 565.560 0.084 ;
  END
 END q_d[237]
 PIN q_d[238]
  DIRECTION OUTPUT ;
  USE SIGNAL ;
  PORT
   LAYER M5 ;
   RECT 565.728 0.000 565.752 0.084 ;
  END
 END q_d[238]
 PIN q_d[239]
  DIRECTION OUTPUT ;
  USE SIGNAL ;
  PORT
   LAYER M5 ;
   RECT 565.920 0.000 565.944 0.084 ;
  END
 END q_d[239]
 PIN q_d[240]
  DIRECTION OUTPUT ;
  USE SIGNAL ;
  PORT
   LAYER M5 ;
   RECT 566.112 0.000 566.136 0.084 ;
  END
 END q_d[240]
 PIN q_d[241]
  DIRECTION OUTPUT ;
  USE SIGNAL ;
  PORT
   LAYER M5 ;
   RECT 566.304 0.000 566.328 0.084 ;
  END
 END q_d[241]
 PIN q_d[242]
  DIRECTION OUTPUT ;
  USE SIGNAL ;
  PORT
   LAYER M5 ;
   RECT 566.496 0.000 566.520 0.084 ;
  END
 END q_d[242]
 PIN q_d[243]
  DIRECTION OUTPUT ;
  USE SIGNAL ;
  PORT
   LAYER M5 ;
   RECT 566.688 0.000 566.712 0.084 ;
  END
 END q_d[243]
 PIN q_d[244]
  DIRECTION OUTPUT ;
  USE SIGNAL ;
  PORT
   LAYER M5 ;
   RECT 566.880 0.000 566.904 0.084 ;
  END
 END q_d[244]
 PIN q_d[245]
  DIRECTION OUTPUT ;
  USE SIGNAL ;
  PORT
   LAYER M5 ;
   RECT 567.072 0.000 567.096 0.084 ;
  END
 END q_d[245]
 PIN q_d[246]
  DIRECTION OUTPUT ;
  USE SIGNAL ;
  PORT
   LAYER M5 ;
   RECT 567.264 0.000 567.288 0.084 ;
  END
 END q_d[246]
 PIN q_d[247]
  DIRECTION OUTPUT ;
  USE SIGNAL ;
  PORT
   LAYER M5 ;
   RECT 567.456 0.000 567.480 0.084 ;
  END
 END q_d[247]
 PIN q_d[248]
  DIRECTION OUTPUT ;
  USE SIGNAL ;
  PORT
   LAYER M5 ;
   RECT 567.648 0.000 567.672 0.084 ;
  END
 END q_d[248]
 PIN q_d[249]
  DIRECTION OUTPUT ;
  USE SIGNAL ;
  PORT
   LAYER M5 ;
   RECT 567.840 0.000 567.864 0.084 ;
  END
 END q_d[249]
 PIN q_d[250]
  DIRECTION OUTPUT ;
  USE SIGNAL ;
  PORT
   LAYER M5 ;
   RECT 568.032 0.000 568.056 0.084 ;
  END
 END q_d[250]
 PIN q_d[251]
  DIRECTION OUTPUT ;
  USE SIGNAL ;
  PORT
   LAYER M5 ;
   RECT 568.224 0.000 568.248 0.084 ;
  END
 END q_d[251]
 PIN q_d[252]
  DIRECTION OUTPUT ;
  USE SIGNAL ;
  PORT
   LAYER M5 ;
   RECT 568.416 0.000 568.440 0.084 ;
  END
 END q_d[252]
 PIN q_d[253]
  DIRECTION OUTPUT ;
  USE SIGNAL ;
  PORT
   LAYER M5 ;
   RECT 568.608 0.000 568.632 0.084 ;
  END
 END q_d[253]
 PIN q_d[254]
  DIRECTION OUTPUT ;
  USE SIGNAL ;
  PORT
   LAYER M5 ;
   RECT 568.800 0.000 568.824 0.084 ;
  END
 END q_d[254]
 PIN q_d[255]
  DIRECTION OUTPUT ;
  USE SIGNAL ;
  PORT
   LAYER M5 ;
   RECT 568.992 0.000 569.016 0.084 ;
  END
 END q_d[255]
 PIN q_d[256]
  DIRECTION OUTPUT ;
  USE SIGNAL ;
  PORT
   LAYER M5 ;
   RECT 569.184 0.000 569.208 0.084 ;
  END
 END q_d[256]
 PIN q_d[257]
  DIRECTION OUTPUT ;
  USE SIGNAL ;
  PORT
   LAYER M5 ;
   RECT 569.376 0.000 569.400 0.084 ;
  END
 END q_d[257]
 PIN q_d[258]
  DIRECTION OUTPUT ;
  USE SIGNAL ;
  PORT
   LAYER M5 ;
   RECT 569.568 0.000 569.592 0.084 ;
  END
 END q_d[258]
 PIN q_d[259]
  DIRECTION OUTPUT ;
  USE SIGNAL ;
  PORT
   LAYER M5 ;
   RECT 569.760 0.000 569.784 0.084 ;
  END
 END q_d[259]
 PIN q_d[260]
  DIRECTION OUTPUT ;
  USE SIGNAL ;
  PORT
   LAYER M5 ;
   RECT 569.952 0.000 569.976 0.084 ;
  END
 END q_d[260]
 PIN q_d[261]
  DIRECTION OUTPUT ;
  USE SIGNAL ;
  PORT
   LAYER M5 ;
   RECT 570.144 0.000 570.168 0.084 ;
  END
 END q_d[261]
 PIN q_d[262]
  DIRECTION OUTPUT ;
  USE SIGNAL ;
  PORT
   LAYER M5 ;
   RECT 570.336 0.000 570.360 0.084 ;
  END
 END q_d[262]
 PIN q_d[263]
  DIRECTION OUTPUT ;
  USE SIGNAL ;
  PORT
   LAYER M5 ;
   RECT 570.528 0.000 570.552 0.084 ;
  END
 END q_d[263]
 PIN q_d[264]
  DIRECTION OUTPUT ;
  USE SIGNAL ;
  PORT
   LAYER M5 ;
   RECT 570.720 0.000 570.744 0.084 ;
  END
 END q_d[264]
 PIN q_d[265]
  DIRECTION OUTPUT ;
  USE SIGNAL ;
  PORT
   LAYER M5 ;
   RECT 570.912 0.000 570.936 0.084 ;
  END
 END q_d[265]
 PIN q_d[266]
  DIRECTION OUTPUT ;
  USE SIGNAL ;
  PORT
   LAYER M5 ;
   RECT 571.104 0.000 571.128 0.084 ;
  END
 END q_d[266]
 PIN q_d[267]
  DIRECTION OUTPUT ;
  USE SIGNAL ;
  PORT
   LAYER M5 ;
   RECT 571.296 0.000 571.320 0.084 ;
  END
 END q_d[267]
 PIN q_d[268]
  DIRECTION OUTPUT ;
  USE SIGNAL ;
  PORT
   LAYER M5 ;
   RECT 571.488 0.000 571.512 0.084 ;
  END
 END q_d[268]
 PIN q_d[269]
  DIRECTION OUTPUT ;
  USE SIGNAL ;
  PORT
   LAYER M5 ;
   RECT 571.680 0.000 571.704 0.084 ;
  END
 END q_d[269]
 PIN q_d[270]
  DIRECTION OUTPUT ;
  USE SIGNAL ;
  PORT
   LAYER M5 ;
   RECT 571.872 0.000 571.896 0.084 ;
  END
 END q_d[270]
 PIN q_d[271]
  DIRECTION OUTPUT ;
  USE SIGNAL ;
  PORT
   LAYER M5 ;
   RECT 572.064 0.000 572.088 0.084 ;
  END
 END q_d[271]
 PIN q_d[272]
  DIRECTION OUTPUT ;
  USE SIGNAL ;
  PORT
   LAYER M5 ;
   RECT 572.256 0.000 572.280 0.084 ;
  END
 END q_d[272]
 PIN q_d[273]
  DIRECTION OUTPUT ;
  USE SIGNAL ;
  PORT
   LAYER M5 ;
   RECT 572.448 0.000 572.472 0.084 ;
  END
 END q_d[273]
 PIN q_d[274]
  DIRECTION OUTPUT ;
  USE SIGNAL ;
  PORT
   LAYER M5 ;
   RECT 572.640 0.000 572.664 0.084 ;
  END
 END q_d[274]
 PIN q_d[275]
  DIRECTION OUTPUT ;
  USE SIGNAL ;
  PORT
   LAYER M5 ;
   RECT 572.832 0.000 572.856 0.084 ;
  END
 END q_d[275]
 PIN q_d[276]
  DIRECTION OUTPUT ;
  USE SIGNAL ;
  PORT
   LAYER M5 ;
   RECT 573.024 0.000 573.048 0.084 ;
  END
 END q_d[276]
 PIN q_d[277]
  DIRECTION OUTPUT ;
  USE SIGNAL ;
  PORT
   LAYER M5 ;
   RECT 573.216 0.000 573.240 0.084 ;
  END
 END q_d[277]
 PIN q_d[278]
  DIRECTION OUTPUT ;
  USE SIGNAL ;
  PORT
   LAYER M5 ;
   RECT 573.408 0.000 573.432 0.084 ;
  END
 END q_d[278]
 PIN q_d[279]
  DIRECTION OUTPUT ;
  USE SIGNAL ;
  PORT
   LAYER M5 ;
   RECT 573.600 0.000 573.624 0.084 ;
  END
 END q_d[279]
 PIN q_d[280]
  DIRECTION OUTPUT ;
  USE SIGNAL ;
  PORT
   LAYER M5 ;
   RECT 573.792 0.000 573.816 0.084 ;
  END
 END q_d[280]
 PIN q_d[281]
  DIRECTION OUTPUT ;
  USE SIGNAL ;
  PORT
   LAYER M5 ;
   RECT 573.984 0.000 574.008 0.084 ;
  END
 END q_d[281]
 PIN q_d[282]
  DIRECTION OUTPUT ;
  USE SIGNAL ;
  PORT
   LAYER M5 ;
   RECT 574.176 0.000 574.200 0.084 ;
  END
 END q_d[282]
 PIN q_d[283]
  DIRECTION OUTPUT ;
  USE SIGNAL ;
  PORT
   LAYER M5 ;
   RECT 574.368 0.000 574.392 0.084 ;
  END
 END q_d[283]
 PIN q_d[284]
  DIRECTION OUTPUT ;
  USE SIGNAL ;
  PORT
   LAYER M5 ;
   RECT 574.560 0.000 574.584 0.084 ;
  END
 END q_d[284]
 PIN q_d[285]
  DIRECTION OUTPUT ;
  USE SIGNAL ;
  PORT
   LAYER M5 ;
   RECT 574.752 0.000 574.776 0.084 ;
  END
 END q_d[285]
 PIN q_d[286]
  DIRECTION OUTPUT ;
  USE SIGNAL ;
  PORT
   LAYER M5 ;
   RECT 574.944 0.000 574.968 0.084 ;
  END
 END q_d[286]
 PIN q_d[287]
  DIRECTION OUTPUT ;
  USE SIGNAL ;
  PORT
   LAYER M5 ;
   RECT 575.136 0.000 575.160 0.084 ;
  END
 END q_d[287]
 PIN q_d[288]
  DIRECTION OUTPUT ;
  USE SIGNAL ;
  PORT
   LAYER M5 ;
   RECT 575.328 0.000 575.352 0.084 ;
  END
 END q_d[288]
 PIN q_d[289]
  DIRECTION OUTPUT ;
  USE SIGNAL ;
  PORT
   LAYER M5 ;
   RECT 575.520 0.000 575.544 0.084 ;
  END
 END q_d[289]
 PIN q_d[290]
  DIRECTION OUTPUT ;
  USE SIGNAL ;
  PORT
   LAYER M5 ;
   RECT 575.712 0.000 575.736 0.084 ;
  END
 END q_d[290]
 PIN q_d[291]
  DIRECTION OUTPUT ;
  USE SIGNAL ;
  PORT
   LAYER M5 ;
   RECT 575.904 0.000 575.928 0.084 ;
  END
 END q_d[291]
 PIN q_d[292]
  DIRECTION OUTPUT ;
  USE SIGNAL ;
  PORT
   LAYER M5 ;
   RECT 576.096 0.000 576.120 0.084 ;
  END
 END q_d[292]
 PIN q_d[293]
  DIRECTION OUTPUT ;
  USE SIGNAL ;
  PORT
   LAYER M5 ;
   RECT 576.288 0.000 576.312 0.084 ;
  END
 END q_d[293]
 PIN q_d[294]
  DIRECTION OUTPUT ;
  USE SIGNAL ;
  PORT
   LAYER M5 ;
   RECT 576.480 0.000 576.504 0.084 ;
  END
 END q_d[294]
 PIN q_d[295]
  DIRECTION OUTPUT ;
  USE SIGNAL ;
  PORT
   LAYER M5 ;
   RECT 576.672 0.000 576.696 0.084 ;
  END
 END q_d[295]
 PIN q_d[296]
  DIRECTION OUTPUT ;
  USE SIGNAL ;
  PORT
   LAYER M5 ;
   RECT 576.864 0.000 576.888 0.084 ;
  END
 END q_d[296]
 PIN q_d[297]
  DIRECTION OUTPUT ;
  USE SIGNAL ;
  PORT
   LAYER M5 ;
   RECT 577.056 0.000 577.080 0.084 ;
  END
 END q_d[297]
 PIN q_d[298]
  DIRECTION OUTPUT ;
  USE SIGNAL ;
  PORT
   LAYER M5 ;
   RECT 577.248 0.000 577.272 0.084 ;
  END
 END q_d[298]
 PIN q_d[299]
  DIRECTION OUTPUT ;
  USE SIGNAL ;
  PORT
   LAYER M5 ;
   RECT 577.440 0.000 577.464 0.084 ;
  END
 END q_d[299]
 PIN q_d[300]
  DIRECTION OUTPUT ;
  USE SIGNAL ;
  PORT
   LAYER M5 ;
   RECT 577.632 0.000 577.656 0.084 ;
  END
 END q_d[300]
 PIN q_d[301]
  DIRECTION OUTPUT ;
  USE SIGNAL ;
  PORT
   LAYER M5 ;
   RECT 577.824 0.000 577.848 0.084 ;
  END
 END q_d[301]
 PIN q_d[302]
  DIRECTION OUTPUT ;
  USE SIGNAL ;
  PORT
   LAYER M5 ;
   RECT 578.016 0.000 578.040 0.084 ;
  END
 END q_d[302]
 PIN q_d[303]
  DIRECTION OUTPUT ;
  USE SIGNAL ;
  PORT
   LAYER M5 ;
   RECT 578.208 0.000 578.232 0.084 ;
  END
 END q_d[303]
 PIN q_d[304]
  DIRECTION OUTPUT ;
  USE SIGNAL ;
  PORT
   LAYER M5 ;
   RECT 578.400 0.000 578.424 0.084 ;
  END
 END q_d[304]
 PIN q_d[305]
  DIRECTION OUTPUT ;
  USE SIGNAL ;
  PORT
   LAYER M5 ;
   RECT 578.592 0.000 578.616 0.084 ;
  END
 END q_d[305]
 PIN q_d[306]
  DIRECTION OUTPUT ;
  USE SIGNAL ;
  PORT
   LAYER M5 ;
   RECT 578.784 0.000 578.808 0.084 ;
  END
 END q_d[306]
 PIN q_d[307]
  DIRECTION OUTPUT ;
  USE SIGNAL ;
  PORT
   LAYER M5 ;
   RECT 578.976 0.000 579.000 0.084 ;
  END
 END q_d[307]
 PIN q_d[308]
  DIRECTION OUTPUT ;
  USE SIGNAL ;
  PORT
   LAYER M5 ;
   RECT 579.168 0.000 579.192 0.084 ;
  END
 END q_d[308]
 PIN q_d[309]
  DIRECTION OUTPUT ;
  USE SIGNAL ;
  PORT
   LAYER M5 ;
   RECT 579.360 0.000 579.384 0.084 ;
  END
 END q_d[309]
 PIN q_d[310]
  DIRECTION OUTPUT ;
  USE SIGNAL ;
  PORT
   LAYER M5 ;
   RECT 579.552 0.000 579.576 0.084 ;
  END
 END q_d[310]
 PIN q_d[311]
  DIRECTION OUTPUT ;
  USE SIGNAL ;
  PORT
   LAYER M5 ;
   RECT 579.744 0.000 579.768 0.084 ;
  END
 END q_d[311]
 PIN q_d[312]
  DIRECTION OUTPUT ;
  USE SIGNAL ;
  PORT
   LAYER M5 ;
   RECT 579.936 0.000 579.960 0.084 ;
  END
 END q_d[312]
 PIN q_d[313]
  DIRECTION OUTPUT ;
  USE SIGNAL ;
  PORT
   LAYER M5 ;
   RECT 580.128 0.000 580.152 0.084 ;
  END
 END q_d[313]
 PIN q_d[314]
  DIRECTION OUTPUT ;
  USE SIGNAL ;
  PORT
   LAYER M5 ;
   RECT 580.320 0.000 580.344 0.084 ;
  END
 END q_d[314]
 PIN q_d[315]
  DIRECTION OUTPUT ;
  USE SIGNAL ;
  PORT
   LAYER M5 ;
   RECT 580.512 0.000 580.536 0.084 ;
  END
 END q_d[315]
 PIN q_d[316]
  DIRECTION OUTPUT ;
  USE SIGNAL ;
  PORT
   LAYER M5 ;
   RECT 580.704 0.000 580.728 0.084 ;
  END
 END q_d[316]
 PIN q_d[317]
  DIRECTION OUTPUT ;
  USE SIGNAL ;
  PORT
   LAYER M5 ;
   RECT 580.896 0.000 580.920 0.084 ;
  END
 END q_d[317]
 PIN q_d[318]
  DIRECTION OUTPUT ;
  USE SIGNAL ;
  PORT
   LAYER M5 ;
   RECT 581.088 0.000 581.112 0.084 ;
  END
 END q_d[318]
 PIN q_d[319]
  DIRECTION OUTPUT ;
  USE SIGNAL ;
  PORT
   LAYER M5 ;
   RECT 581.280 0.000 581.304 0.084 ;
  END
 END q_d[319]
 PIN q_d[320]
  DIRECTION OUTPUT ;
  USE SIGNAL ;
  PORT
   LAYER M5 ;
   RECT 581.472 0.000 581.496 0.084 ;
  END
 END q_d[320]
 PIN q_d[321]
  DIRECTION OUTPUT ;
  USE SIGNAL ;
  PORT
   LAYER M5 ;
   RECT 581.664 0.000 581.688 0.084 ;
  END
 END q_d[321]
 PIN q_d[322]
  DIRECTION OUTPUT ;
  USE SIGNAL ;
  PORT
   LAYER M5 ;
   RECT 581.856 0.000 581.880 0.084 ;
  END
 END q_d[322]
 PIN q_d[323]
  DIRECTION OUTPUT ;
  USE SIGNAL ;
  PORT
   LAYER M5 ;
   RECT 582.048 0.000 582.072 0.084 ;
  END
 END q_d[323]
 PIN q_d[324]
  DIRECTION OUTPUT ;
  USE SIGNAL ;
  PORT
   LAYER M5 ;
   RECT 582.240 0.000 582.264 0.084 ;
  END
 END q_d[324]
 PIN q_d[325]
  DIRECTION OUTPUT ;
  USE SIGNAL ;
  PORT
   LAYER M5 ;
   RECT 582.432 0.000 582.456 0.084 ;
  END
 END q_d[325]
 PIN q_d[326]
  DIRECTION OUTPUT ;
  USE SIGNAL ;
  PORT
   LAYER M5 ;
   RECT 582.624 0.000 582.648 0.084 ;
  END
 END q_d[326]
 PIN q_d[327]
  DIRECTION OUTPUT ;
  USE SIGNAL ;
  PORT
   LAYER M5 ;
   RECT 582.816 0.000 582.840 0.084 ;
  END
 END q_d[327]
 PIN q_d[328]
  DIRECTION OUTPUT ;
  USE SIGNAL ;
  PORT
   LAYER M5 ;
   RECT 583.008 0.000 583.032 0.084 ;
  END
 END q_d[328]
 PIN q_d[329]
  DIRECTION OUTPUT ;
  USE SIGNAL ;
  PORT
   LAYER M5 ;
   RECT 583.200 0.000 583.224 0.084 ;
  END
 END q_d[329]
 PIN q_d[330]
  DIRECTION OUTPUT ;
  USE SIGNAL ;
  PORT
   LAYER M5 ;
   RECT 583.392 0.000 583.416 0.084 ;
  END
 END q_d[330]
 PIN q_d[331]
  DIRECTION OUTPUT ;
  USE SIGNAL ;
  PORT
   LAYER M5 ;
   RECT 583.584 0.000 583.608 0.084 ;
  END
 END q_d[331]
 PIN q_d[332]
  DIRECTION OUTPUT ;
  USE SIGNAL ;
  PORT
   LAYER M5 ;
   RECT 583.776 0.000 583.800 0.084 ;
  END
 END q_d[332]
 PIN q_d[333]
  DIRECTION OUTPUT ;
  USE SIGNAL ;
  PORT
   LAYER M5 ;
   RECT 583.968 0.000 583.992 0.084 ;
  END
 END q_d[333]
 PIN q_d[334]
  DIRECTION OUTPUT ;
  USE SIGNAL ;
  PORT
   LAYER M5 ;
   RECT 584.160 0.000 584.184 0.084 ;
  END
 END q_d[334]
 PIN q_d[335]
  DIRECTION OUTPUT ;
  USE SIGNAL ;
  PORT
   LAYER M5 ;
   RECT 584.352 0.000 584.376 0.084 ;
  END
 END q_d[335]
 PIN q_d[336]
  DIRECTION OUTPUT ;
  USE SIGNAL ;
  PORT
   LAYER M5 ;
   RECT 584.544 0.000 584.568 0.084 ;
  END
 END q_d[336]
 PIN q_d[337]
  DIRECTION OUTPUT ;
  USE SIGNAL ;
  PORT
   LAYER M5 ;
   RECT 584.736 0.000 584.760 0.084 ;
  END
 END q_d[337]
 PIN q_d[338]
  DIRECTION OUTPUT ;
  USE SIGNAL ;
  PORT
   LAYER M5 ;
   RECT 584.928 0.000 584.952 0.084 ;
  END
 END q_d[338]
 PIN q_d[339]
  DIRECTION OUTPUT ;
  USE SIGNAL ;
  PORT
   LAYER M5 ;
   RECT 585.120 0.000 585.144 0.084 ;
  END
 END q_d[339]
 PIN q_d[340]
  DIRECTION OUTPUT ;
  USE SIGNAL ;
  PORT
   LAYER M5 ;
   RECT 585.312 0.000 585.336 0.084 ;
  END
 END q_d[340]
 PIN q_d[341]
  DIRECTION OUTPUT ;
  USE SIGNAL ;
  PORT
   LAYER M5 ;
   RECT 585.504 0.000 585.528 0.084 ;
  END
 END q_d[341]
 PIN q_d[342]
  DIRECTION OUTPUT ;
  USE SIGNAL ;
  PORT
   LAYER M5 ;
   RECT 585.696 0.000 585.720 0.084 ;
  END
 END q_d[342]
 PIN q_d[343]
  DIRECTION OUTPUT ;
  USE SIGNAL ;
  PORT
   LAYER M5 ;
   RECT 585.888 0.000 585.912 0.084 ;
  END
 END q_d[343]
 PIN q_d[344]
  DIRECTION OUTPUT ;
  USE SIGNAL ;
  PORT
   LAYER M5 ;
   RECT 586.080 0.000 586.104 0.084 ;
  END
 END q_d[344]
 PIN q_d[345]
  DIRECTION OUTPUT ;
  USE SIGNAL ;
  PORT
   LAYER M5 ;
   RECT 586.272 0.000 586.296 0.084 ;
  END
 END q_d[345]
 PIN q_d[346]
  DIRECTION OUTPUT ;
  USE SIGNAL ;
  PORT
   LAYER M5 ;
   RECT 586.464 0.000 586.488 0.084 ;
  END
 END q_d[346]
 PIN q_d[347]
  DIRECTION OUTPUT ;
  USE SIGNAL ;
  PORT
   LAYER M5 ;
   RECT 586.656 0.000 586.680 0.084 ;
  END
 END q_d[347]
 PIN q_d[348]
  DIRECTION OUTPUT ;
  USE SIGNAL ;
  PORT
   LAYER M5 ;
   RECT 586.848 0.000 586.872 0.084 ;
  END
 END q_d[348]
 PIN q_d[349]
  DIRECTION OUTPUT ;
  USE SIGNAL ;
  PORT
   LAYER M5 ;
   RECT 587.040 0.000 587.064 0.084 ;
  END
 END q_d[349]
 PIN q_d[350]
  DIRECTION OUTPUT ;
  USE SIGNAL ;
  PORT
   LAYER M5 ;
   RECT 587.232 0.000 587.256 0.084 ;
  END
 END q_d[350]
 PIN q_d[351]
  DIRECTION OUTPUT ;
  USE SIGNAL ;
  PORT
   LAYER M5 ;
   RECT 587.424 0.000 587.448 0.084 ;
  END
 END q_d[351]
 PIN q_d[352]
  DIRECTION OUTPUT ;
  USE SIGNAL ;
  PORT
   LAYER M5 ;
   RECT 587.616 0.000 587.640 0.084 ;
  END
 END q_d[352]
 PIN q_d[353]
  DIRECTION OUTPUT ;
  USE SIGNAL ;
  PORT
   LAYER M5 ;
   RECT 587.808 0.000 587.832 0.084 ;
  END
 END q_d[353]
 PIN q_d[354]
  DIRECTION OUTPUT ;
  USE SIGNAL ;
  PORT
   LAYER M5 ;
   RECT 588.000 0.000 588.024 0.084 ;
  END
 END q_d[354]
 PIN q_d[355]
  DIRECTION OUTPUT ;
  USE SIGNAL ;
  PORT
   LAYER M5 ;
   RECT 588.192 0.000 588.216 0.084 ;
  END
 END q_d[355]
 PIN q_d[356]
  DIRECTION OUTPUT ;
  USE SIGNAL ;
  PORT
   LAYER M5 ;
   RECT 588.384 0.000 588.408 0.084 ;
  END
 END q_d[356]
 PIN q_d[357]
  DIRECTION OUTPUT ;
  USE SIGNAL ;
  PORT
   LAYER M5 ;
   RECT 588.576 0.000 588.600 0.084 ;
  END
 END q_d[357]
 PIN q_d[358]
  DIRECTION OUTPUT ;
  USE SIGNAL ;
  PORT
   LAYER M5 ;
   RECT 588.768 0.000 588.792 0.084 ;
  END
 END q_d[358]
 PIN q_d[359]
  DIRECTION OUTPUT ;
  USE SIGNAL ;
  PORT
   LAYER M5 ;
   RECT 588.960 0.000 588.984 0.084 ;
  END
 END q_d[359]
 PIN q_d[360]
  DIRECTION OUTPUT ;
  USE SIGNAL ;
  PORT
   LAYER M5 ;
   RECT 589.152 0.000 589.176 0.084 ;
  END
 END q_d[360]
 PIN q_d[361]
  DIRECTION OUTPUT ;
  USE SIGNAL ;
  PORT
   LAYER M5 ;
   RECT 589.344 0.000 589.368 0.084 ;
  END
 END q_d[361]
 PIN q_d[362]
  DIRECTION OUTPUT ;
  USE SIGNAL ;
  PORT
   LAYER M5 ;
   RECT 589.536 0.000 589.560 0.084 ;
  END
 END q_d[362]
 PIN q_d[363]
  DIRECTION OUTPUT ;
  USE SIGNAL ;
  PORT
   LAYER M5 ;
   RECT 589.728 0.000 589.752 0.084 ;
  END
 END q_d[363]
 PIN q_d[364]
  DIRECTION OUTPUT ;
  USE SIGNAL ;
  PORT
   LAYER M5 ;
   RECT 589.920 0.000 589.944 0.084 ;
  END
 END q_d[364]
 PIN q_d[365]
  DIRECTION OUTPUT ;
  USE SIGNAL ;
  PORT
   LAYER M5 ;
   RECT 590.112 0.000 590.136 0.084 ;
  END
 END q_d[365]
 PIN q_d[366]
  DIRECTION OUTPUT ;
  USE SIGNAL ;
  PORT
   LAYER M5 ;
   RECT 590.304 0.000 590.328 0.084 ;
  END
 END q_d[366]
 PIN q_d[367]
  DIRECTION OUTPUT ;
  USE SIGNAL ;
  PORT
   LAYER M5 ;
   RECT 590.496 0.000 590.520 0.084 ;
  END
 END q_d[367]
 PIN q_d[368]
  DIRECTION OUTPUT ;
  USE SIGNAL ;
  PORT
   LAYER M5 ;
   RECT 590.688 0.000 590.712 0.084 ;
  END
 END q_d[368]
 PIN q_d[369]
  DIRECTION OUTPUT ;
  USE SIGNAL ;
  PORT
   LAYER M5 ;
   RECT 590.880 0.000 590.904 0.084 ;
  END
 END q_d[369]
 PIN q_d[370]
  DIRECTION OUTPUT ;
  USE SIGNAL ;
  PORT
   LAYER M5 ;
   RECT 591.072 0.000 591.096 0.084 ;
  END
 END q_d[370]
 PIN q_d[371]
  DIRECTION OUTPUT ;
  USE SIGNAL ;
  PORT
   LAYER M5 ;
   RECT 591.264 0.000 591.288 0.084 ;
  END
 END q_d[371]
 PIN q_d[372]
  DIRECTION OUTPUT ;
  USE SIGNAL ;
  PORT
   LAYER M5 ;
   RECT 591.456 0.000 591.480 0.084 ;
  END
 END q_d[372]
 PIN q_d[373]
  DIRECTION OUTPUT ;
  USE SIGNAL ;
  PORT
   LAYER M5 ;
   RECT 591.648 0.000 591.672 0.084 ;
  END
 END q_d[373]
 PIN q_d[374]
  DIRECTION OUTPUT ;
  USE SIGNAL ;
  PORT
   LAYER M5 ;
   RECT 591.840 0.000 591.864 0.084 ;
  END
 END q_d[374]
 PIN q_d[375]
  DIRECTION OUTPUT ;
  USE SIGNAL ;
  PORT
   LAYER M5 ;
   RECT 592.032 0.000 592.056 0.084 ;
  END
 END q_d[375]
 PIN q_d[376]
  DIRECTION OUTPUT ;
  USE SIGNAL ;
  PORT
   LAYER M5 ;
   RECT 592.224 0.000 592.248 0.084 ;
  END
 END q_d[376]
 PIN q_d[377]
  DIRECTION OUTPUT ;
  USE SIGNAL ;
  PORT
   LAYER M5 ;
   RECT 592.416 0.000 592.440 0.084 ;
  END
 END q_d[377]
 PIN q_d[378]
  DIRECTION OUTPUT ;
  USE SIGNAL ;
  PORT
   LAYER M5 ;
   RECT 592.608 0.000 592.632 0.084 ;
  END
 END q_d[378]
 PIN q_d[379]
  DIRECTION OUTPUT ;
  USE SIGNAL ;
  PORT
   LAYER M5 ;
   RECT 592.800 0.000 592.824 0.084 ;
  END
 END q_d[379]
 PIN q_d[380]
  DIRECTION OUTPUT ;
  USE SIGNAL ;
  PORT
   LAYER M5 ;
   RECT 592.992 0.000 593.016 0.084 ;
  END
 END q_d[380]
 PIN q_d[381]
  DIRECTION OUTPUT ;
  USE SIGNAL ;
  PORT
   LAYER M5 ;
   RECT 593.184 0.000 593.208 0.084 ;
  END
 END q_d[381]
 PIN q_d[382]
  DIRECTION OUTPUT ;
  USE SIGNAL ;
  PORT
   LAYER M5 ;
   RECT 593.376 0.000 593.400 0.084 ;
  END
 END q_d[382]
 PIN q_d[383]
  DIRECTION OUTPUT ;
  USE SIGNAL ;
  PORT
   LAYER M5 ;
   RECT 593.568 0.000 593.592 0.084 ;
  END
 END q_d[383]
 PIN q_d[384]
  DIRECTION OUTPUT ;
  USE SIGNAL ;
  PORT
   LAYER M5 ;
   RECT 593.760 0.000 593.784 0.084 ;
  END
 END q_d[384]
 PIN q_d[385]
  DIRECTION OUTPUT ;
  USE SIGNAL ;
  PORT
   LAYER M5 ;
   RECT 593.952 0.000 593.976 0.084 ;
  END
 END q_d[385]
 PIN q_d[386]
  DIRECTION OUTPUT ;
  USE SIGNAL ;
  PORT
   LAYER M5 ;
   RECT 594.144 0.000 594.168 0.084 ;
  END
 END q_d[386]
 PIN q_d[387]
  DIRECTION OUTPUT ;
  USE SIGNAL ;
  PORT
   LAYER M5 ;
   RECT 594.336 0.000 594.360 0.084 ;
  END
 END q_d[387]
 PIN q_d[388]
  DIRECTION OUTPUT ;
  USE SIGNAL ;
  PORT
   LAYER M5 ;
   RECT 594.528 0.000 594.552 0.084 ;
  END
 END q_d[388]
 PIN q_d[389]
  DIRECTION OUTPUT ;
  USE SIGNAL ;
  PORT
   LAYER M5 ;
   RECT 594.720 0.000 594.744 0.084 ;
  END
 END q_d[389]
 PIN q_d[390]
  DIRECTION OUTPUT ;
  USE SIGNAL ;
  PORT
   LAYER M5 ;
   RECT 594.912 0.000 594.936 0.084 ;
  END
 END q_d[390]
 PIN q_d[391]
  DIRECTION OUTPUT ;
  USE SIGNAL ;
  PORT
   LAYER M5 ;
   RECT 595.104 0.000 595.128 0.084 ;
  END
 END q_d[391]
 PIN q_d[392]
  DIRECTION OUTPUT ;
  USE SIGNAL ;
  PORT
   LAYER M5 ;
   RECT 595.296 0.000 595.320 0.084 ;
  END
 END q_d[392]
 PIN q_d[393]
  DIRECTION OUTPUT ;
  USE SIGNAL ;
  PORT
   LAYER M5 ;
   RECT 595.488 0.000 595.512 0.084 ;
  END
 END q_d[393]
 PIN q_d[394]
  DIRECTION OUTPUT ;
  USE SIGNAL ;
  PORT
   LAYER M5 ;
   RECT 595.680 0.000 595.704 0.084 ;
  END
 END q_d[394]
 PIN q_d[395]
  DIRECTION OUTPUT ;
  USE SIGNAL ;
  PORT
   LAYER M5 ;
   RECT 595.872 0.000 595.896 0.084 ;
  END
 END q_d[395]
 PIN q_d[396]
  DIRECTION OUTPUT ;
  USE SIGNAL ;
  PORT
   LAYER M5 ;
   RECT 596.064 0.000 596.088 0.084 ;
  END
 END q_d[396]
 PIN q_d[397]
  DIRECTION OUTPUT ;
  USE SIGNAL ;
  PORT
   LAYER M5 ;
   RECT 596.256 0.000 596.280 0.084 ;
  END
 END q_d[397]
 PIN q_d[398]
  DIRECTION OUTPUT ;
  USE SIGNAL ;
  PORT
   LAYER M5 ;
   RECT 596.448 0.000 596.472 0.084 ;
  END
 END q_d[398]
 PIN q_d[399]
  DIRECTION OUTPUT ;
  USE SIGNAL ;
  PORT
   LAYER M5 ;
   RECT 596.640 0.000 596.664 0.084 ;
  END
 END q_d[399]
 PIN q_d[400]
  DIRECTION OUTPUT ;
  USE SIGNAL ;
  PORT
   LAYER M5 ;
   RECT 596.832 0.000 596.856 0.084 ;
  END
 END q_d[400]
 PIN q_d[401]
  DIRECTION OUTPUT ;
  USE SIGNAL ;
  PORT
   LAYER M5 ;
   RECT 597.024 0.000 597.048 0.084 ;
  END
 END q_d[401]
 PIN q_d[402]
  DIRECTION OUTPUT ;
  USE SIGNAL ;
  PORT
   LAYER M5 ;
   RECT 597.216 0.000 597.240 0.084 ;
  END
 END q_d[402]
 PIN q_d[403]
  DIRECTION OUTPUT ;
  USE SIGNAL ;
  PORT
   LAYER M5 ;
   RECT 597.408 0.000 597.432 0.084 ;
  END
 END q_d[403]
 PIN q_d[404]
  DIRECTION OUTPUT ;
  USE SIGNAL ;
  PORT
   LAYER M5 ;
   RECT 597.600 0.000 597.624 0.084 ;
  END
 END q_d[404]
 PIN q_d[405]
  DIRECTION OUTPUT ;
  USE SIGNAL ;
  PORT
   LAYER M5 ;
   RECT 597.792 0.000 597.816 0.084 ;
  END
 END q_d[405]
 PIN q_d[406]
  DIRECTION OUTPUT ;
  USE SIGNAL ;
  PORT
   LAYER M5 ;
   RECT 597.984 0.000 598.008 0.084 ;
  END
 END q_d[406]
 PIN q_d[407]
  DIRECTION OUTPUT ;
  USE SIGNAL ;
  PORT
   LAYER M5 ;
   RECT 598.176 0.000 598.200 0.084 ;
  END
 END q_d[407]
 PIN q_d[408]
  DIRECTION OUTPUT ;
  USE SIGNAL ;
  PORT
   LAYER M5 ;
   RECT 598.368 0.000 598.392 0.084 ;
  END
 END q_d[408]
 PIN q_d[409]
  DIRECTION OUTPUT ;
  USE SIGNAL ;
  PORT
   LAYER M5 ;
   RECT 598.560 0.000 598.584 0.084 ;
  END
 END q_d[409]
 PIN q_d[410]
  DIRECTION OUTPUT ;
  USE SIGNAL ;
  PORT
   LAYER M5 ;
   RECT 598.752 0.000 598.776 0.084 ;
  END
 END q_d[410]
 PIN q_d[411]
  DIRECTION OUTPUT ;
  USE SIGNAL ;
  PORT
   LAYER M5 ;
   RECT 598.944 0.000 598.968 0.084 ;
  END
 END q_d[411]
 PIN q_d[412]
  DIRECTION OUTPUT ;
  USE SIGNAL ;
  PORT
   LAYER M5 ;
   RECT 599.136 0.000 599.160 0.084 ;
  END
 END q_d[412]
 PIN q_d[413]
  DIRECTION OUTPUT ;
  USE SIGNAL ;
  PORT
   LAYER M5 ;
   RECT 599.328 0.000 599.352 0.084 ;
  END
 END q_d[413]
 PIN q_d[414]
  DIRECTION OUTPUT ;
  USE SIGNAL ;
  PORT
   LAYER M5 ;
   RECT 599.520 0.000 599.544 0.084 ;
  END
 END q_d[414]
 PIN q_d[415]
  DIRECTION OUTPUT ;
  USE SIGNAL ;
  PORT
   LAYER M5 ;
   RECT 599.712 0.000 599.736 0.084 ;
  END
 END q_d[415]
 PIN q_d[416]
  DIRECTION OUTPUT ;
  USE SIGNAL ;
  PORT
   LAYER M5 ;
   RECT 599.904 0.000 599.928 0.084 ;
  END
 END q_d[416]
 PIN q_d[417]
  DIRECTION OUTPUT ;
  USE SIGNAL ;
  PORT
   LAYER M5 ;
   RECT 600.096 0.000 600.120 0.084 ;
  END
 END q_d[417]
 PIN q_d[418]
  DIRECTION OUTPUT ;
  USE SIGNAL ;
  PORT
   LAYER M5 ;
   RECT 600.288 0.000 600.312 0.084 ;
  END
 END q_d[418]
 PIN q_d[419]
  DIRECTION OUTPUT ;
  USE SIGNAL ;
  PORT
   LAYER M5 ;
   RECT 600.480 0.000 600.504 0.084 ;
  END
 END q_d[419]
 PIN q_d[420]
  DIRECTION OUTPUT ;
  USE SIGNAL ;
  PORT
   LAYER M5 ;
   RECT 600.672 0.000 600.696 0.084 ;
  END
 END q_d[420]
 PIN q_d[421]
  DIRECTION OUTPUT ;
  USE SIGNAL ;
  PORT
   LAYER M5 ;
   RECT 600.864 0.000 600.888 0.084 ;
  END
 END q_d[421]
 PIN q_d[422]
  DIRECTION OUTPUT ;
  USE SIGNAL ;
  PORT
   LAYER M5 ;
   RECT 601.056 0.000 601.080 0.084 ;
  END
 END q_d[422]
 PIN q_d[423]
  DIRECTION OUTPUT ;
  USE SIGNAL ;
  PORT
   LAYER M5 ;
   RECT 601.248 0.000 601.272 0.084 ;
  END
 END q_d[423]
 PIN q_d[424]
  DIRECTION OUTPUT ;
  USE SIGNAL ;
  PORT
   LAYER M5 ;
   RECT 601.440 0.000 601.464 0.084 ;
  END
 END q_d[424]
 PIN q_d[425]
  DIRECTION OUTPUT ;
  USE SIGNAL ;
  PORT
   LAYER M5 ;
   RECT 601.632 0.000 601.656 0.084 ;
  END
 END q_d[425]
 PIN q_d[426]
  DIRECTION OUTPUT ;
  USE SIGNAL ;
  PORT
   LAYER M5 ;
   RECT 601.824 0.000 601.848 0.084 ;
  END
 END q_d[426]
 PIN q_d[427]
  DIRECTION OUTPUT ;
  USE SIGNAL ;
  PORT
   LAYER M5 ;
   RECT 602.016 0.000 602.040 0.084 ;
  END
 END q_d[427]
 PIN q_d[428]
  DIRECTION OUTPUT ;
  USE SIGNAL ;
  PORT
   LAYER M5 ;
   RECT 602.208 0.000 602.232 0.084 ;
  END
 END q_d[428]
 PIN q_d[429]
  DIRECTION OUTPUT ;
  USE SIGNAL ;
  PORT
   LAYER M5 ;
   RECT 602.400 0.000 602.424 0.084 ;
  END
 END q_d[429]
 PIN q_d[430]
  DIRECTION OUTPUT ;
  USE SIGNAL ;
  PORT
   LAYER M5 ;
   RECT 602.592 0.000 602.616 0.084 ;
  END
 END q_d[430]
 PIN q_d[431]
  DIRECTION OUTPUT ;
  USE SIGNAL ;
  PORT
   LAYER M5 ;
   RECT 602.784 0.000 602.808 0.084 ;
  END
 END q_d[431]
 PIN q_d[432]
  DIRECTION OUTPUT ;
  USE SIGNAL ;
  PORT
   LAYER M5 ;
   RECT 602.976 0.000 603.000 0.084 ;
  END
 END q_d[432]
 PIN q_d[433]
  DIRECTION OUTPUT ;
  USE SIGNAL ;
  PORT
   LAYER M5 ;
   RECT 603.168 0.000 603.192 0.084 ;
  END
 END q_d[433]
 PIN q_d[434]
  DIRECTION OUTPUT ;
  USE SIGNAL ;
  PORT
   LAYER M5 ;
   RECT 603.360 0.000 603.384 0.084 ;
  END
 END q_d[434]
 PIN q_d[435]
  DIRECTION OUTPUT ;
  USE SIGNAL ;
  PORT
   LAYER M5 ;
   RECT 603.552 0.000 603.576 0.084 ;
  END
 END q_d[435]
 PIN q_d[436]
  DIRECTION OUTPUT ;
  USE SIGNAL ;
  PORT
   LAYER M5 ;
   RECT 603.744 0.000 603.768 0.084 ;
  END
 END q_d[436]
 PIN q_d[437]
  DIRECTION OUTPUT ;
  USE SIGNAL ;
  PORT
   LAYER M5 ;
   RECT 603.936 0.000 603.960 0.084 ;
  END
 END q_d[437]
 PIN q_d[438]
  DIRECTION OUTPUT ;
  USE SIGNAL ;
  PORT
   LAYER M5 ;
   RECT 604.128 0.000 604.152 0.084 ;
  END
 END q_d[438]
 PIN q_d[439]
  DIRECTION OUTPUT ;
  USE SIGNAL ;
  PORT
   LAYER M5 ;
   RECT 604.320 0.000 604.344 0.084 ;
  END
 END q_d[439]
 PIN q_d[440]
  DIRECTION OUTPUT ;
  USE SIGNAL ;
  PORT
   LAYER M5 ;
   RECT 604.512 0.000 604.536 0.084 ;
  END
 END q_d[440]
 PIN q_d[441]
  DIRECTION OUTPUT ;
  USE SIGNAL ;
  PORT
   LAYER M5 ;
   RECT 604.704 0.000 604.728 0.084 ;
  END
 END q_d[441]
 PIN q_d[442]
  DIRECTION OUTPUT ;
  USE SIGNAL ;
  PORT
   LAYER M5 ;
   RECT 604.896 0.000 604.920 0.084 ;
  END
 END q_d[442]
 PIN q_d[443]
  DIRECTION OUTPUT ;
  USE SIGNAL ;
  PORT
   LAYER M5 ;
   RECT 605.088 0.000 605.112 0.084 ;
  END
 END q_d[443]
 PIN q_d[444]
  DIRECTION OUTPUT ;
  USE SIGNAL ;
  PORT
   LAYER M5 ;
   RECT 605.280 0.000 605.304 0.084 ;
  END
 END q_d[444]
 PIN q_d[445]
  DIRECTION OUTPUT ;
  USE SIGNAL ;
  PORT
   LAYER M5 ;
   RECT 605.472 0.000 605.496 0.084 ;
  END
 END q_d[445]
 PIN q_d[446]
  DIRECTION OUTPUT ;
  USE SIGNAL ;
  PORT
   LAYER M5 ;
   RECT 605.664 0.000 605.688 0.084 ;
  END
 END q_d[446]
 PIN q_d[447]
  DIRECTION OUTPUT ;
  USE SIGNAL ;
  PORT
   LAYER M5 ;
   RECT 605.856 0.000 605.880 0.084 ;
  END
 END q_d[447]
 PIN q_d[448]
  DIRECTION OUTPUT ;
  USE SIGNAL ;
  PORT
   LAYER M5 ;
   RECT 606.048 0.000 606.072 0.084 ;
  END
 END q_d[448]
 PIN q_d[449]
  DIRECTION OUTPUT ;
  USE SIGNAL ;
  PORT
   LAYER M5 ;
   RECT 606.240 0.000 606.264 0.084 ;
  END
 END q_d[449]
 PIN q_d[450]
  DIRECTION OUTPUT ;
  USE SIGNAL ;
  PORT
   LAYER M5 ;
   RECT 606.432 0.000 606.456 0.084 ;
  END
 END q_d[450]
 PIN q_d[451]
  DIRECTION OUTPUT ;
  USE SIGNAL ;
  PORT
   LAYER M5 ;
   RECT 606.624 0.000 606.648 0.084 ;
  END
 END q_d[451]
 PIN q_d[452]
  DIRECTION OUTPUT ;
  USE SIGNAL ;
  PORT
   LAYER M5 ;
   RECT 606.816 0.000 606.840 0.084 ;
  END
 END q_d[452]
 PIN q_d[453]
  DIRECTION OUTPUT ;
  USE SIGNAL ;
  PORT
   LAYER M5 ;
   RECT 607.008 0.000 607.032 0.084 ;
  END
 END q_d[453]
 PIN q_d[454]
  DIRECTION OUTPUT ;
  USE SIGNAL ;
  PORT
   LAYER M5 ;
   RECT 607.200 0.000 607.224 0.084 ;
  END
 END q_d[454]
 PIN q_d[455]
  DIRECTION OUTPUT ;
  USE SIGNAL ;
  PORT
   LAYER M5 ;
   RECT 607.392 0.000 607.416 0.084 ;
  END
 END q_d[455]
 PIN q_d[456]
  DIRECTION OUTPUT ;
  USE SIGNAL ;
  PORT
   LAYER M5 ;
   RECT 607.584 0.000 607.608 0.084 ;
  END
 END q_d[456]
 PIN q_d[457]
  DIRECTION OUTPUT ;
  USE SIGNAL ;
  PORT
   LAYER M5 ;
   RECT 607.776 0.000 607.800 0.084 ;
  END
 END q_d[457]
 PIN q_d[458]
  DIRECTION OUTPUT ;
  USE SIGNAL ;
  PORT
   LAYER M5 ;
   RECT 607.968 0.000 607.992 0.084 ;
  END
 END q_d[458]
 PIN q_d[459]
  DIRECTION OUTPUT ;
  USE SIGNAL ;
  PORT
   LAYER M5 ;
   RECT 608.160 0.000 608.184 0.084 ;
  END
 END q_d[459]
 PIN q_d[460]
  DIRECTION OUTPUT ;
  USE SIGNAL ;
  PORT
   LAYER M5 ;
   RECT 608.352 0.000 608.376 0.084 ;
  END
 END q_d[460]
 PIN q_d[461]
  DIRECTION OUTPUT ;
  USE SIGNAL ;
  PORT
   LAYER M5 ;
   RECT 608.544 0.000 608.568 0.084 ;
  END
 END q_d[461]
 PIN q_d[462]
  DIRECTION OUTPUT ;
  USE SIGNAL ;
  PORT
   LAYER M5 ;
   RECT 608.736 0.000 608.760 0.084 ;
  END
 END q_d[462]
 PIN q_d[463]
  DIRECTION OUTPUT ;
  USE SIGNAL ;
  PORT
   LAYER M5 ;
   RECT 608.928 0.000 608.952 0.084 ;
  END
 END q_d[463]
 PIN q_d[464]
  DIRECTION OUTPUT ;
  USE SIGNAL ;
  PORT
   LAYER M5 ;
   RECT 609.120 0.000 609.144 0.084 ;
  END
 END q_d[464]
 PIN q_d[465]
  DIRECTION OUTPUT ;
  USE SIGNAL ;
  PORT
   LAYER M5 ;
   RECT 609.312 0.000 609.336 0.084 ;
  END
 END q_d[465]
 PIN q_d[466]
  DIRECTION OUTPUT ;
  USE SIGNAL ;
  PORT
   LAYER M5 ;
   RECT 609.504 0.000 609.528 0.084 ;
  END
 END q_d[466]
 PIN q_d[467]
  DIRECTION OUTPUT ;
  USE SIGNAL ;
  PORT
   LAYER M5 ;
   RECT 609.696 0.000 609.720 0.084 ;
  END
 END q_d[467]
 PIN q_d[468]
  DIRECTION OUTPUT ;
  USE SIGNAL ;
  PORT
   LAYER M5 ;
   RECT 609.888 0.000 609.912 0.084 ;
  END
 END q_d[468]
 PIN q_d[469]
  DIRECTION OUTPUT ;
  USE SIGNAL ;
  PORT
   LAYER M5 ;
   RECT 610.080 0.000 610.104 0.084 ;
  END
 END q_d[469]
 PIN q_d[470]
  DIRECTION OUTPUT ;
  USE SIGNAL ;
  PORT
   LAYER M5 ;
   RECT 610.272 0.000 610.296 0.084 ;
  END
 END q_d[470]
 PIN q_d[471]
  DIRECTION OUTPUT ;
  USE SIGNAL ;
  PORT
   LAYER M5 ;
   RECT 610.464 0.000 610.488 0.084 ;
  END
 END q_d[471]
 PIN q_d[472]
  DIRECTION OUTPUT ;
  USE SIGNAL ;
  PORT
   LAYER M5 ;
   RECT 610.656 0.000 610.680 0.084 ;
  END
 END q_d[472]
 PIN q_d[473]
  DIRECTION OUTPUT ;
  USE SIGNAL ;
  PORT
   LAYER M5 ;
   RECT 610.848 0.000 610.872 0.084 ;
  END
 END q_d[473]
 PIN q_d[474]
  DIRECTION OUTPUT ;
  USE SIGNAL ;
  PORT
   LAYER M5 ;
   RECT 611.040 0.000 611.064 0.084 ;
  END
 END q_d[474]
 PIN q_d[475]
  DIRECTION OUTPUT ;
  USE SIGNAL ;
  PORT
   LAYER M5 ;
   RECT 611.232 0.000 611.256 0.084 ;
  END
 END q_d[475]
 PIN q_d[476]
  DIRECTION OUTPUT ;
  USE SIGNAL ;
  PORT
   LAYER M5 ;
   RECT 611.424 0.000 611.448 0.084 ;
  END
 END q_d[476]
 PIN q_d[477]
  DIRECTION OUTPUT ;
  USE SIGNAL ;
  PORT
   LAYER M5 ;
   RECT 611.616 0.000 611.640 0.084 ;
  END
 END q_d[477]
 PIN q_d[478]
  DIRECTION OUTPUT ;
  USE SIGNAL ;
  PORT
   LAYER M5 ;
   RECT 611.808 0.000 611.832 0.084 ;
  END
 END q_d[478]
 PIN q_d[479]
  DIRECTION OUTPUT ;
  USE SIGNAL ;
  PORT
   LAYER M5 ;
   RECT 612.000 0.000 612.024 0.084 ;
  END
 END q_d[479]
 PIN q_d[480]
  DIRECTION OUTPUT ;
  USE SIGNAL ;
  PORT
   LAYER M5 ;
   RECT 612.192 0.000 612.216 0.084 ;
  END
 END q_d[480]
 PIN q_d[481]
  DIRECTION OUTPUT ;
  USE SIGNAL ;
  PORT
   LAYER M5 ;
   RECT 612.384 0.000 612.408 0.084 ;
  END
 END q_d[481]
 PIN q_d[482]
  DIRECTION OUTPUT ;
  USE SIGNAL ;
  PORT
   LAYER M5 ;
   RECT 612.576 0.000 612.600 0.084 ;
  END
 END q_d[482]
 PIN q_d[483]
  DIRECTION OUTPUT ;
  USE SIGNAL ;
  PORT
   LAYER M5 ;
   RECT 612.768 0.000 612.792 0.084 ;
  END
 END q_d[483]
 PIN q_d[484]
  DIRECTION OUTPUT ;
  USE SIGNAL ;
  PORT
   LAYER M5 ;
   RECT 612.960 0.000 612.984 0.084 ;
  END
 END q_d[484]
 PIN q_d[485]
  DIRECTION OUTPUT ;
  USE SIGNAL ;
  PORT
   LAYER M5 ;
   RECT 613.152 0.000 613.176 0.084 ;
  END
 END q_d[485]
 PIN q_d[486]
  DIRECTION OUTPUT ;
  USE SIGNAL ;
  PORT
   LAYER M5 ;
   RECT 613.344 0.000 613.368 0.084 ;
  END
 END q_d[486]
 PIN q_d[487]
  DIRECTION OUTPUT ;
  USE SIGNAL ;
  PORT
   LAYER M5 ;
   RECT 613.536 0.000 613.560 0.084 ;
  END
 END q_d[487]
 PIN q_d[488]
  DIRECTION OUTPUT ;
  USE SIGNAL ;
  PORT
   LAYER M5 ;
   RECT 613.728 0.000 613.752 0.084 ;
  END
 END q_d[488]
 PIN q_d[489]
  DIRECTION OUTPUT ;
  USE SIGNAL ;
  PORT
   LAYER M5 ;
   RECT 613.920 0.000 613.944 0.084 ;
  END
 END q_d[489]
 PIN q_d[490]
  DIRECTION OUTPUT ;
  USE SIGNAL ;
  PORT
   LAYER M5 ;
   RECT 614.112 0.000 614.136 0.084 ;
  END
 END q_d[490]
 PIN q_d[491]
  DIRECTION OUTPUT ;
  USE SIGNAL ;
  PORT
   LAYER M5 ;
   RECT 614.304 0.000 614.328 0.084 ;
  END
 END q_d[491]
 PIN q_d[492]
  DIRECTION OUTPUT ;
  USE SIGNAL ;
  PORT
   LAYER M5 ;
   RECT 614.496 0.000 614.520 0.084 ;
  END
 END q_d[492]
 PIN q_d[493]
  DIRECTION OUTPUT ;
  USE SIGNAL ;
  PORT
   LAYER M5 ;
   RECT 614.688 0.000 614.712 0.084 ;
  END
 END q_d[493]
 PIN q_d[494]
  DIRECTION OUTPUT ;
  USE SIGNAL ;
  PORT
   LAYER M5 ;
   RECT 614.880 0.000 614.904 0.084 ;
  END
 END q_d[494]
 PIN q_d[495]
  DIRECTION OUTPUT ;
  USE SIGNAL ;
  PORT
   LAYER M5 ;
   RECT 615.072 0.000 615.096 0.084 ;
  END
 END q_d[495]
 PIN q_d[496]
  DIRECTION OUTPUT ;
  USE SIGNAL ;
  PORT
   LAYER M5 ;
   RECT 615.264 0.000 615.288 0.084 ;
  END
 END q_d[496]
 PIN q_d[497]
  DIRECTION OUTPUT ;
  USE SIGNAL ;
  PORT
   LAYER M5 ;
   RECT 615.456 0.000 615.480 0.084 ;
  END
 END q_d[497]
 PIN q_d[498]
  DIRECTION OUTPUT ;
  USE SIGNAL ;
  PORT
   LAYER M5 ;
   RECT 615.648 0.000 615.672 0.084 ;
  END
 END q_d[498]
 PIN q_d[499]
  DIRECTION OUTPUT ;
  USE SIGNAL ;
  PORT
   LAYER M5 ;
   RECT 615.840 0.000 615.864 0.084 ;
  END
 END q_d[499]
 PIN q_d[500]
  DIRECTION OUTPUT ;
  USE SIGNAL ;
  PORT
   LAYER M5 ;
   RECT 616.032 0.000 616.056 0.084 ;
  END
 END q_d[500]
 PIN q_d[501]
  DIRECTION OUTPUT ;
  USE SIGNAL ;
  PORT
   LAYER M5 ;
   RECT 616.224 0.000 616.248 0.084 ;
  END
 END q_d[501]
 PIN q_d[502]
  DIRECTION OUTPUT ;
  USE SIGNAL ;
  PORT
   LAYER M5 ;
   RECT 616.416 0.000 616.440 0.084 ;
  END
 END q_d[502]
 PIN q_d[503]
  DIRECTION OUTPUT ;
  USE SIGNAL ;
  PORT
   LAYER M5 ;
   RECT 616.608 0.000 616.632 0.084 ;
  END
 END q_d[503]
 PIN q_d[504]
  DIRECTION OUTPUT ;
  USE SIGNAL ;
  PORT
   LAYER M5 ;
   RECT 616.800 0.000 616.824 0.084 ;
  END
 END q_d[504]
 PIN q_d[505]
  DIRECTION OUTPUT ;
  USE SIGNAL ;
  PORT
   LAYER M5 ;
   RECT 616.992 0.000 617.016 0.084 ;
  END
 END q_d[505]
 PIN q_d[506]
  DIRECTION OUTPUT ;
  USE SIGNAL ;
  PORT
   LAYER M5 ;
   RECT 617.184 0.000 617.208 0.084 ;
  END
 END q_d[506]
 PIN q_d[507]
  DIRECTION OUTPUT ;
  USE SIGNAL ;
  PORT
   LAYER M5 ;
   RECT 617.376 0.000 617.400 0.084 ;
  END
 END q_d[507]
 PIN q_d[508]
  DIRECTION OUTPUT ;
  USE SIGNAL ;
  PORT
   LAYER M5 ;
   RECT 617.568 0.000 617.592 0.084 ;
  END
 END q_d[508]
 PIN q_d[509]
  DIRECTION OUTPUT ;
  USE SIGNAL ;
  PORT
   LAYER M5 ;
   RECT 617.760 0.000 617.784 0.084 ;
  END
 END q_d[509]
 PIN q_d[510]
  DIRECTION OUTPUT ;
  USE SIGNAL ;
  PORT
   LAYER M5 ;
   RECT 617.952 0.000 617.976 0.084 ;
  END
 END q_d[510]
 PIN q_d[511]
  DIRECTION OUTPUT ;
  USE SIGNAL ;
  PORT
   LAYER M5 ;
   RECT 618.144 0.000 618.168 0.084 ;
  END
 END q_d[511]
 PIN q_v
  DIRECTION OUTPUT ;
  USE SIGNAL ;
  PORT
   LAYER M5 ;
   RECT 618.336 0.000 618.360 0.084 ;
  END
 END q_v
 PIN q_first
  DIRECTION OUTPUT ;
  USE SIGNAL ;
  PORT
   LAYER M5 ;
   RECT 618.528 0.000 618.552 0.084 ;
  END
 END q_first
 PIN q_unc
  DIRECTION OUTPUT ;
  USE SIGNAL ;
  PORT
   LAYER M5 ;
   RECT 618.720 0.000 618.744 0.084 ;
  END
 END q_unc
 PIN q_nerr[0]
  DIRECTION OUTPUT ;
  USE SIGNAL ;
  PORT
   LAYER M5 ;
   RECT 618.912 0.000 618.936 0.084 ;
  END
 END q_nerr[0]
 PIN q_nerr[1]
  DIRECTION OUTPUT ;
  USE SIGNAL ;
  PORT
   LAYER M5 ;
   RECT 619.104 0.000 619.128 0.084 ;
  END
 END q_nerr[1]
 PIN q_nerr[2]
  DIRECTION OUTPUT ;
  USE SIGNAL ;
  PORT
   LAYER M5 ;
   RECT 619.296 0.000 619.320 0.084 ;
  END
 END q_nerr[2]
 PIN q_nerr[3]
  DIRECTION OUTPUT ;
  USE SIGNAL ;
  PORT
   LAYER M5 ;
   RECT 619.488 0.000 619.512 0.084 ;
  END
 END q_nerr[3]
 PIN q_nerr[4]
  DIRECTION OUTPUT ;
  USE SIGNAL ;
  PORT
   LAYER M5 ;
   RECT 619.680 0.000 619.704 0.084 ;
  END
 END q_nerr[4]
 PIN q_seq[0]
  DIRECTION OUTPUT ;
  USE SIGNAL ;
  PORT
   LAYER M5 ;
   RECT 619.872 0.000 619.896 0.084 ;
  END
 END q_seq[0]
 PIN q_seq[1]
  DIRECTION OUTPUT ;
  USE SIGNAL ;
  PORT
   LAYER M5 ;
   RECT 620.064 0.000 620.088 0.084 ;
  END
 END q_seq[1]
 PIN q_seq[2]
  DIRECTION OUTPUT ;
  USE SIGNAL ;
  PORT
   LAYER M5 ;
   RECT 620.256 0.000 620.280 0.084 ;
  END
 END q_seq[2]
 PIN q_seq[3]
  DIRECTION OUTPUT ;
  USE SIGNAL ;
  PORT
   LAYER M5 ;
   RECT 620.448 0.000 620.472 0.084 ;
  END
 END q_seq[3]
 PIN q_seq[4]
  DIRECTION OUTPUT ;
  USE SIGNAL ;
  PORT
   LAYER M5 ;
   RECT 620.640 0.000 620.664 0.084 ;
  END
 END q_seq[4]
 PIN q_seq[5]
  DIRECTION OUTPUT ;
  USE SIGNAL ;
  PORT
   LAYER M5 ;
   RECT 620.832 0.000 620.856 0.084 ;
  END
 END q_seq[5]
 PIN q_seq[6]
  DIRECTION OUTPUT ;
  USE SIGNAL ;
  PORT
   LAYER M5 ;
   RECT 621.024 0.000 621.048 0.084 ;
  END
 END q_seq[6]
 PIN q_seq[7]
  DIRECTION OUTPUT ;
  USE SIGNAL ;
  PORT
   LAYER M5 ;
   RECT 621.216 0.000 621.240 0.084 ;
  END
 END q_seq[7]
 PIN n_corr[0]
  DIRECTION OUTPUT ;
  USE SIGNAL ;
  PORT
   LAYER M5 ;
   RECT 420.000 0.000 420.024 0.084 ;
  END
 END n_corr[0]
 PIN n_corr[1]
  DIRECTION OUTPUT ;
  USE SIGNAL ;
  PORT
   LAYER M5 ;
   RECT 420.192 0.000 420.216 0.084 ;
  END
 END n_corr[1]
 PIN n_corr[2]
  DIRECTION OUTPUT ;
  USE SIGNAL ;
  PORT
   LAYER M5 ;
   RECT 420.384 0.000 420.408 0.084 ;
  END
 END n_corr[2]
 PIN n_corr[3]
  DIRECTION OUTPUT ;
  USE SIGNAL ;
  PORT
   LAYER M5 ;
   RECT 420.576 0.000 420.600 0.084 ;
  END
 END n_corr[3]
 PIN n_corr[4]
  DIRECTION OUTPUT ;
  USE SIGNAL ;
  PORT
   LAYER M5 ;
   RECT 420.768 0.000 420.792 0.084 ;
  END
 END n_corr[4]
 PIN n_corr[5]
  DIRECTION OUTPUT ;
  USE SIGNAL ;
  PORT
   LAYER M5 ;
   RECT 420.960 0.000 420.984 0.084 ;
  END
 END n_corr[5]
 PIN n_corr[6]
  DIRECTION OUTPUT ;
  USE SIGNAL ;
  PORT
   LAYER M5 ;
   RECT 421.152 0.000 421.176 0.084 ;
  END
 END n_corr[6]
 PIN n_corr[7]
  DIRECTION OUTPUT ;
  USE SIGNAL ;
  PORT
   LAYER M5 ;
   RECT 421.344 0.000 421.368 0.084 ;
  END
 END n_corr[7]
 PIN n_corr[8]
  DIRECTION OUTPUT ;
  USE SIGNAL ;
  PORT
   LAYER M5 ;
   RECT 421.536 0.000 421.560 0.084 ;
  END
 END n_corr[8]
 PIN n_corr[9]
  DIRECTION OUTPUT ;
  USE SIGNAL ;
  PORT
   LAYER M5 ;
   RECT 421.728 0.000 421.752 0.084 ;
  END
 END n_corr[9]
 PIN n_corr[10]
  DIRECTION OUTPUT ;
  USE SIGNAL ;
  PORT
   LAYER M5 ;
   RECT 421.920 0.000 421.944 0.084 ;
  END
 END n_corr[10]
 PIN n_corr[11]
  DIRECTION OUTPUT ;
  USE SIGNAL ;
  PORT
   LAYER M5 ;
   RECT 422.112 0.000 422.136 0.084 ;
  END
 END n_corr[11]
 PIN n_corr[12]
  DIRECTION OUTPUT ;
  USE SIGNAL ;
  PORT
   LAYER M5 ;
   RECT 422.304 0.000 422.328 0.084 ;
  END
 END n_corr[12]
 PIN n_corr[13]
  DIRECTION OUTPUT ;
  USE SIGNAL ;
  PORT
   LAYER M5 ;
   RECT 422.496 0.000 422.520 0.084 ;
  END
 END n_corr[13]
 PIN n_corr[14]
  DIRECTION OUTPUT ;
  USE SIGNAL ;
  PORT
   LAYER M5 ;
   RECT 422.688 0.000 422.712 0.084 ;
  END
 END n_corr[14]
 PIN n_corr[15]
  DIRECTION OUTPUT ;
  USE SIGNAL ;
  PORT
   LAYER M5 ;
   RECT 422.880 0.000 422.904 0.084 ;
  END
 END n_corr[15]
 PIN n_corr[16]
  DIRECTION OUTPUT ;
  USE SIGNAL ;
  PORT
   LAYER M5 ;
   RECT 423.072 0.000 423.096 0.084 ;
  END
 END n_corr[16]
 PIN n_corr[17]
  DIRECTION OUTPUT ;
  USE SIGNAL ;
  PORT
   LAYER M5 ;
   RECT 423.264 0.000 423.288 0.084 ;
  END
 END n_corr[17]
 PIN n_corr[18]
  DIRECTION OUTPUT ;
  USE SIGNAL ;
  PORT
   LAYER M5 ;
   RECT 423.456 0.000 423.480 0.084 ;
  END
 END n_corr[18]
 PIN n_corr[19]
  DIRECTION OUTPUT ;
  USE SIGNAL ;
  PORT
   LAYER M5 ;
   RECT 423.648 0.000 423.672 0.084 ;
  END
 END n_corr[19]
 PIN n_corr[20]
  DIRECTION OUTPUT ;
  USE SIGNAL ;
  PORT
   LAYER M5 ;
   RECT 423.840 0.000 423.864 0.084 ;
  END
 END n_corr[20]
 PIN n_corr[21]
  DIRECTION OUTPUT ;
  USE SIGNAL ;
  PORT
   LAYER M5 ;
   RECT 424.032 0.000 424.056 0.084 ;
  END
 END n_corr[21]
 PIN n_corr[22]
  DIRECTION OUTPUT ;
  USE SIGNAL ;
  PORT
   LAYER M5 ;
   RECT 424.224 0.000 424.248 0.084 ;
  END
 END n_corr[22]
 PIN n_corr[23]
  DIRECTION OUTPUT ;
  USE SIGNAL ;
  PORT
   LAYER M5 ;
   RECT 424.416 0.000 424.440 0.084 ;
  END
 END n_corr[23]
 PIN n_corr[24]
  DIRECTION OUTPUT ;
  USE SIGNAL ;
  PORT
   LAYER M5 ;
   RECT 424.608 0.000 424.632 0.084 ;
  END
 END n_corr[24]
 PIN n_corr[25]
  DIRECTION OUTPUT ;
  USE SIGNAL ;
  PORT
   LAYER M5 ;
   RECT 424.800 0.000 424.824 0.084 ;
  END
 END n_corr[25]
 PIN n_corr[26]
  DIRECTION OUTPUT ;
  USE SIGNAL ;
  PORT
   LAYER M5 ;
   RECT 424.992 0.000 425.016 0.084 ;
  END
 END n_corr[26]
 PIN n_corr[27]
  DIRECTION OUTPUT ;
  USE SIGNAL ;
  PORT
   LAYER M5 ;
   RECT 425.184 0.000 425.208 0.084 ;
  END
 END n_corr[27]
 PIN n_corr[28]
  DIRECTION OUTPUT ;
  USE SIGNAL ;
  PORT
   LAYER M5 ;
   RECT 425.376 0.000 425.400 0.084 ;
  END
 END n_corr[28]
 PIN n_corr[29]
  DIRECTION OUTPUT ;
  USE SIGNAL ;
  PORT
   LAYER M5 ;
   RECT 425.568 0.000 425.592 0.084 ;
  END
 END n_corr[29]
 PIN n_corr[30]
  DIRECTION OUTPUT ;
  USE SIGNAL ;
  PORT
   LAYER M5 ;
   RECT 425.760 0.000 425.784 0.084 ;
  END
 END n_corr[30]
 PIN n_corr[31]
  DIRECTION OUTPUT ;
  USE SIGNAL ;
  PORT
   LAYER M5 ;
   RECT 425.952 0.000 425.976 0.084 ;
  END
 END n_corr[31]
 PIN n_unc[0]
  DIRECTION OUTPUT ;
  USE SIGNAL ;
  PORT
   LAYER M5 ;
   RECT 426.144 0.000 426.168 0.084 ;
  END
 END n_unc[0]
 PIN n_unc[1]
  DIRECTION OUTPUT ;
  USE SIGNAL ;
  PORT
   LAYER M5 ;
   RECT 426.336 0.000 426.360 0.084 ;
  END
 END n_unc[1]
 PIN n_unc[2]
  DIRECTION OUTPUT ;
  USE SIGNAL ;
  PORT
   LAYER M5 ;
   RECT 426.528 0.000 426.552 0.084 ;
  END
 END n_unc[2]
 PIN n_unc[3]
  DIRECTION OUTPUT ;
  USE SIGNAL ;
  PORT
   LAYER M5 ;
   RECT 426.720 0.000 426.744 0.084 ;
  END
 END n_unc[3]
 PIN n_unc[4]
  DIRECTION OUTPUT ;
  USE SIGNAL ;
  PORT
   LAYER M5 ;
   RECT 426.912 0.000 426.936 0.084 ;
  END
 END n_unc[4]
 PIN n_unc[5]
  DIRECTION OUTPUT ;
  USE SIGNAL ;
  PORT
   LAYER M5 ;
   RECT 427.104 0.000 427.128 0.084 ;
  END
 END n_unc[5]
 PIN n_unc[6]
  DIRECTION OUTPUT ;
  USE SIGNAL ;
  PORT
   LAYER M5 ;
   RECT 427.296 0.000 427.320 0.084 ;
  END
 END n_unc[6]
 PIN n_unc[7]
  DIRECTION OUTPUT ;
  USE SIGNAL ;
  PORT
   LAYER M5 ;
   RECT 427.488 0.000 427.512 0.084 ;
  END
 END n_unc[7]
 PIN n_unc[8]
  DIRECTION OUTPUT ;
  USE SIGNAL ;
  PORT
   LAYER M5 ;
   RECT 427.680 0.000 427.704 0.084 ;
  END
 END n_unc[8]
 PIN n_unc[9]
  DIRECTION OUTPUT ;
  USE SIGNAL ;
  PORT
   LAYER M5 ;
   RECT 427.872 0.000 427.896 0.084 ;
  END
 END n_unc[9]
 PIN n_unc[10]
  DIRECTION OUTPUT ;
  USE SIGNAL ;
  PORT
   LAYER M5 ;
   RECT 428.064 0.000 428.088 0.084 ;
  END
 END n_unc[10]
 PIN n_unc[11]
  DIRECTION OUTPUT ;
  USE SIGNAL ;
  PORT
   LAYER M5 ;
   RECT 428.256 0.000 428.280 0.084 ;
  END
 END n_unc[11]
 PIN n_unc[12]
  DIRECTION OUTPUT ;
  USE SIGNAL ;
  PORT
   LAYER M5 ;
   RECT 428.448 0.000 428.472 0.084 ;
  END
 END n_unc[12]
 PIN n_unc[13]
  DIRECTION OUTPUT ;
  USE SIGNAL ;
  PORT
   LAYER M5 ;
   RECT 428.640 0.000 428.664 0.084 ;
  END
 END n_unc[13]
 PIN n_unc[14]
  DIRECTION OUTPUT ;
  USE SIGNAL ;
  PORT
   LAYER M5 ;
   RECT 428.832 0.000 428.856 0.084 ;
  END
 END n_unc[14]
 PIN n_unc[15]
  DIRECTION OUTPUT ;
  USE SIGNAL ;
  PORT
   LAYER M5 ;
   RECT 429.024 0.000 429.048 0.084 ;
  END
 END n_unc[15]
 PIN n_unc[16]
  DIRECTION OUTPUT ;
  USE SIGNAL ;
  PORT
   LAYER M5 ;
   RECT 429.216 0.000 429.240 0.084 ;
  END
 END n_unc[16]
 PIN n_unc[17]
  DIRECTION OUTPUT ;
  USE SIGNAL ;
  PORT
   LAYER M5 ;
   RECT 429.408 0.000 429.432 0.084 ;
  END
 END n_unc[17]
 PIN n_unc[18]
  DIRECTION OUTPUT ;
  USE SIGNAL ;
  PORT
   LAYER M5 ;
   RECT 429.600 0.000 429.624 0.084 ;
  END
 END n_unc[18]
 PIN n_unc[19]
  DIRECTION OUTPUT ;
  USE SIGNAL ;
  PORT
   LAYER M5 ;
   RECT 429.792 0.000 429.816 0.084 ;
  END
 END n_unc[19]
 PIN n_unc[20]
  DIRECTION OUTPUT ;
  USE SIGNAL ;
  PORT
   LAYER M5 ;
   RECT 429.984 0.000 430.008 0.084 ;
  END
 END n_unc[20]
 PIN n_unc[21]
  DIRECTION OUTPUT ;
  USE SIGNAL ;
  PORT
   LAYER M5 ;
   RECT 430.176 0.000 430.200 0.084 ;
  END
 END n_unc[21]
 PIN n_unc[22]
  DIRECTION OUTPUT ;
  USE SIGNAL ;
  PORT
   LAYER M5 ;
   RECT 430.368 0.000 430.392 0.084 ;
  END
 END n_unc[22]
 PIN n_unc[23]
  DIRECTION OUTPUT ;
  USE SIGNAL ;
  PORT
   LAYER M5 ;
   RECT 430.560 0.000 430.584 0.084 ;
  END
 END n_unc[23]
 PIN n_unc[24]
  DIRECTION OUTPUT ;
  USE SIGNAL ;
  PORT
   LAYER M5 ;
   RECT 430.752 0.000 430.776 0.084 ;
  END
 END n_unc[24]
 PIN n_unc[25]
  DIRECTION OUTPUT ;
  USE SIGNAL ;
  PORT
   LAYER M5 ;
   RECT 430.944 0.000 430.968 0.084 ;
  END
 END n_unc[25]
 PIN n_unc[26]
  DIRECTION OUTPUT ;
  USE SIGNAL ;
  PORT
   LAYER M5 ;
   RECT 431.136 0.000 431.160 0.084 ;
  END
 END n_unc[26]
 PIN n_unc[27]
  DIRECTION OUTPUT ;
  USE SIGNAL ;
  PORT
   LAYER M5 ;
   RECT 431.328 0.000 431.352 0.084 ;
  END
 END n_unc[27]
 PIN n_unc[28]
  DIRECTION OUTPUT ;
  USE SIGNAL ;
  PORT
   LAYER M5 ;
   RECT 431.520 0.000 431.544 0.084 ;
  END
 END n_unc[28]
 PIN n_unc[29]
  DIRECTION OUTPUT ;
  USE SIGNAL ;
  PORT
   LAYER M5 ;
   RECT 431.712 0.000 431.736 0.084 ;
  END
 END n_unc[29]
 PIN n_unc[30]
  DIRECTION OUTPUT ;
  USE SIGNAL ;
  PORT
   LAYER M5 ;
   RECT 431.904 0.000 431.928 0.084 ;
  END
 END n_unc[30]
 PIN n_unc[31]
  DIRECTION OUTPUT ;
  USE SIGNAL ;
  PORT
   LAYER M5 ;
   RECT 432.096 0.000 432.120 0.084 ;
  END
 END n_unc[31]
 PIN ck
  DIRECTION INPUT ;
  USE CLOCK ;
  PORT
   LAYER M5 ;
   RECT 362.880 280.716 362.904 280.800 ;
  END
 END ck
END ot_s81_rck_rxb
END LIBRARY
